VERSION 5.8 ;
BUSBITCHARS "[]" ;
DIVIDERCHAR "/" ;
UNITS
    DATABASE MICRONS 1000 ;
END UNITS

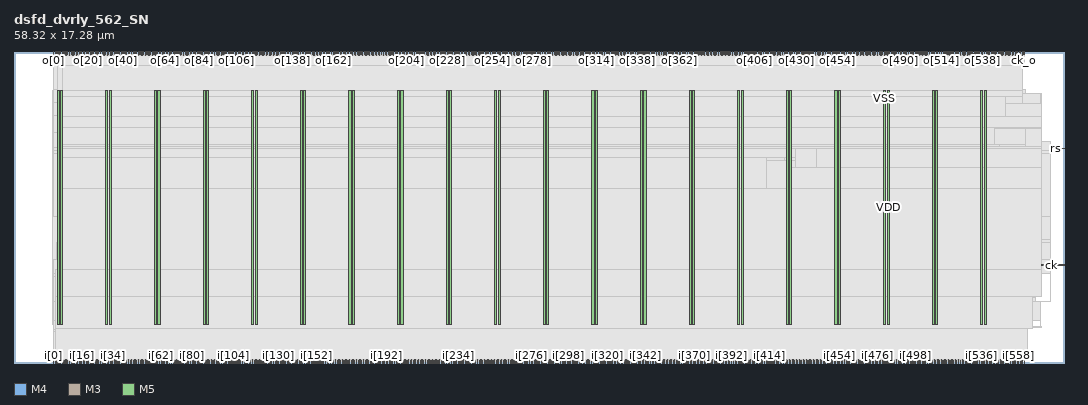
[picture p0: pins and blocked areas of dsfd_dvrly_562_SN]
MACRO dsfd_dvrly_562_SN
  FOREIGN dsfd_dvrly_562_SN 0 0 ;
  CLASS BLOCK ;
  SIZE 58.32 BY 17.28 ;
  PIN ck
    DIRECTION INPUT ;
    USE SIGNAL ;
    PORT
      LAYER M4 ;
        RECT  58.128 5.424 58.32 5.448 ;
    END
    PORT
      LAYER M4 ;
        RECT  57.089 5.424 58.14 5.448 ;
    END
  END ck
  PIN ck_o
    DIRECTION OUTPUT ;
    USE SIGNAL ;
    PORT
      LAYER M3 ;
        RECT  56.088 17.136 56.106 17.28 ;
    END
  END ck_o
  PIN i[0]
    DIRECTION INPUT ;
    USE SIGNAL ;
    PORT
      LAYER M3 ;
        RECT  2.196 0 2.214 0.144 ;
    END
  END i[0]
  PIN i[100]
    DIRECTION INPUT ;
    USE SIGNAL ;
    PORT
      LAYER M3 ;
        RECT  11.808 0 11.826 0.144 ;
    END
  END i[100]
  PIN i[101]
    DIRECTION INPUT ;
    USE SIGNAL ;
    PORT
      LAYER M5 ;
        RECT  11.904 0 11.928 0.192 ;
    END
  END i[101]
  PIN i[102]
    DIRECTION INPUT ;
    USE SIGNAL ;
    PORT
      LAYER M3 ;
        RECT  11.988 0 12.006 0.144 ;
    END
  END i[102]
  PIN i[103]
    DIRECTION INPUT ;
    USE SIGNAL ;
    PORT
      LAYER M5 ;
        RECT  12.096 0 12.12 0.192 ;
    END
  END i[103]
  PIN i[104]
    DIRECTION INPUT ;
    USE SIGNAL ;
    PORT
      LAYER M3 ;
        RECT  12.204 0 12.222 0.144 ;
    END
  END i[104]
  PIN i[105]
    DIRECTION INPUT ;
    USE SIGNAL ;
    PORT
      LAYER M5 ;
        RECT  12.288 0 12.312 0.192 ;
    END
  END i[105]
  PIN i[106]
    DIRECTION INPUT ;
    USE SIGNAL ;
    PORT
      LAYER M3 ;
        RECT  12.384 0 12.402 0.144 ;
    END
  END i[106]
  PIN i[107]
    DIRECTION INPUT ;
    USE SIGNAL ;
    PORT
      LAYER M5 ;
        RECT  12.48 0 12.504 0.192 ;
    END
  END i[107]
  PIN i[108]
    DIRECTION INPUT ;
    USE SIGNAL ;
    PORT
      LAYER M3 ;
        RECT  12.564 0 12.582 0.144 ;
    END
  END i[108]
  PIN i[109]
    DIRECTION INPUT ;
    USE SIGNAL ;
    PORT
      LAYER M5 ;
        RECT  12.672 0 12.696 0.192 ;
    END
  END i[109]
  PIN i[10]
    DIRECTION INPUT ;
    USE SIGNAL ;
    PORT
      LAYER M3 ;
        RECT  3.168 0 3.186 0.144 ;
    END
  END i[10]
  PIN i[110]
    DIRECTION INPUT ;
    USE SIGNAL ;
    PORT
      LAYER M3 ;
        RECT  12.78 0 12.798 0.144 ;
    END
  END i[110]
  PIN i[111]
    DIRECTION INPUT ;
    USE SIGNAL ;
    PORT
      LAYER M5 ;
        RECT  12.864 0 12.888 0.192 ;
    END
  END i[111]
  PIN i[112]
    DIRECTION INPUT ;
    USE SIGNAL ;
    PORT
      LAYER M3 ;
        RECT  12.96 0 12.978 0.144 ;
    END
  END i[112]
  PIN i[113]
    DIRECTION INPUT ;
    USE SIGNAL ;
    PORT
      LAYER M5 ;
        RECT  13.056 0 13.08 0.192 ;
    END
  END i[113]
  PIN i[114]
    DIRECTION INPUT ;
    USE SIGNAL ;
    PORT
      LAYER M3 ;
        RECT  13.14 0 13.158 0.144 ;
    END
  END i[114]
  PIN i[115]
    DIRECTION INPUT ;
    USE SIGNAL ;
    PORT
      LAYER M5 ;
        RECT  13.248 0 13.272 0.192 ;
    END
  END i[115]
  PIN i[116]
    DIRECTION INPUT ;
    USE SIGNAL ;
    PORT
      LAYER M3 ;
        RECT  13.356 0 13.374 0.144 ;
    END
  END i[116]
  PIN i[117]
    DIRECTION INPUT ;
    USE SIGNAL ;
    PORT
      LAYER M5 ;
        RECT  13.44 0 13.464 0.192 ;
    END
  END i[117]
  PIN i[118]
    DIRECTION INPUT ;
    USE SIGNAL ;
    PORT
      LAYER M3 ;
        RECT  13.536 0 13.554 0.144 ;
    END
  END i[118]
  PIN i[119]
    DIRECTION INPUT ;
    USE SIGNAL ;
    PORT
      LAYER M5 ;
        RECT  13.632 0 13.656 0.192 ;
    END
  END i[119]
  PIN i[11]
    DIRECTION INPUT ;
    USE SIGNAL ;
    PORT
      LAYER M5 ;
        RECT  3.264 0 3.288 0.192 ;
    END
  END i[11]
  PIN i[120]
    DIRECTION INPUT ;
    USE SIGNAL ;
    PORT
      LAYER M3 ;
        RECT  13.716 0 13.734 0.144 ;
    END
  END i[120]
  PIN i[121]
    DIRECTION INPUT ;
    USE SIGNAL ;
    PORT
      LAYER M5 ;
        RECT  13.824 0 13.848 0.192 ;
    END
  END i[121]
  PIN i[122]
    DIRECTION INPUT ;
    USE SIGNAL ;
    PORT
      LAYER M3 ;
        RECT  13.932 0 13.95 0.144 ;
    END
  END i[122]
  PIN i[123]
    DIRECTION INPUT ;
    USE SIGNAL ;
    PORT
      LAYER M5 ;
        RECT  14.016 0 14.04 0.192 ;
    END
  END i[123]
  PIN i[124]
    DIRECTION INPUT ;
    USE SIGNAL ;
    PORT
      LAYER M3 ;
        RECT  14.112 0 14.13 0.144 ;
    END
  END i[124]
  PIN i[125]
    DIRECTION INPUT ;
    USE SIGNAL ;
    PORT
      LAYER M5 ;
        RECT  14.208 0 14.232 0.192 ;
    END
  END i[125]
  PIN i[126]
    DIRECTION INPUT ;
    USE SIGNAL ;
    PORT
      LAYER M3 ;
        RECT  14.292 0 14.31 0.144 ;
    END
  END i[126]
  PIN i[127]
    DIRECTION INPUT ;
    USE SIGNAL ;
    PORT
      LAYER M5 ;
        RECT  14.4 0 14.424 0.192 ;
    END
  END i[127]
  PIN i[128]
    DIRECTION INPUT ;
    USE SIGNAL ;
    PORT
      LAYER M3 ;
        RECT  14.508 0 14.526 0.144 ;
    END
  END i[128]
  PIN i[129]
    DIRECTION INPUT ;
    USE SIGNAL ;
    PORT
      LAYER M5 ;
        RECT  14.592 0 14.616 0.192 ;
    END
  END i[129]
  PIN i[12]
    DIRECTION INPUT ;
    USE SIGNAL ;
    PORT
      LAYER M3 ;
        RECT  3.348 0 3.366 0.144 ;
    END
  END i[12]
  PIN i[130]
    DIRECTION INPUT ;
    USE SIGNAL ;
    PORT
      LAYER M3 ;
        RECT  14.688 0 14.706 0.144 ;
    END
  END i[130]
  PIN i[131]
    DIRECTION INPUT ;
    USE SIGNAL ;
    PORT
      LAYER M5 ;
        RECT  14.784 0 14.808 0.192 ;
    END
  END i[131]
  PIN i[132]
    DIRECTION INPUT ;
    USE SIGNAL ;
    PORT
      LAYER M3 ;
        RECT  14.868 0 14.886 0.144 ;
    END
  END i[132]
  PIN i[133]
    DIRECTION INPUT ;
    USE SIGNAL ;
    PORT
      LAYER M5 ;
        RECT  14.976 0 15 0.192 ;
    END
  END i[133]
  PIN i[134]
    DIRECTION INPUT ;
    USE SIGNAL ;
    PORT
      LAYER M3 ;
        RECT  15.084 0 15.102 0.144 ;
    END
  END i[134]
  PIN i[135]
    DIRECTION INPUT ;
    USE SIGNAL ;
    PORT
      LAYER M5 ;
        RECT  15.168 0 15.192 0.192 ;
    END
  END i[135]
  PIN i[136]
    DIRECTION INPUT ;
    USE SIGNAL ;
    PORT
      LAYER M3 ;
        RECT  15.264 0 15.282 0.144 ;
    END
  END i[136]
  PIN i[137]
    DIRECTION INPUT ;
    USE SIGNAL ;
    PORT
      LAYER M5 ;
        RECT  15.36 0 15.384 0.192 ;
    END
  END i[137]
  PIN i[138]
    DIRECTION INPUT ;
    USE SIGNAL ;
    PORT
      LAYER M3 ;
        RECT  15.444 0 15.462 0.144 ;
    END
  END i[138]
  PIN i[139]
    DIRECTION INPUT ;
    USE SIGNAL ;
    PORT
      LAYER M5 ;
        RECT  15.552 0 15.576 0.192 ;
    END
  END i[139]
  PIN i[13]
    DIRECTION INPUT ;
    USE SIGNAL ;
    PORT
      LAYER M5 ;
        RECT  3.456 0 3.48 0.192 ;
    END
  END i[13]
  PIN i[140]
    DIRECTION INPUT ;
    USE SIGNAL ;
    PORT
      LAYER M3 ;
        RECT  15.66 0 15.678 0.144 ;
    END
  END i[140]
  PIN i[141]
    DIRECTION INPUT ;
    USE SIGNAL ;
    PORT
      LAYER M5 ;
        RECT  15.744 0 15.768 0.192 ;
    END
  END i[141]
  PIN i[142]
    DIRECTION INPUT ;
    USE SIGNAL ;
    PORT
      LAYER M3 ;
        RECT  15.84 0 15.858 0.144 ;
    END
  END i[142]
  PIN i[143]
    DIRECTION INPUT ;
    USE SIGNAL ;
    PORT
      LAYER M5 ;
        RECT  15.936 0 15.96 0.192 ;
    END
  END i[143]
  PIN i[144]
    DIRECTION INPUT ;
    USE SIGNAL ;
    PORT
      LAYER M3 ;
        RECT  16.02 0 16.038 0.144 ;
    END
  END i[144]
  PIN i[145]
    DIRECTION INPUT ;
    USE SIGNAL ;
    PORT
      LAYER M5 ;
        RECT  16.128 0 16.152 0.192 ;
    END
  END i[145]
  PIN i[146]
    DIRECTION INPUT ;
    USE SIGNAL ;
    PORT
      LAYER M3 ;
        RECT  16.236 0 16.254 0.144 ;
    END
  END i[146]
  PIN i[147]
    DIRECTION INPUT ;
    USE SIGNAL ;
    PORT
      LAYER M5 ;
        RECT  16.32 0 16.344 0.192 ;
    END
  END i[147]
  PIN i[148]
    DIRECTION INPUT ;
    USE SIGNAL ;
    PORT
      LAYER M3 ;
        RECT  16.416 0 16.434 0.144 ;
    END
  END i[148]
  PIN i[149]
    DIRECTION INPUT ;
    USE SIGNAL ;
    PORT
      LAYER M5 ;
        RECT  16.512 0 16.536 0.192 ;
    END
  END i[149]
  PIN i[14]
    DIRECTION INPUT ;
    USE SIGNAL ;
    PORT
      LAYER M3 ;
        RECT  3.528 0 3.546 0.144 ;
    END
  END i[14]
  PIN i[150]
    DIRECTION INPUT ;
    USE SIGNAL ;
    PORT
      LAYER M3 ;
        RECT  16.596 0 16.614 0.144 ;
    END
  END i[150]
  PIN i[151]
    DIRECTION INPUT ;
    USE SIGNAL ;
    PORT
      LAYER M5 ;
        RECT  16.704 0 16.728 0.192 ;
    END
  END i[151]
  PIN i[152]
    DIRECTION INPUT ;
    USE SIGNAL ;
    PORT
      LAYER M3 ;
        RECT  16.812 0 16.83 0.144 ;
    END
  END i[152]
  PIN i[153]
    DIRECTION INPUT ;
    USE SIGNAL ;
    PORT
      LAYER M5 ;
        RECT  16.896 0 16.92 0.192 ;
    END
  END i[153]
  PIN i[154]
    DIRECTION INPUT ;
    USE SIGNAL ;
    PORT
      LAYER M3 ;
        RECT  16.992 0 17.01 0.144 ;
    END
  END i[154]
  PIN i[155]
    DIRECTION INPUT ;
    USE SIGNAL ;
    PORT
      LAYER M5 ;
        RECT  17.088 0 17.112 0.192 ;
    END
  END i[155]
  PIN i[156]
    DIRECTION INPUT ;
    USE SIGNAL ;
    PORT
      LAYER M3 ;
        RECT  17.172 0 17.19 0.144 ;
    END
  END i[156]
  PIN i[157]
    DIRECTION INPUT ;
    USE SIGNAL ;
    PORT
      LAYER M5 ;
        RECT  17.28 0 17.304 0.192 ;
    END
  END i[157]
  PIN i[158]
    DIRECTION INPUT ;
    USE SIGNAL ;
    PORT
      LAYER M3 ;
        RECT  17.388 0 17.406 0.144 ;
    END
  END i[158]
  PIN i[159]
    DIRECTION INPUT ;
    USE SIGNAL ;
    PORT
      LAYER M5 ;
        RECT  17.472 0 17.496 0.192 ;
    END
  END i[159]
  PIN i[15]
    DIRECTION INPUT ;
    USE SIGNAL ;
    PORT
      LAYER M5 ;
        RECT  3.648 0 3.672 0.192 ;
    END
  END i[15]
  PIN i[160]
    DIRECTION INPUT ;
    USE SIGNAL ;
    PORT
      LAYER M3 ;
        RECT  17.568 0 17.586 0.144 ;
    END
  END i[160]
  PIN i[161]
    DIRECTION INPUT ;
    USE SIGNAL ;
    PORT
      LAYER M5 ;
        RECT  17.664 0 17.688 0.192 ;
    END
  END i[161]
  PIN i[162]
    DIRECTION INPUT ;
    USE SIGNAL ;
    PORT
      LAYER M3 ;
        RECT  17.748 0 17.766 0.144 ;
    END
  END i[162]
  PIN i[163]
    DIRECTION INPUT ;
    USE SIGNAL ;
    PORT
      LAYER M5 ;
        RECT  17.856 0 17.88 0.192 ;
    END
  END i[163]
  PIN i[164]
    DIRECTION INPUT ;
    USE SIGNAL ;
    PORT
      LAYER M3 ;
        RECT  17.964 0 17.982 0.144 ;
    END
  END i[164]
  PIN i[165]
    DIRECTION INPUT ;
    USE SIGNAL ;
    PORT
      LAYER M5 ;
        RECT  18.048 0 18.072 0.192 ;
    END
  END i[165]
  PIN i[166]
    DIRECTION INPUT ;
    USE SIGNAL ;
    PORT
      LAYER M3 ;
        RECT  18.144 0 18.162 0.144 ;
    END
  END i[166]
  PIN i[167]
    DIRECTION INPUT ;
    USE SIGNAL ;
    PORT
      LAYER M5 ;
        RECT  18.24 0 18.264 0.192 ;
    END
  END i[167]
  PIN i[168]
    DIRECTION INPUT ;
    USE SIGNAL ;
    PORT
      LAYER M3 ;
        RECT  18.324 0 18.342 0.144 ;
    END
  END i[168]
  PIN i[169]
    DIRECTION INPUT ;
    USE SIGNAL ;
    PORT
      LAYER M5 ;
        RECT  18.432 0 18.456 0.192 ;
    END
  END i[169]
  PIN i[16]
    DIRECTION INPUT ;
    USE SIGNAL ;
    PORT
      LAYER M3 ;
        RECT  3.744 0 3.762 0.144 ;
    END
  END i[16]
  PIN i[170]
    DIRECTION INPUT ;
    USE SIGNAL ;
    PORT
      LAYER M3 ;
        RECT  18.54 0 18.558 0.144 ;
    END
  END i[170]
  PIN i[171]
    DIRECTION INPUT ;
    USE SIGNAL ;
    PORT
      LAYER M5 ;
        RECT  18.624 0 18.648 0.192 ;
    END
  END i[171]
  PIN i[172]
    DIRECTION INPUT ;
    USE SIGNAL ;
    PORT
      LAYER M3 ;
        RECT  18.72 0 18.738 0.144 ;
    END
  END i[172]
  PIN i[173]
    DIRECTION INPUT ;
    USE SIGNAL ;
    PORT
      LAYER M5 ;
        RECT  18.816 0 18.84 0.192 ;
    END
  END i[173]
  PIN i[174]
    DIRECTION INPUT ;
    USE SIGNAL ;
    PORT
      LAYER M3 ;
        RECT  18.9 0 18.918 0.144 ;
    END
  END i[174]
  PIN i[175]
    DIRECTION INPUT ;
    USE SIGNAL ;
    PORT
      LAYER M5 ;
        RECT  19.008 0 19.032 0.192 ;
    END
  END i[175]
  PIN i[176]
    DIRECTION INPUT ;
    USE SIGNAL ;
    PORT
      LAYER M3 ;
        RECT  19.116 0 19.134 0.144 ;
    END
  END i[176]
  PIN i[177]
    DIRECTION INPUT ;
    USE SIGNAL ;
    PORT
      LAYER M5 ;
        RECT  19.2 0 19.224 0.192 ;
    END
  END i[177]
  PIN i[178]
    DIRECTION INPUT ;
    USE SIGNAL ;
    PORT
      LAYER M3 ;
        RECT  19.296 0 19.314 0.144 ;
    END
  END i[178]
  PIN i[179]
    DIRECTION INPUT ;
    USE SIGNAL ;
    PORT
      LAYER M5 ;
        RECT  19.392 0 19.416 0.192 ;
    END
  END i[179]
  PIN i[17]
    DIRECTION INPUT ;
    USE SIGNAL ;
    PORT
      LAYER M5 ;
        RECT  3.84 0 3.864 0.192 ;
    END
  END i[17]
  PIN i[180]
    DIRECTION INPUT ;
    USE SIGNAL ;
    PORT
      LAYER M3 ;
        RECT  19.512 0 19.53 0.144 ;
    END
  END i[180]
  PIN i[181]
    DIRECTION INPUT ;
    USE SIGNAL ;
    PORT
      LAYER M5 ;
        RECT  19.584 0 19.608 0.192 ;
    END
  END i[181]
  PIN i[182]
    DIRECTION INPUT ;
    USE SIGNAL ;
    PORT
      LAYER M3 ;
        RECT  19.692 0 19.71 0.144 ;
    END
  END i[182]
  PIN i[183]
    DIRECTION INPUT ;
    USE SIGNAL ;
    PORT
      LAYER M5 ;
        RECT  19.776 0 19.8 0.192 ;
    END
  END i[183]
  PIN i[184]
    DIRECTION INPUT ;
    USE SIGNAL ;
    PORT
      LAYER M3 ;
        RECT  19.872 0 19.89 0.144 ;
    END
  END i[184]
  PIN i[185]
    DIRECTION INPUT ;
    USE SIGNAL ;
    PORT
      LAYER M5 ;
        RECT  19.968 0 19.992 0.192 ;
    END
  END i[185]
  PIN i[186]
    DIRECTION INPUT ;
    USE SIGNAL ;
    PORT
      LAYER M3 ;
        RECT  20.088 0 20.106 0.144 ;
    END
  END i[186]
  PIN i[187]
    DIRECTION INPUT ;
    USE SIGNAL ;
    PORT
      LAYER M5 ;
        RECT  20.16 0 20.184 0.192 ;
    END
  END i[187]
  PIN i[188]
    DIRECTION INPUT ;
    USE SIGNAL ;
    PORT
      LAYER M3 ;
        RECT  20.268 0 20.286 0.144 ;
    END
  END i[188]
  PIN i[189]
    DIRECTION INPUT ;
    USE SIGNAL ;
    PORT
      LAYER M5 ;
        RECT  20.352 0 20.376 0.192 ;
    END
  END i[189]
  PIN i[18]
    DIRECTION INPUT ;
    USE SIGNAL ;
    PORT
      LAYER M3 ;
        RECT  3.924 0 3.942 0.144 ;
    END
  END i[18]
  PIN i[190]
    DIRECTION INPUT ;
    USE SIGNAL ;
    PORT
      LAYER M3 ;
        RECT  20.448 0 20.466 0.144 ;
    END
  END i[190]
  PIN i[191]
    DIRECTION INPUT ;
    USE SIGNAL ;
    PORT
      LAYER M5 ;
        RECT  20.544 0 20.568 0.192 ;
    END
  END i[191]
  PIN i[192]
    DIRECTION INPUT ;
    USE SIGNAL ;
    PORT
      LAYER M3 ;
        RECT  20.664 0 20.682 0.144 ;
    END
  END i[192]
  PIN i[193]
    DIRECTION INPUT ;
    USE SIGNAL ;
    PORT
      LAYER M5 ;
        RECT  20.736 0 20.76 0.192 ;
    END
  END i[193]
  PIN i[194]
    DIRECTION INPUT ;
    USE SIGNAL ;
    PORT
      LAYER M3 ;
        RECT  20.844 0 20.862 0.144 ;
    END
  END i[194]
  PIN i[195]
    DIRECTION INPUT ;
    USE SIGNAL ;
    PORT
      LAYER M5 ;
        RECT  20.928 0 20.952 0.192 ;
    END
  END i[195]
  PIN i[196]
    DIRECTION INPUT ;
    USE SIGNAL ;
    PORT
      LAYER M3 ;
        RECT  21.024 0 21.042 0.144 ;
    END
  END i[196]
  PIN i[197]
    DIRECTION INPUT ;
    USE SIGNAL ;
    PORT
      LAYER M5 ;
        RECT  21.12 0 21.144 0.192 ;
    END
  END i[197]
  PIN i[198]
    DIRECTION INPUT ;
    USE SIGNAL ;
    PORT
      LAYER M3 ;
        RECT  21.24 0 21.258 0.144 ;
    END
  END i[198]
  PIN i[199]
    DIRECTION INPUT ;
    USE SIGNAL ;
    PORT
      LAYER M5 ;
        RECT  21.312 0 21.336 0.192 ;
    END
  END i[199]
  PIN i[19]
    DIRECTION INPUT ;
    USE SIGNAL ;
    PORT
      LAYER M5 ;
        RECT  4.032 0 4.056 0.192 ;
    END
  END i[19]
  PIN i[1]
    DIRECTION INPUT ;
    USE SIGNAL ;
    PORT
      LAYER M5 ;
        RECT  2.304 0 2.328 0.192 ;
    END
  END i[1]
  PIN i[200]
    DIRECTION INPUT ;
    USE SIGNAL ;
    PORT
      LAYER M3 ;
        RECT  21.42 0 21.438 0.144 ;
    END
  END i[200]
  PIN i[201]
    DIRECTION INPUT ;
    USE SIGNAL ;
    PORT
      LAYER M5 ;
        RECT  21.504 0 21.528 0.192 ;
    END
  END i[201]
  PIN i[202]
    DIRECTION INPUT ;
    USE SIGNAL ;
    PORT
      LAYER M3 ;
        RECT  21.6 0 21.618 0.144 ;
    END
  END i[202]
  PIN i[203]
    DIRECTION INPUT ;
    USE SIGNAL ;
    PORT
      LAYER M5 ;
        RECT  21.696 0 21.72 0.192 ;
    END
  END i[203]
  PIN i[204]
    DIRECTION INPUT ;
    USE SIGNAL ;
    PORT
      LAYER M3 ;
        RECT  21.816 0 21.834 0.144 ;
    END
  END i[204]
  PIN i[205]
    DIRECTION INPUT ;
    USE SIGNAL ;
    PORT
      LAYER M5 ;
        RECT  21.888 0 21.912 0.192 ;
    END
  END i[205]
  PIN i[206]
    DIRECTION INPUT ;
    USE SIGNAL ;
    PORT
      LAYER M3 ;
        RECT  21.996 0 22.014 0.144 ;
    END
  END i[206]
  PIN i[207]
    DIRECTION INPUT ;
    USE SIGNAL ;
    PORT
      LAYER M5 ;
        RECT  22.08 0 22.104 0.192 ;
    END
  END i[207]
  PIN i[208]
    DIRECTION INPUT ;
    USE SIGNAL ;
    PORT
      LAYER M3 ;
        RECT  22.176 0 22.194 0.144 ;
    END
  END i[208]
  PIN i[209]
    DIRECTION INPUT ;
    USE SIGNAL ;
    PORT
      LAYER M5 ;
        RECT  22.272 0 22.296 0.192 ;
    END
  END i[209]
  PIN i[20]
    DIRECTION INPUT ;
    USE SIGNAL ;
    PORT
      LAYER M3 ;
        RECT  4.104 0 4.122 0.144 ;
    END
  END i[20]
  PIN i[210]
    DIRECTION INPUT ;
    USE SIGNAL ;
    PORT
      LAYER M3 ;
        RECT  22.392 0 22.41 0.144 ;
    END
  END i[210]
  PIN i[211]
    DIRECTION INPUT ;
    USE SIGNAL ;
    PORT
      LAYER M5 ;
        RECT  22.464 0 22.488 0.192 ;
    END
  END i[211]
  PIN i[212]
    DIRECTION INPUT ;
    USE SIGNAL ;
    PORT
      LAYER M3 ;
        RECT  22.572 0 22.59 0.144 ;
    END
  END i[212]
  PIN i[213]
    DIRECTION INPUT ;
    USE SIGNAL ;
    PORT
      LAYER M5 ;
        RECT  22.656 0 22.68 0.192 ;
    END
  END i[213]
  PIN i[214]
    DIRECTION INPUT ;
    USE SIGNAL ;
    PORT
      LAYER M3 ;
        RECT  22.752 0 22.77 0.144 ;
    END
  END i[214]
  PIN i[215]
    DIRECTION INPUT ;
    USE SIGNAL ;
    PORT
      LAYER M5 ;
        RECT  22.848 0 22.872 0.192 ;
    END
  END i[215]
  PIN i[216]
    DIRECTION INPUT ;
    USE SIGNAL ;
    PORT
      LAYER M3 ;
        RECT  22.968 0 22.986 0.144 ;
    END
  END i[216]
  PIN i[217]
    DIRECTION INPUT ;
    USE SIGNAL ;
    PORT
      LAYER M5 ;
        RECT  23.04 0 23.064 0.192 ;
    END
  END i[217]
  PIN i[218]
    DIRECTION INPUT ;
    USE SIGNAL ;
    PORT
      LAYER M3 ;
        RECT  23.148 0 23.166 0.144 ;
    END
  END i[218]
  PIN i[219]
    DIRECTION INPUT ;
    USE SIGNAL ;
    PORT
      LAYER M5 ;
        RECT  23.232 0 23.256 0.192 ;
    END
  END i[219]
  PIN i[21]
    DIRECTION INPUT ;
    USE SIGNAL ;
    PORT
      LAYER M5 ;
        RECT  4.224 0 4.248 0.192 ;
    END
  END i[21]
  PIN i[220]
    DIRECTION INPUT ;
    USE SIGNAL ;
    PORT
      LAYER M3 ;
        RECT  23.328 0 23.346 0.144 ;
    END
  END i[220]
  PIN i[221]
    DIRECTION INPUT ;
    USE SIGNAL ;
    PORT
      LAYER M5 ;
        RECT  23.424 0 23.448 0.192 ;
    END
  END i[221]
  PIN i[222]
    DIRECTION INPUT ;
    USE SIGNAL ;
    PORT
      LAYER M3 ;
        RECT  23.544 0 23.562 0.144 ;
    END
  END i[222]
  PIN i[223]
    DIRECTION INPUT ;
    USE SIGNAL ;
    PORT
      LAYER M5 ;
        RECT  23.616 0 23.64 0.192 ;
    END
  END i[223]
  PIN i[224]
    DIRECTION INPUT ;
    USE SIGNAL ;
    PORT
      LAYER M3 ;
        RECT  23.724 0 23.742 0.144 ;
    END
  END i[224]
  PIN i[225]
    DIRECTION INPUT ;
    USE SIGNAL ;
    PORT
      LAYER M5 ;
        RECT  23.808 0 23.832 0.192 ;
    END
  END i[225]
  PIN i[226]
    DIRECTION INPUT ;
    USE SIGNAL ;
    PORT
      LAYER M3 ;
        RECT  23.904 0 23.922 0.144 ;
    END
  END i[226]
  PIN i[227]
    DIRECTION INPUT ;
    USE SIGNAL ;
    PORT
      LAYER M5 ;
        RECT  24 0 24.024 0.192 ;
    END
  END i[227]
  PIN i[228]
    DIRECTION INPUT ;
    USE SIGNAL ;
    PORT
      LAYER M3 ;
        RECT  24.12 0 24.138 0.144 ;
    END
  END i[228]
  PIN i[229]
    DIRECTION INPUT ;
    USE SIGNAL ;
    PORT
      LAYER M5 ;
        RECT  24.192 0 24.216 0.192 ;
    END
  END i[229]
  PIN i[22]
    DIRECTION INPUT ;
    USE SIGNAL ;
    PORT
      LAYER M3 ;
        RECT  4.32 0 4.338 0.144 ;
    END
  END i[22]
  PIN i[230]
    DIRECTION INPUT ;
    USE SIGNAL ;
    PORT
      LAYER M3 ;
        RECT  24.3 0 24.318 0.144 ;
    END
  END i[230]
  PIN i[231]
    DIRECTION INPUT ;
    USE SIGNAL ;
    PORT
      LAYER M5 ;
        RECT  24.384 0 24.408 0.192 ;
    END
  END i[231]
  PIN i[232]
    DIRECTION INPUT ;
    USE SIGNAL ;
    PORT
      LAYER M3 ;
        RECT  24.48 0 24.498 0.144 ;
    END
  END i[232]
  PIN i[233]
    DIRECTION INPUT ;
    USE SIGNAL ;
    PORT
      LAYER M5 ;
        RECT  24.576 0 24.6 0.192 ;
    END
  END i[233]
  PIN i[234]
    DIRECTION INPUT ;
    USE SIGNAL ;
    PORT
      LAYER M3 ;
        RECT  24.696 0 24.714 0.144 ;
    END
  END i[234]
  PIN i[235]
    DIRECTION INPUT ;
    USE SIGNAL ;
    PORT
      LAYER M5 ;
        RECT  24.768 0 24.792 0.192 ;
    END
  END i[235]
  PIN i[236]
    DIRECTION INPUT ;
    USE SIGNAL ;
    PORT
      LAYER M3 ;
        RECT  24.876 0 24.894 0.144 ;
    END
  END i[236]
  PIN i[237]
    DIRECTION INPUT ;
    USE SIGNAL ;
    PORT
      LAYER M5 ;
        RECT  24.96 0 24.984 0.192 ;
    END
  END i[237]
  PIN i[238]
    DIRECTION INPUT ;
    USE SIGNAL ;
    PORT
      LAYER M3 ;
        RECT  25.056 0 25.074 0.144 ;
    END
  END i[238]
  PIN i[239]
    DIRECTION INPUT ;
    USE SIGNAL ;
    PORT
      LAYER M5 ;
        RECT  25.152 0 25.176 0.192 ;
    END
  END i[239]
  PIN i[23]
    DIRECTION INPUT ;
    USE SIGNAL ;
    PORT
      LAYER M5 ;
        RECT  4.416 0 4.44 0.192 ;
    END
  END i[23]
  PIN i[240]
    DIRECTION INPUT ;
    USE SIGNAL ;
    PORT
      LAYER M3 ;
        RECT  25.272 0 25.29 0.144 ;
    END
  END i[240]
  PIN i[241]
    DIRECTION INPUT ;
    USE SIGNAL ;
    PORT
      LAYER M5 ;
        RECT  25.344 0 25.368 0.192 ;
    END
  END i[241]
  PIN i[242]
    DIRECTION INPUT ;
    USE SIGNAL ;
    PORT
      LAYER M3 ;
        RECT  25.452 0 25.47 0.144 ;
    END
  END i[242]
  PIN i[243]
    DIRECTION INPUT ;
    USE SIGNAL ;
    PORT
      LAYER M5 ;
        RECT  25.536 0 25.56 0.192 ;
    END
  END i[243]
  PIN i[244]
    DIRECTION INPUT ;
    USE SIGNAL ;
    PORT
      LAYER M3 ;
        RECT  25.632 0 25.65 0.144 ;
    END
  END i[244]
  PIN i[245]
    DIRECTION INPUT ;
    USE SIGNAL ;
    PORT
      LAYER M5 ;
        RECT  25.728 0 25.752 0.192 ;
    END
  END i[245]
  PIN i[246]
    DIRECTION INPUT ;
    USE SIGNAL ;
    PORT
      LAYER M3 ;
        RECT  25.848 0 25.866 0.144 ;
    END
  END i[246]
  PIN i[247]
    DIRECTION INPUT ;
    USE SIGNAL ;
    PORT
      LAYER M5 ;
        RECT  25.92 0 25.944 0.192 ;
    END
  END i[247]
  PIN i[248]
    DIRECTION INPUT ;
    USE SIGNAL ;
    PORT
      LAYER M3 ;
        RECT  26.028 0 26.046 0.144 ;
    END
  END i[248]
  PIN i[249]
    DIRECTION INPUT ;
    USE SIGNAL ;
    PORT
      LAYER M5 ;
        RECT  26.112 0 26.136 0.192 ;
    END
  END i[249]
  PIN i[24]
    DIRECTION INPUT ;
    USE SIGNAL ;
    PORT
      LAYER M3 ;
        RECT  4.5 0 4.518 0.144 ;
    END
  END i[24]
  PIN i[250]
    DIRECTION INPUT ;
    USE SIGNAL ;
    PORT
      LAYER M3 ;
        RECT  26.208 0 26.226 0.144 ;
    END
  END i[250]
  PIN i[251]
    DIRECTION INPUT ;
    USE SIGNAL ;
    PORT
      LAYER M5 ;
        RECT  26.304 0 26.328 0.192 ;
    END
  END i[251]
  PIN i[252]
    DIRECTION INPUT ;
    USE SIGNAL ;
    PORT
      LAYER M3 ;
        RECT  26.424 0 26.442 0.144 ;
    END
  END i[252]
  PIN i[253]
    DIRECTION INPUT ;
    USE SIGNAL ;
    PORT
      LAYER M5 ;
        RECT  26.496 0 26.52 0.192 ;
    END
  END i[253]
  PIN i[254]
    DIRECTION INPUT ;
    USE SIGNAL ;
    PORT
      LAYER M3 ;
        RECT  26.604 0 26.622 0.144 ;
    END
  END i[254]
  PIN i[255]
    DIRECTION INPUT ;
    USE SIGNAL ;
    PORT
      LAYER M5 ;
        RECT  26.688 0 26.712 0.192 ;
    END
  END i[255]
  PIN i[256]
    DIRECTION INPUT ;
    USE SIGNAL ;
    PORT
      LAYER M3 ;
        RECT  26.784 0 26.802 0.144 ;
    END
  END i[256]
  PIN i[257]
    DIRECTION INPUT ;
    USE SIGNAL ;
    PORT
      LAYER M5 ;
        RECT  26.88 0 26.904 0.192 ;
    END
  END i[257]
  PIN i[258]
    DIRECTION INPUT ;
    USE SIGNAL ;
    PORT
      LAYER M3 ;
        RECT  27 0 27.018 0.144 ;
    END
  END i[258]
  PIN i[259]
    DIRECTION INPUT ;
    USE SIGNAL ;
    PORT
      LAYER M5 ;
        RECT  27.072 0 27.096 0.192 ;
    END
  END i[259]
  PIN i[25]
    DIRECTION INPUT ;
    USE SIGNAL ;
    PORT
      LAYER M5 ;
        RECT  4.608 0 4.632 0.192 ;
    END
  END i[25]
  PIN i[260]
    DIRECTION INPUT ;
    USE SIGNAL ;
    PORT
      LAYER M3 ;
        RECT  27.18 0 27.198 0.144 ;
    END
  END i[260]
  PIN i[261]
    DIRECTION INPUT ;
    USE SIGNAL ;
    PORT
      LAYER M5 ;
        RECT  27.264 0 27.288 0.192 ;
    END
  END i[261]
  PIN i[262]
    DIRECTION INPUT ;
    USE SIGNAL ;
    PORT
      LAYER M3 ;
        RECT  27.36 0 27.378 0.144 ;
    END
  END i[262]
  PIN i[263]
    DIRECTION INPUT ;
    USE SIGNAL ;
    PORT
      LAYER M5 ;
        RECT  27.456 0 27.48 0.192 ;
    END
  END i[263]
  PIN i[264]
    DIRECTION INPUT ;
    USE SIGNAL ;
    PORT
      LAYER M3 ;
        RECT  27.576 0 27.594 0.144 ;
    END
  END i[264]
  PIN i[265]
    DIRECTION INPUT ;
    USE SIGNAL ;
    PORT
      LAYER M5 ;
        RECT  27.648 0 27.672 0.192 ;
    END
  END i[265]
  PIN i[266]
    DIRECTION INPUT ;
    USE SIGNAL ;
    PORT
      LAYER M3 ;
        RECT  27.756 0 27.774 0.144 ;
    END
  END i[266]
  PIN i[267]
    DIRECTION INPUT ;
    USE SIGNAL ;
    PORT
      LAYER M5 ;
        RECT  27.84 0 27.864 0.192 ;
    END
  END i[267]
  PIN i[268]
    DIRECTION INPUT ;
    USE SIGNAL ;
    PORT
      LAYER M3 ;
        RECT  27.936 0 27.954 0.144 ;
    END
  END i[268]
  PIN i[269]
    DIRECTION INPUT ;
    USE SIGNAL ;
    PORT
      LAYER M5 ;
        RECT  28.032 0 28.056 0.192 ;
    END
  END i[269]
  PIN i[26]
    DIRECTION INPUT ;
    USE SIGNAL ;
    PORT
      LAYER M3 ;
        RECT  4.68 0 4.698 0.144 ;
    END
  END i[26]
  PIN i[270]
    DIRECTION INPUT ;
    USE SIGNAL ;
    PORT
      LAYER M3 ;
        RECT  28.152 0 28.17 0.144 ;
    END
  END i[270]
  PIN i[271]
    DIRECTION INPUT ;
    USE SIGNAL ;
    PORT
      LAYER M5 ;
        RECT  28.224 0 28.248 0.192 ;
    END
  END i[271]
  PIN i[272]
    DIRECTION INPUT ;
    USE SIGNAL ;
    PORT
      LAYER M3 ;
        RECT  28.332 0 28.35 0.144 ;
    END
  END i[272]
  PIN i[273]
    DIRECTION INPUT ;
    USE SIGNAL ;
    PORT
      LAYER M5 ;
        RECT  28.416 0 28.44 0.192 ;
    END
  END i[273]
  PIN i[274]
    DIRECTION INPUT ;
    USE SIGNAL ;
    PORT
      LAYER M3 ;
        RECT  28.512 0 28.53 0.144 ;
    END
  END i[274]
  PIN i[275]
    DIRECTION INPUT ;
    USE SIGNAL ;
    PORT
      LAYER M5 ;
        RECT  28.608 0 28.632 0.192 ;
    END
  END i[275]
  PIN i[276]
    DIRECTION INPUT ;
    USE SIGNAL ;
    PORT
      LAYER M3 ;
        RECT  28.728 0 28.746 0.144 ;
    END
  END i[276]
  PIN i[277]
    DIRECTION INPUT ;
    USE SIGNAL ;
    PORT
      LAYER M5 ;
        RECT  28.8 0 28.824 0.192 ;
    END
  END i[277]
  PIN i[278]
    DIRECTION INPUT ;
    USE SIGNAL ;
    PORT
      LAYER M3 ;
        RECT  28.908 0 28.926 0.144 ;
    END
  END i[278]
  PIN i[279]
    DIRECTION INPUT ;
    USE SIGNAL ;
    PORT
      LAYER M5 ;
        RECT  28.992 0 29.016 0.192 ;
    END
  END i[279]
  PIN i[27]
    DIRECTION INPUT ;
    USE SIGNAL ;
    PORT
      LAYER M5 ;
        RECT  4.8 0 4.824 0.192 ;
    END
  END i[27]
  PIN i[280]
    DIRECTION INPUT ;
    USE SIGNAL ;
    PORT
      LAYER M3 ;
        RECT  29.088 0 29.106 0.144 ;
    END
  END i[280]
  PIN i[281]
    DIRECTION INPUT ;
    USE SIGNAL ;
    PORT
      LAYER M5 ;
        RECT  29.184 0 29.208 0.192 ;
    END
  END i[281]
  PIN i[282]
    DIRECTION INPUT ;
    USE SIGNAL ;
    PORT
      LAYER M3 ;
        RECT  29.304 0 29.322 0.144 ;
    END
  END i[282]
  PIN i[283]
    DIRECTION INPUT ;
    USE SIGNAL ;
    PORT
      LAYER M5 ;
        RECT  29.376 0 29.4 0.192 ;
    END
  END i[283]
  PIN i[284]
    DIRECTION INPUT ;
    USE SIGNAL ;
    PORT
      LAYER M3 ;
        RECT  29.484 0 29.502 0.144 ;
    END
  END i[284]
  PIN i[285]
    DIRECTION INPUT ;
    USE SIGNAL ;
    PORT
      LAYER M5 ;
        RECT  29.568 0 29.592 0.192 ;
    END
  END i[285]
  PIN i[286]
    DIRECTION INPUT ;
    USE SIGNAL ;
    PORT
      LAYER M3 ;
        RECT  29.664 0 29.682 0.144 ;
    END
  END i[286]
  PIN i[287]
    DIRECTION INPUT ;
    USE SIGNAL ;
    PORT
      LAYER M5 ;
        RECT  29.76 0 29.784 0.192 ;
    END
  END i[287]
  PIN i[288]
    DIRECTION INPUT ;
    USE SIGNAL ;
    PORT
      LAYER M3 ;
        RECT  29.88 0 29.898 0.144 ;
    END
  END i[288]
  PIN i[289]
    DIRECTION INPUT ;
    USE SIGNAL ;
    PORT
      LAYER M5 ;
        RECT  29.952 0 29.976 0.192 ;
    END
  END i[289]
  PIN i[28]
    DIRECTION INPUT ;
    USE SIGNAL ;
    PORT
      LAYER M3 ;
        RECT  4.896 0 4.914 0.144 ;
    END
  END i[28]
  PIN i[290]
    DIRECTION INPUT ;
    USE SIGNAL ;
    PORT
      LAYER M3 ;
        RECT  30.06 0 30.078 0.144 ;
    END
  END i[290]
  PIN i[291]
    DIRECTION INPUT ;
    USE SIGNAL ;
    PORT
      LAYER M5 ;
        RECT  30.144 0 30.168 0.192 ;
    END
  END i[291]
  PIN i[292]
    DIRECTION INPUT ;
    USE SIGNAL ;
    PORT
      LAYER M3 ;
        RECT  30.24 0 30.258 0.144 ;
    END
  END i[292]
  PIN i[293]
    DIRECTION INPUT ;
    USE SIGNAL ;
    PORT
      LAYER M5 ;
        RECT  30.336 0 30.36 0.192 ;
    END
  END i[293]
  PIN i[294]
    DIRECTION INPUT ;
    USE SIGNAL ;
    PORT
      LAYER M3 ;
        RECT  30.456 0 30.474 0.144 ;
    END
  END i[294]
  PIN i[295]
    DIRECTION INPUT ;
    USE SIGNAL ;
    PORT
      LAYER M5 ;
        RECT  30.528 0 30.552 0.192 ;
    END
  END i[295]
  PIN i[296]
    DIRECTION INPUT ;
    USE SIGNAL ;
    PORT
      LAYER M3 ;
        RECT  30.636 0 30.654 0.144 ;
    END
  END i[296]
  PIN i[297]
    DIRECTION INPUT ;
    USE SIGNAL ;
    PORT
      LAYER M5 ;
        RECT  30.72 0 30.744 0.192 ;
    END
  END i[297]
  PIN i[298]
    DIRECTION INPUT ;
    USE SIGNAL ;
    PORT
      LAYER M3 ;
        RECT  30.816 0 30.834 0.144 ;
    END
  END i[298]
  PIN i[299]
    DIRECTION INPUT ;
    USE SIGNAL ;
    PORT
      LAYER M5 ;
        RECT  30.912 0 30.936 0.192 ;
    END
  END i[299]
  PIN i[29]
    DIRECTION INPUT ;
    USE SIGNAL ;
    PORT
      LAYER M5 ;
        RECT  4.992 0 5.016 0.192 ;
    END
  END i[29]
  PIN i[2]
    DIRECTION INPUT ;
    USE SIGNAL ;
    PORT
      LAYER M3 ;
        RECT  2.376 0 2.394 0.144 ;
    END
  END i[2]
  PIN i[300]
    DIRECTION INPUT ;
    USE SIGNAL ;
    PORT
      LAYER M3 ;
        RECT  31.032 0 31.05 0.144 ;
    END
  END i[300]
  PIN i[301]
    DIRECTION INPUT ;
    USE SIGNAL ;
    PORT
      LAYER M5 ;
        RECT  31.104 0 31.128 0.192 ;
    END
  END i[301]
  PIN i[302]
    DIRECTION INPUT ;
    USE SIGNAL ;
    PORT
      LAYER M3 ;
        RECT  31.212 0 31.23 0.144 ;
    END
  END i[302]
  PIN i[303]
    DIRECTION INPUT ;
    USE SIGNAL ;
    PORT
      LAYER M5 ;
        RECT  31.296 0 31.32 0.192 ;
    END
  END i[303]
  PIN i[304]
    DIRECTION INPUT ;
    USE SIGNAL ;
    PORT
      LAYER M3 ;
        RECT  31.392 0 31.41 0.144 ;
    END
  END i[304]
  PIN i[305]
    DIRECTION INPUT ;
    USE SIGNAL ;
    PORT
      LAYER M5 ;
        RECT  31.488 0 31.512 0.192 ;
    END
  END i[305]
  PIN i[306]
    DIRECTION INPUT ;
    USE SIGNAL ;
    PORT
      LAYER M3 ;
        RECT  31.608 0 31.626 0.144 ;
    END
  END i[306]
  PIN i[307]
    DIRECTION INPUT ;
    USE SIGNAL ;
    PORT
      LAYER M5 ;
        RECT  31.68 0 31.704 0.192 ;
    END
  END i[307]
  PIN i[308]
    DIRECTION INPUT ;
    USE SIGNAL ;
    PORT
      LAYER M3 ;
        RECT  31.788 0 31.806 0.144 ;
    END
  END i[308]
  PIN i[309]
    DIRECTION INPUT ;
    USE SIGNAL ;
    PORT
      LAYER M5 ;
        RECT  31.872 0 31.896 0.192 ;
    END
  END i[309]
  PIN i[30]
    DIRECTION INPUT ;
    USE SIGNAL ;
    PORT
      LAYER M3 ;
        RECT  5.076 0 5.094 0.144 ;
    END
  END i[30]
  PIN i[310]
    DIRECTION INPUT ;
    USE SIGNAL ;
    PORT
      LAYER M3 ;
        RECT  31.968 0 31.986 0.144 ;
    END
  END i[310]
  PIN i[311]
    DIRECTION INPUT ;
    USE SIGNAL ;
    PORT
      LAYER M5 ;
        RECT  32.064 0 32.088 0.192 ;
    END
  END i[311]
  PIN i[312]
    DIRECTION INPUT ;
    USE SIGNAL ;
    PORT
      LAYER M3 ;
        RECT  32.184 0 32.202 0.144 ;
    END
  END i[312]
  PIN i[313]
    DIRECTION INPUT ;
    USE SIGNAL ;
    PORT
      LAYER M5 ;
        RECT  32.256 0 32.28 0.192 ;
    END
  END i[313]
  PIN i[314]
    DIRECTION INPUT ;
    USE SIGNAL ;
    PORT
      LAYER M3 ;
        RECT  32.364 0 32.382 0.144 ;
    END
  END i[314]
  PIN i[315]
    DIRECTION INPUT ;
    USE SIGNAL ;
    PORT
      LAYER M5 ;
        RECT  32.448 0 32.472 0.192 ;
    END
  END i[315]
  PIN i[316]
    DIRECTION INPUT ;
    USE SIGNAL ;
    PORT
      LAYER M3 ;
        RECT  32.58 0 32.598 0.144 ;
    END
  END i[316]
  PIN i[317]
    DIRECTION INPUT ;
    USE SIGNAL ;
    PORT
      LAYER M5 ;
        RECT  32.64 0 32.664 0.192 ;
    END
  END i[317]
  PIN i[318]
    DIRECTION INPUT ;
    USE SIGNAL ;
    PORT
      LAYER M3 ;
        RECT  32.76 0 32.778 0.144 ;
    END
  END i[318]
  PIN i[319]
    DIRECTION INPUT ;
    USE SIGNAL ;
    PORT
      LAYER M5 ;
        RECT  32.832 0 32.856 0.192 ;
    END
  END i[319]
  PIN i[31]
    DIRECTION INPUT ;
    USE SIGNAL ;
    PORT
      LAYER M5 ;
        RECT  5.184 0 5.208 0.192 ;
    END
  END i[31]
  PIN i[320]
    DIRECTION INPUT ;
    USE SIGNAL ;
    PORT
      LAYER M3 ;
        RECT  32.94 0 32.958 0.144 ;
    END
  END i[320]
  PIN i[321]
    DIRECTION INPUT ;
    USE SIGNAL ;
    PORT
      LAYER M5 ;
        RECT  33.024 0 33.048 0.192 ;
    END
  END i[321]
  PIN i[322]
    DIRECTION INPUT ;
    USE SIGNAL ;
    PORT
      LAYER M3 ;
        RECT  33.156 0 33.174 0.144 ;
    END
  END i[322]
  PIN i[323]
    DIRECTION INPUT ;
    USE SIGNAL ;
    PORT
      LAYER M5 ;
        RECT  33.216 0 33.24 0.192 ;
    END
  END i[323]
  PIN i[324]
    DIRECTION INPUT ;
    USE SIGNAL ;
    PORT
      LAYER M3 ;
        RECT  33.336 0 33.354 0.144 ;
    END
  END i[324]
  PIN i[325]
    DIRECTION INPUT ;
    USE SIGNAL ;
    PORT
      LAYER M5 ;
        RECT  33.408 0 33.432 0.192 ;
    END
  END i[325]
  PIN i[326]
    DIRECTION INPUT ;
    USE SIGNAL ;
    PORT
      LAYER M3 ;
        RECT  33.516 0 33.534 0.144 ;
    END
  END i[326]
  PIN i[327]
    DIRECTION INPUT ;
    USE SIGNAL ;
    PORT
      LAYER M5 ;
        RECT  33.6 0 33.624 0.192 ;
    END
  END i[327]
  PIN i[328]
    DIRECTION INPUT ;
    USE SIGNAL ;
    PORT
      LAYER M3 ;
        RECT  33.732 0 33.75 0.144 ;
    END
  END i[328]
  PIN i[329]
    DIRECTION INPUT ;
    USE SIGNAL ;
    PORT
      LAYER M5 ;
        RECT  33.792 0 33.816 0.192 ;
    END
  END i[329]
  PIN i[32]
    DIRECTION INPUT ;
    USE SIGNAL ;
    PORT
      LAYER M3 ;
        RECT  5.256 0 5.274 0.144 ;
    END
  END i[32]
  PIN i[330]
    DIRECTION INPUT ;
    USE SIGNAL ;
    PORT
      LAYER M3 ;
        RECT  33.912 0 33.93 0.144 ;
    END
  END i[330]
  PIN i[331]
    DIRECTION INPUT ;
    USE SIGNAL ;
    PORT
      LAYER M5 ;
        RECT  33.984 0 34.008 0.192 ;
    END
  END i[331]
  PIN i[332]
    DIRECTION INPUT ;
    USE SIGNAL ;
    PORT
      LAYER M3 ;
        RECT  34.092 0 34.11 0.144 ;
    END
  END i[332]
  PIN i[333]
    DIRECTION INPUT ;
    USE SIGNAL ;
    PORT
      LAYER M5 ;
        RECT  34.176 0 34.2 0.192 ;
    END
  END i[333]
  PIN i[334]
    DIRECTION INPUT ;
    USE SIGNAL ;
    PORT
      LAYER M3 ;
        RECT  34.308 0 34.326 0.144 ;
    END
  END i[334]
  PIN i[335]
    DIRECTION INPUT ;
    USE SIGNAL ;
    PORT
      LAYER M5 ;
        RECT  34.368 0 34.392 0.192 ;
    END
  END i[335]
  PIN i[336]
    DIRECTION INPUT ;
    USE SIGNAL ;
    PORT
      LAYER M3 ;
        RECT  34.488 0 34.506 0.144 ;
    END
  END i[336]
  PIN i[337]
    DIRECTION INPUT ;
    USE SIGNAL ;
    PORT
      LAYER M5 ;
        RECT  34.56 0 34.584 0.192 ;
    END
  END i[337]
  PIN i[338]
    DIRECTION INPUT ;
    USE SIGNAL ;
    PORT
      LAYER M3 ;
        RECT  34.668 0 34.686 0.144 ;
    END
  END i[338]
  PIN i[339]
    DIRECTION INPUT ;
    USE SIGNAL ;
    PORT
      LAYER M5 ;
        RECT  34.752 0 34.776 0.192 ;
    END
  END i[339]
  PIN i[33]
    DIRECTION INPUT ;
    USE SIGNAL ;
    PORT
      LAYER M5 ;
        RECT  5.376 0 5.4 0.192 ;
    END
  END i[33]
  PIN i[340]
    DIRECTION INPUT ;
    USE SIGNAL ;
    PORT
      LAYER M3 ;
        RECT  34.884 0 34.902 0.144 ;
    END
  END i[340]
  PIN i[341]
    DIRECTION INPUT ;
    USE SIGNAL ;
    PORT
      LAYER M5 ;
        RECT  34.944 0 34.968 0.192 ;
    END
  END i[341]
  PIN i[342]
    DIRECTION INPUT ;
    USE SIGNAL ;
    PORT
      LAYER M3 ;
        RECT  35.064 0 35.082 0.144 ;
    END
  END i[342]
  PIN i[343]
    DIRECTION INPUT ;
    USE SIGNAL ;
    PORT
      LAYER M5 ;
        RECT  35.136 0 35.16 0.192 ;
    END
  END i[343]
  PIN i[344]
    DIRECTION INPUT ;
    USE SIGNAL ;
    PORT
      LAYER M3 ;
        RECT  35.244 0 35.262 0.144 ;
    END
  END i[344]
  PIN i[345]
    DIRECTION INPUT ;
    USE SIGNAL ;
    PORT
      LAYER M5 ;
        RECT  35.328 0 35.352 0.192 ;
    END
  END i[345]
  PIN i[346]
    DIRECTION INPUT ;
    USE SIGNAL ;
    PORT
      LAYER M3 ;
        RECT  35.46 0 35.478 0.144 ;
    END
  END i[346]
  PIN i[347]
    DIRECTION INPUT ;
    USE SIGNAL ;
    PORT
      LAYER M5 ;
        RECT  35.52 0 35.544 0.192 ;
    END
  END i[347]
  PIN i[348]
    DIRECTION INPUT ;
    USE SIGNAL ;
    PORT
      LAYER M3 ;
        RECT  35.64 0 35.658 0.144 ;
    END
  END i[348]
  PIN i[349]
    DIRECTION INPUT ;
    USE SIGNAL ;
    PORT
      LAYER M5 ;
        RECT  35.712 0 35.736 0.192 ;
    END
  END i[349]
  PIN i[34]
    DIRECTION INPUT ;
    USE SIGNAL ;
    PORT
      LAYER M3 ;
        RECT  5.472 0 5.49 0.144 ;
    END
  END i[34]
  PIN i[350]
    DIRECTION INPUT ;
    USE SIGNAL ;
    PORT
      LAYER M3 ;
        RECT  35.82 0 35.838 0.144 ;
    END
  END i[350]
  PIN i[351]
    DIRECTION INPUT ;
    USE SIGNAL ;
    PORT
      LAYER M5 ;
        RECT  35.904 0 35.928 0.192 ;
    END
  END i[351]
  PIN i[352]
    DIRECTION INPUT ;
    USE SIGNAL ;
    PORT
      LAYER M3 ;
        RECT  36.036 0 36.054 0.144 ;
    END
  END i[352]
  PIN i[353]
    DIRECTION INPUT ;
    USE SIGNAL ;
    PORT
      LAYER M5 ;
        RECT  36.096 0 36.12 0.192 ;
    END
  END i[353]
  PIN i[354]
    DIRECTION INPUT ;
    USE SIGNAL ;
    PORT
      LAYER M3 ;
        RECT  36.216 0 36.234 0.144 ;
    END
  END i[354]
  PIN i[355]
    DIRECTION INPUT ;
    USE SIGNAL ;
    PORT
      LAYER M5 ;
        RECT  36.288 0 36.312 0.192 ;
    END
  END i[355]
  PIN i[356]
    DIRECTION INPUT ;
    USE SIGNAL ;
    PORT
      LAYER M3 ;
        RECT  36.396 0 36.414 0.144 ;
    END
  END i[356]
  PIN i[357]
    DIRECTION INPUT ;
    USE SIGNAL ;
    PORT
      LAYER M5 ;
        RECT  36.48 0 36.504 0.192 ;
    END
  END i[357]
  PIN i[358]
    DIRECTION INPUT ;
    USE SIGNAL ;
    PORT
      LAYER M3 ;
        RECT  36.612 0 36.63 0.144 ;
    END
  END i[358]
  PIN i[359]
    DIRECTION INPUT ;
    USE SIGNAL ;
    PORT
      LAYER M5 ;
        RECT  36.672 0 36.696 0.192 ;
    END
  END i[359]
  PIN i[35]
    DIRECTION INPUT ;
    USE SIGNAL ;
    PORT
      LAYER M5 ;
        RECT  5.568 0 5.592 0.192 ;
    END
  END i[35]
  PIN i[360]
    DIRECTION INPUT ;
    USE SIGNAL ;
    PORT
      LAYER M3 ;
        RECT  36.792 0 36.81 0.144 ;
    END
  END i[360]
  PIN i[361]
    DIRECTION INPUT ;
    USE SIGNAL ;
    PORT
      LAYER M5 ;
        RECT  36.864 0 36.888 0.192 ;
    END
  END i[361]
  PIN i[362]
    DIRECTION INPUT ;
    USE SIGNAL ;
    PORT
      LAYER M3 ;
        RECT  36.972 0 36.99 0.144 ;
    END
  END i[362]
  PIN i[363]
    DIRECTION INPUT ;
    USE SIGNAL ;
    PORT
      LAYER M5 ;
        RECT  37.056 0 37.08 0.192 ;
    END
  END i[363]
  PIN i[364]
    DIRECTION INPUT ;
    USE SIGNAL ;
    PORT
      LAYER M3 ;
        RECT  37.188 0 37.206 0.144 ;
    END
  END i[364]
  PIN i[365]
    DIRECTION INPUT ;
    USE SIGNAL ;
    PORT
      LAYER M5 ;
        RECT  37.248 0 37.272 0.192 ;
    END
  END i[365]
  PIN i[366]
    DIRECTION INPUT ;
    USE SIGNAL ;
    PORT
      LAYER M3 ;
        RECT  37.368 0 37.386 0.144 ;
    END
  END i[366]
  PIN i[367]
    DIRECTION INPUT ;
    USE SIGNAL ;
    PORT
      LAYER M5 ;
        RECT  37.44 0 37.464 0.192 ;
    END
  END i[367]
  PIN i[368]
    DIRECTION INPUT ;
    USE SIGNAL ;
    PORT
      LAYER M3 ;
        RECT  37.548 0 37.566 0.144 ;
    END
  END i[368]
  PIN i[369]
    DIRECTION INPUT ;
    USE SIGNAL ;
    PORT
      LAYER M5 ;
        RECT  37.632 0 37.656 0.192 ;
    END
  END i[369]
  PIN i[36]
    DIRECTION INPUT ;
    USE SIGNAL ;
    PORT
      LAYER M3 ;
        RECT  5.652 0 5.67 0.144 ;
    END
  END i[36]
  PIN i[370]
    DIRECTION INPUT ;
    USE SIGNAL ;
    PORT
      LAYER M3 ;
        RECT  37.764 0 37.782 0.144 ;
    END
  END i[370]
  PIN i[371]
    DIRECTION INPUT ;
    USE SIGNAL ;
    PORT
      LAYER M5 ;
        RECT  37.824 0 37.848 0.192 ;
    END
  END i[371]
  PIN i[372]
    DIRECTION INPUT ;
    USE SIGNAL ;
    PORT
      LAYER M3 ;
        RECT  37.944 0 37.962 0.144 ;
    END
  END i[372]
  PIN i[373]
    DIRECTION INPUT ;
    USE SIGNAL ;
    PORT
      LAYER M5 ;
        RECT  38.016 0 38.04 0.192 ;
    END
  END i[373]
  PIN i[374]
    DIRECTION INPUT ;
    USE SIGNAL ;
    PORT
      LAYER M3 ;
        RECT  38.124 0 38.142 0.144 ;
    END
  END i[374]
  PIN i[375]
    DIRECTION INPUT ;
    USE SIGNAL ;
    PORT
      LAYER M5 ;
        RECT  38.208 0 38.232 0.192 ;
    END
  END i[375]
  PIN i[376]
    DIRECTION INPUT ;
    USE SIGNAL ;
    PORT
      LAYER M3 ;
        RECT  38.34 0 38.358 0.144 ;
    END
  END i[376]
  PIN i[377]
    DIRECTION INPUT ;
    USE SIGNAL ;
    PORT
      LAYER M5 ;
        RECT  38.4 0 38.424 0.192 ;
    END
  END i[377]
  PIN i[378]
    DIRECTION INPUT ;
    USE SIGNAL ;
    PORT
      LAYER M3 ;
        RECT  38.52 0 38.538 0.144 ;
    END
  END i[378]
  PIN i[379]
    DIRECTION INPUT ;
    USE SIGNAL ;
    PORT
      LAYER M5 ;
        RECT  38.592 0 38.616 0.192 ;
    END
  END i[379]
  PIN i[37]
    DIRECTION INPUT ;
    USE SIGNAL ;
    PORT
      LAYER M5 ;
        RECT  5.76 0 5.784 0.192 ;
    END
  END i[37]
  PIN i[380]
    DIRECTION INPUT ;
    USE SIGNAL ;
    PORT
      LAYER M3 ;
        RECT  38.7 0 38.718 0.144 ;
    END
  END i[380]
  PIN i[381]
    DIRECTION INPUT ;
    USE SIGNAL ;
    PORT
      LAYER M5 ;
        RECT  38.784 0 38.808 0.192 ;
    END
  END i[381]
  PIN i[382]
    DIRECTION INPUT ;
    USE SIGNAL ;
    PORT
      LAYER M3 ;
        RECT  38.916 0 38.934 0.144 ;
    END
  END i[382]
  PIN i[383]
    DIRECTION INPUT ;
    USE SIGNAL ;
    PORT
      LAYER M5 ;
        RECT  38.976 0 39 0.192 ;
    END
  END i[383]
  PIN i[384]
    DIRECTION INPUT ;
    USE SIGNAL ;
    PORT
      LAYER M3 ;
        RECT  39.096 0 39.114 0.144 ;
    END
  END i[384]
  PIN i[385]
    DIRECTION INPUT ;
    USE SIGNAL ;
    PORT
      LAYER M5 ;
        RECT  39.168 0 39.192 0.192 ;
    END
  END i[385]
  PIN i[386]
    DIRECTION INPUT ;
    USE SIGNAL ;
    PORT
      LAYER M3 ;
        RECT  39.276 0 39.294 0.144 ;
    END
  END i[386]
  PIN i[387]
    DIRECTION INPUT ;
    USE SIGNAL ;
    PORT
      LAYER M5 ;
        RECT  39.36 0 39.384 0.192 ;
    END
  END i[387]
  PIN i[388]
    DIRECTION INPUT ;
    USE SIGNAL ;
    PORT
      LAYER M3 ;
        RECT  39.492 0 39.51 0.144 ;
    END
  END i[388]
  PIN i[389]
    DIRECTION INPUT ;
    USE SIGNAL ;
    PORT
      LAYER M5 ;
        RECT  39.552 0 39.576 0.192 ;
    END
  END i[389]
  PIN i[38]
    DIRECTION INPUT ;
    USE SIGNAL ;
    PORT
      LAYER M3 ;
        RECT  5.868 0 5.886 0.144 ;
    END
  END i[38]
  PIN i[390]
    DIRECTION INPUT ;
    USE SIGNAL ;
    PORT
      LAYER M3 ;
        RECT  39.672 0 39.69 0.144 ;
    END
  END i[390]
  PIN i[391]
    DIRECTION INPUT ;
    USE SIGNAL ;
    PORT
      LAYER M5 ;
        RECT  39.744 0 39.768 0.192 ;
    END
  END i[391]
  PIN i[392]
    DIRECTION INPUT ;
    USE SIGNAL ;
    PORT
      LAYER M3 ;
        RECT  39.852 0 39.87 0.144 ;
    END
  END i[392]
  PIN i[393]
    DIRECTION INPUT ;
    USE SIGNAL ;
    PORT
      LAYER M5 ;
        RECT  39.936 0 39.96 0.192 ;
    END
  END i[393]
  PIN i[394]
    DIRECTION INPUT ;
    USE SIGNAL ;
    PORT
      LAYER M3 ;
        RECT  40.068 0 40.086 0.144 ;
    END
  END i[394]
  PIN i[395]
    DIRECTION INPUT ;
    USE SIGNAL ;
    PORT
      LAYER M5 ;
        RECT  40.128 0 40.152 0.192 ;
    END
  END i[395]
  PIN i[396]
    DIRECTION INPUT ;
    USE SIGNAL ;
    PORT
      LAYER M3 ;
        RECT  40.248 0 40.266 0.144 ;
    END
  END i[396]
  PIN i[397]
    DIRECTION INPUT ;
    USE SIGNAL ;
    PORT
      LAYER M5 ;
        RECT  40.32 0 40.344 0.192 ;
    END
  END i[397]
  PIN i[398]
    DIRECTION INPUT ;
    USE SIGNAL ;
    PORT
      LAYER M3 ;
        RECT  40.428 0 40.446 0.144 ;
    END
  END i[398]
  PIN i[399]
    DIRECTION INPUT ;
    USE SIGNAL ;
    PORT
      LAYER M5 ;
        RECT  40.512 0 40.536 0.192 ;
    END
  END i[399]
  PIN i[39]
    DIRECTION INPUT ;
    USE SIGNAL ;
    PORT
      LAYER M5 ;
        RECT  5.952 0 5.976 0.192 ;
    END
  END i[39]
  PIN i[3]
    DIRECTION INPUT ;
    USE SIGNAL ;
    PORT
      LAYER M5 ;
        RECT  2.496 0 2.52 0.192 ;
    END
  END i[3]
  PIN i[400]
    DIRECTION INPUT ;
    USE SIGNAL ;
    PORT
      LAYER M3 ;
        RECT  40.644 0 40.662 0.144 ;
    END
  END i[400]
  PIN i[401]
    DIRECTION INPUT ;
    USE SIGNAL ;
    PORT
      LAYER M5 ;
        RECT  40.704 0 40.728 0.192 ;
    END
  END i[401]
  PIN i[402]
    DIRECTION INPUT ;
    USE SIGNAL ;
    PORT
      LAYER M3 ;
        RECT  40.824 0 40.842 0.144 ;
    END
  END i[402]
  PIN i[403]
    DIRECTION INPUT ;
    USE SIGNAL ;
    PORT
      LAYER M5 ;
        RECT  40.896 0 40.92 0.192 ;
    END
  END i[403]
  PIN i[404]
    DIRECTION INPUT ;
    USE SIGNAL ;
    PORT
      LAYER M3 ;
        RECT  41.004 0 41.022 0.144 ;
    END
  END i[404]
  PIN i[405]
    DIRECTION INPUT ;
    USE SIGNAL ;
    PORT
      LAYER M5 ;
        RECT  41.088 0 41.112 0.192 ;
    END
  END i[405]
  PIN i[406]
    DIRECTION INPUT ;
    USE SIGNAL ;
    PORT
      LAYER M3 ;
        RECT  41.22 0 41.238 0.144 ;
    END
  END i[406]
  PIN i[407]
    DIRECTION INPUT ;
    USE SIGNAL ;
    PORT
      LAYER M5 ;
        RECT  41.28 0 41.304 0.192 ;
    END
  END i[407]
  PIN i[408]
    DIRECTION INPUT ;
    USE SIGNAL ;
    PORT
      LAYER M3 ;
        RECT  41.4 0 41.418 0.144 ;
    END
  END i[408]
  PIN i[409]
    DIRECTION INPUT ;
    USE SIGNAL ;
    PORT
      LAYER M5 ;
        RECT  41.472 0 41.496 0.192 ;
    END
  END i[409]
  PIN i[40]
    DIRECTION INPUT ;
    USE SIGNAL ;
    PORT
      LAYER M3 ;
        RECT  6.048 0 6.066 0.144 ;
    END
  END i[40]
  PIN i[410]
    DIRECTION INPUT ;
    USE SIGNAL ;
    PORT
      LAYER M3 ;
        RECT  41.58 0 41.598 0.144 ;
    END
  END i[410]
  PIN i[411]
    DIRECTION INPUT ;
    USE SIGNAL ;
    PORT
      LAYER M5 ;
        RECT  41.664 0 41.688 0.192 ;
    END
  END i[411]
  PIN i[412]
    DIRECTION INPUT ;
    USE SIGNAL ;
    PORT
      LAYER M3 ;
        RECT  41.796 0 41.814 0.144 ;
    END
  END i[412]
  PIN i[413]
    DIRECTION INPUT ;
    USE SIGNAL ;
    PORT
      LAYER M5 ;
        RECT  41.856 0 41.88 0.192 ;
    END
  END i[413]
  PIN i[414]
    DIRECTION INPUT ;
    USE SIGNAL ;
    PORT
      LAYER M3 ;
        RECT  41.976 0 41.994 0.144 ;
    END
  END i[414]
  PIN i[415]
    DIRECTION INPUT ;
    USE SIGNAL ;
    PORT
      LAYER M5 ;
        RECT  42.048 0 42.072 0.192 ;
    END
  END i[415]
  PIN i[416]
    DIRECTION INPUT ;
    USE SIGNAL ;
    PORT
      LAYER M3 ;
        RECT  42.156 0 42.174 0.144 ;
    END
  END i[416]
  PIN i[417]
    DIRECTION INPUT ;
    USE SIGNAL ;
    PORT
      LAYER M5 ;
        RECT  42.24 0 42.264 0.192 ;
    END
  END i[417]
  PIN i[418]
    DIRECTION INPUT ;
    USE SIGNAL ;
    PORT
      LAYER M3 ;
        RECT  42.372 0 42.39 0.144 ;
    END
  END i[418]
  PIN i[419]
    DIRECTION INPUT ;
    USE SIGNAL ;
    PORT
      LAYER M5 ;
        RECT  42.432 0 42.456 0.192 ;
    END
  END i[419]
  PIN i[41]
    DIRECTION INPUT ;
    USE SIGNAL ;
    PORT
      LAYER M5 ;
        RECT  6.144 0 6.168 0.192 ;
    END
  END i[41]
  PIN i[420]
    DIRECTION INPUT ;
    USE SIGNAL ;
    PORT
      LAYER M3 ;
        RECT  42.552 0 42.57 0.144 ;
    END
  END i[420]
  PIN i[421]
    DIRECTION INPUT ;
    USE SIGNAL ;
    PORT
      LAYER M5 ;
        RECT  42.624 0 42.648 0.192 ;
    END
  END i[421]
  PIN i[422]
    DIRECTION INPUT ;
    USE SIGNAL ;
    PORT
      LAYER M3 ;
        RECT  42.732 0 42.75 0.144 ;
    END
  END i[422]
  PIN i[423]
    DIRECTION INPUT ;
    USE SIGNAL ;
    PORT
      LAYER M5 ;
        RECT  42.864 0 42.888 0.192 ;
    END
  END i[423]
  PIN i[424]
    DIRECTION INPUT ;
    USE SIGNAL ;
    PORT
      LAYER M3 ;
        RECT  42.948 0 42.966 0.144 ;
    END
  END i[424]
  PIN i[425]
    DIRECTION INPUT ;
    USE SIGNAL ;
    PORT
      LAYER M5 ;
        RECT  43.056 0 43.08 0.192 ;
    END
  END i[425]
  PIN i[426]
    DIRECTION INPUT ;
    USE SIGNAL ;
    PORT
      LAYER M3 ;
        RECT  43.128 0 43.146 0.144 ;
    END
  END i[426]
  PIN i[427]
    DIRECTION INPUT ;
    USE SIGNAL ;
    PORT
      LAYER M5 ;
        RECT  43.248 0 43.272 0.192 ;
    END
  END i[427]
  PIN i[428]
    DIRECTION INPUT ;
    USE SIGNAL ;
    PORT
      LAYER M3 ;
        RECT  43.308 0 43.326 0.144 ;
    END
  END i[428]
  PIN i[429]
    DIRECTION INPUT ;
    USE SIGNAL ;
    PORT
      LAYER M5 ;
        RECT  43.44 0 43.464 0.192 ;
    END
  END i[429]
  PIN i[42]
    DIRECTION INPUT ;
    USE SIGNAL ;
    PORT
      LAYER M3 ;
        RECT  6.228 0 6.246 0.144 ;
    END
  END i[42]
  PIN i[430]
    DIRECTION INPUT ;
    USE SIGNAL ;
    PORT
      LAYER M3 ;
        RECT  43.524 0 43.542 0.144 ;
    END
  END i[430]
  PIN i[431]
    DIRECTION INPUT ;
    USE SIGNAL ;
    PORT
      LAYER M5 ;
        RECT  43.632 0 43.656 0.192 ;
    END
  END i[431]
  PIN i[432]
    DIRECTION INPUT ;
    USE SIGNAL ;
    PORT
      LAYER M3 ;
        RECT  43.704 0 43.722 0.144 ;
    END
  END i[432]
  PIN i[433]
    DIRECTION INPUT ;
    USE SIGNAL ;
    PORT
      LAYER M5 ;
        RECT  43.824 0 43.848 0.192 ;
    END
  END i[433]
  PIN i[434]
    DIRECTION INPUT ;
    USE SIGNAL ;
    PORT
      LAYER M3 ;
        RECT  43.884 0 43.902 0.144 ;
    END
  END i[434]
  PIN i[435]
    DIRECTION INPUT ;
    USE SIGNAL ;
    PORT
      LAYER M5 ;
        RECT  44.016 0 44.04 0.192 ;
    END
  END i[435]
  PIN i[436]
    DIRECTION INPUT ;
    USE SIGNAL ;
    PORT
      LAYER M3 ;
        RECT  44.1 0 44.118 0.144 ;
    END
  END i[436]
  PIN i[437]
    DIRECTION INPUT ;
    USE SIGNAL ;
    PORT
      LAYER M5 ;
        RECT  44.208 0 44.232 0.192 ;
    END
  END i[437]
  PIN i[438]
    DIRECTION INPUT ;
    USE SIGNAL ;
    PORT
      LAYER M3 ;
        RECT  44.28 0 44.298 0.144 ;
    END
  END i[438]
  PIN i[439]
    DIRECTION INPUT ;
    USE SIGNAL ;
    PORT
      LAYER M5 ;
        RECT  44.4 0 44.424 0.192 ;
    END
  END i[439]
  PIN i[43]
    DIRECTION INPUT ;
    USE SIGNAL ;
    PORT
      LAYER M5 ;
        RECT  6.336 0 6.36 0.192 ;
    END
  END i[43]
  PIN i[440]
    DIRECTION INPUT ;
    USE SIGNAL ;
    PORT
      LAYER M3 ;
        RECT  44.46 0 44.478 0.144 ;
    END
  END i[440]
  PIN i[441]
    DIRECTION INPUT ;
    USE SIGNAL ;
    PORT
      LAYER M5 ;
        RECT  44.592 0 44.616 0.192 ;
    END
  END i[441]
  PIN i[442]
    DIRECTION INPUT ;
    USE SIGNAL ;
    PORT
      LAYER M3 ;
        RECT  44.676 0 44.694 0.144 ;
    END
  END i[442]
  PIN i[443]
    DIRECTION INPUT ;
    USE SIGNAL ;
    PORT
      LAYER M5 ;
        RECT  44.784 0 44.808 0.192 ;
    END
  END i[443]
  PIN i[444]
    DIRECTION INPUT ;
    USE SIGNAL ;
    PORT
      LAYER M3 ;
        RECT  44.856 0 44.874 0.144 ;
    END
  END i[444]
  PIN i[445]
    DIRECTION INPUT ;
    USE SIGNAL ;
    PORT
      LAYER M5 ;
        RECT  44.976 0 45 0.192 ;
    END
  END i[445]
  PIN i[446]
    DIRECTION INPUT ;
    USE SIGNAL ;
    PORT
      LAYER M3 ;
        RECT  45.036 0 45.054 0.144 ;
    END
  END i[446]
  PIN i[447]
    DIRECTION INPUT ;
    USE SIGNAL ;
    PORT
      LAYER M5 ;
        RECT  45.168 0 45.192 0.192 ;
    END
  END i[447]
  PIN i[448]
    DIRECTION INPUT ;
    USE SIGNAL ;
    PORT
      LAYER M3 ;
        RECT  45.252 0 45.27 0.144 ;
    END
  END i[448]
  PIN i[449]
    DIRECTION INPUT ;
    USE SIGNAL ;
    PORT
      LAYER M5 ;
        RECT  45.36 0 45.384 0.192 ;
    END
  END i[449]
  PIN i[44]
    DIRECTION INPUT ;
    USE SIGNAL ;
    PORT
      LAYER M3 ;
        RECT  6.444 0 6.462 0.144 ;
    END
  END i[44]
  PIN i[450]
    DIRECTION INPUT ;
    USE SIGNAL ;
    PORT
      LAYER M3 ;
        RECT  45.432 0 45.45 0.144 ;
    END
  END i[450]
  PIN i[451]
    DIRECTION INPUT ;
    USE SIGNAL ;
    PORT
      LAYER M5 ;
        RECT  45.552 0 45.576 0.192 ;
    END
  END i[451]
  PIN i[452]
    DIRECTION INPUT ;
    USE SIGNAL ;
    PORT
      LAYER M3 ;
        RECT  45.612 0 45.63 0.144 ;
    END
  END i[452]
  PIN i[453]
    DIRECTION INPUT ;
    USE SIGNAL ;
    PORT
      LAYER M5 ;
        RECT  45.744 0 45.768 0.192 ;
    END
  END i[453]
  PIN i[454]
    DIRECTION INPUT ;
    USE SIGNAL ;
    PORT
      LAYER M3 ;
        RECT  45.828 0 45.846 0.144 ;
    END
  END i[454]
  PIN i[455]
    DIRECTION INPUT ;
    USE SIGNAL ;
    PORT
      LAYER M5 ;
        RECT  45.936 0 45.96 0.192 ;
    END
  END i[455]
  PIN i[456]
    DIRECTION INPUT ;
    USE SIGNAL ;
    PORT
      LAYER M3 ;
        RECT  46.008 0 46.026 0.144 ;
    END
  END i[456]
  PIN i[457]
    DIRECTION INPUT ;
    USE SIGNAL ;
    PORT
      LAYER M5 ;
        RECT  46.128 0 46.152 0.192 ;
    END
  END i[457]
  PIN i[458]
    DIRECTION INPUT ;
    USE SIGNAL ;
    PORT
      LAYER M3 ;
        RECT  46.224 0 46.242 0.144 ;
    END
  END i[458]
  PIN i[459]
    DIRECTION INPUT ;
    USE SIGNAL ;
    PORT
      LAYER M5 ;
        RECT  46.32 0 46.344 0.192 ;
    END
  END i[459]
  PIN i[45]
    DIRECTION INPUT ;
    USE SIGNAL ;
    PORT
      LAYER M5 ;
        RECT  6.528 0 6.552 0.192 ;
    END
  END i[45]
  PIN i[460]
    DIRECTION INPUT ;
    USE SIGNAL ;
    PORT
      LAYER M3 ;
        RECT  46.404 0 46.422 0.144 ;
    END
  END i[460]
  PIN i[461]
    DIRECTION INPUT ;
    USE SIGNAL ;
    PORT
      LAYER M5 ;
        RECT  46.512 0 46.536 0.192 ;
    END
  END i[461]
  PIN i[462]
    DIRECTION INPUT ;
    USE SIGNAL ;
    PORT
      LAYER M3 ;
        RECT  46.584 0 46.602 0.144 ;
    END
  END i[462]
  PIN i[463]
    DIRECTION INPUT ;
    USE SIGNAL ;
    PORT
      LAYER M5 ;
        RECT  46.704 0 46.728 0.192 ;
    END
  END i[463]
  PIN i[464]
    DIRECTION INPUT ;
    USE SIGNAL ;
    PORT
      LAYER M3 ;
        RECT  46.8 0 46.818 0.144 ;
    END
  END i[464]
  PIN i[465]
    DIRECTION INPUT ;
    USE SIGNAL ;
    PORT
      LAYER M5 ;
        RECT  46.896 0 46.92 0.192 ;
    END
  END i[465]
  PIN i[466]
    DIRECTION INPUT ;
    USE SIGNAL ;
    PORT
      LAYER M3 ;
        RECT  46.98 0 46.998 0.144 ;
    END
  END i[466]
  PIN i[467]
    DIRECTION INPUT ;
    USE SIGNAL ;
    PORT
      LAYER M5 ;
        RECT  47.088 0 47.112 0.192 ;
    END
  END i[467]
  PIN i[468]
    DIRECTION INPUT ;
    USE SIGNAL ;
    PORT
      LAYER M3 ;
        RECT  47.16 0 47.178 0.144 ;
    END
  END i[468]
  PIN i[469]
    DIRECTION INPUT ;
    USE SIGNAL ;
    PORT
      LAYER M5 ;
        RECT  47.28 0 47.304 0.192 ;
    END
  END i[469]
  PIN i[46]
    DIRECTION INPUT ;
    USE SIGNAL ;
    PORT
      LAYER M3 ;
        RECT  6.624 0 6.642 0.144 ;
    END
  END i[46]
  PIN i[470]
    DIRECTION INPUT ;
    USE SIGNAL ;
    PORT
      LAYER M3 ;
        RECT  47.376 0 47.394 0.144 ;
    END
  END i[470]
  PIN i[471]
    DIRECTION INPUT ;
    USE SIGNAL ;
    PORT
      LAYER M5 ;
        RECT  47.472 0 47.496 0.192 ;
    END
  END i[471]
  PIN i[472]
    DIRECTION INPUT ;
    USE SIGNAL ;
    PORT
      LAYER M3 ;
        RECT  47.556 0 47.574 0.144 ;
    END
  END i[472]
  PIN i[473]
    DIRECTION INPUT ;
    USE SIGNAL ;
    PORT
      LAYER M5 ;
        RECT  47.664 0 47.688 0.192 ;
    END
  END i[473]
  PIN i[474]
    DIRECTION INPUT ;
    USE SIGNAL ;
    PORT
      LAYER M3 ;
        RECT  47.736 0 47.754 0.144 ;
    END
  END i[474]
  PIN i[475]
    DIRECTION INPUT ;
    USE SIGNAL ;
    PORT
      LAYER M5 ;
        RECT  47.856 0 47.88 0.192 ;
    END
  END i[475]
  PIN i[476]
    DIRECTION INPUT ;
    USE SIGNAL ;
    PORT
      LAYER M3 ;
        RECT  47.952 0 47.97 0.144 ;
    END
  END i[476]
  PIN i[477]
    DIRECTION INPUT ;
    USE SIGNAL ;
    PORT
      LAYER M5 ;
        RECT  48.048 0 48.072 0.192 ;
    END
  END i[477]
  PIN i[478]
    DIRECTION INPUT ;
    USE SIGNAL ;
    PORT
      LAYER M3 ;
        RECT  48.132 0 48.15 0.144 ;
    END
  END i[478]
  PIN i[479]
    DIRECTION INPUT ;
    USE SIGNAL ;
    PORT
      LAYER M5 ;
        RECT  48.24 0 48.264 0.192 ;
    END
  END i[479]
  PIN i[47]
    DIRECTION INPUT ;
    USE SIGNAL ;
    PORT
      LAYER M5 ;
        RECT  6.72 0 6.744 0.192 ;
    END
  END i[47]
  PIN i[480]
    DIRECTION INPUT ;
    USE SIGNAL ;
    PORT
      LAYER M3 ;
        RECT  48.312 0 48.33 0.144 ;
    END
  END i[480]
  PIN i[481]
    DIRECTION INPUT ;
    USE SIGNAL ;
    PORT
      LAYER M5 ;
        RECT  48.432 0 48.456 0.192 ;
    END
  END i[481]
  PIN i[482]
    DIRECTION INPUT ;
    USE SIGNAL ;
    PORT
      LAYER M3 ;
        RECT  48.528 0 48.546 0.144 ;
    END
  END i[482]
  PIN i[483]
    DIRECTION INPUT ;
    USE SIGNAL ;
    PORT
      LAYER M5 ;
        RECT  48.624 0 48.648 0.192 ;
    END
  END i[483]
  PIN i[484]
    DIRECTION INPUT ;
    USE SIGNAL ;
    PORT
      LAYER M3 ;
        RECT  48.708 0 48.726 0.144 ;
    END
  END i[484]
  PIN i[485]
    DIRECTION INPUT ;
    USE SIGNAL ;
    PORT
      LAYER M5 ;
        RECT  48.816 0 48.84 0.192 ;
    END
  END i[485]
  PIN i[486]
    DIRECTION INPUT ;
    USE SIGNAL ;
    PORT
      LAYER M3 ;
        RECT  48.888 0 48.906 0.144 ;
    END
  END i[486]
  PIN i[487]
    DIRECTION INPUT ;
    USE SIGNAL ;
    PORT
      LAYER M5 ;
        RECT  49.008 0 49.032 0.192 ;
    END
  END i[487]
  PIN i[488]
    DIRECTION INPUT ;
    USE SIGNAL ;
    PORT
      LAYER M3 ;
        RECT  49.104 0 49.122 0.144 ;
    END
  END i[488]
  PIN i[489]
    DIRECTION INPUT ;
    USE SIGNAL ;
    PORT
      LAYER M5 ;
        RECT  49.2 0 49.224 0.192 ;
    END
  END i[489]
  PIN i[48]
    DIRECTION INPUT ;
    USE SIGNAL ;
    PORT
      LAYER M3 ;
        RECT  6.804 0 6.822 0.144 ;
    END
  END i[48]
  PIN i[490]
    DIRECTION INPUT ;
    USE SIGNAL ;
    PORT
      LAYER M3 ;
        RECT  49.284 0 49.302 0.144 ;
    END
  END i[490]
  PIN i[491]
    DIRECTION INPUT ;
    USE SIGNAL ;
    PORT
      LAYER M5 ;
        RECT  49.392 0 49.416 0.192 ;
    END
  END i[491]
  PIN i[492]
    DIRECTION INPUT ;
    USE SIGNAL ;
    PORT
      LAYER M3 ;
        RECT  49.464 0 49.482 0.144 ;
    END
  END i[492]
  PIN i[493]
    DIRECTION INPUT ;
    USE SIGNAL ;
    PORT
      LAYER M5 ;
        RECT  49.584 0 49.608 0.192 ;
    END
  END i[493]
  PIN i[494]
    DIRECTION INPUT ;
    USE SIGNAL ;
    PORT
      LAYER M3 ;
        RECT  49.68 0 49.698 0.144 ;
    END
  END i[494]
  PIN i[495]
    DIRECTION INPUT ;
    USE SIGNAL ;
    PORT
      LAYER M5 ;
        RECT  49.776 0 49.8 0.192 ;
    END
  END i[495]
  PIN i[496]
    DIRECTION INPUT ;
    USE SIGNAL ;
    PORT
      LAYER M3 ;
        RECT  49.86 0 49.878 0.144 ;
    END
  END i[496]
  PIN i[497]
    DIRECTION INPUT ;
    USE SIGNAL ;
    PORT
      LAYER M5 ;
        RECT  49.968 0 49.992 0.192 ;
    END
  END i[497]
  PIN i[498]
    DIRECTION INPUT ;
    USE SIGNAL ;
    PORT
      LAYER M3 ;
        RECT  50.04 0 50.058 0.144 ;
    END
  END i[498]
  PIN i[499]
    DIRECTION INPUT ;
    USE SIGNAL ;
    PORT
      LAYER M5 ;
        RECT  50.16 0 50.184 0.192 ;
    END
  END i[499]
  PIN i[49]
    DIRECTION INPUT ;
    USE SIGNAL ;
    PORT
      LAYER M5 ;
        RECT  6.912 0 6.936 0.192 ;
    END
  END i[49]
  PIN i[4]
    DIRECTION INPUT ;
    USE SIGNAL ;
    PORT
      LAYER M3 ;
        RECT  2.592 0 2.61 0.144 ;
    END
  END i[4]
  PIN i[500]
    DIRECTION INPUT ;
    USE SIGNAL ;
    PORT
      LAYER M3 ;
        RECT  50.256 0 50.274 0.144 ;
    END
  END i[500]
  PIN i[501]
    DIRECTION INPUT ;
    USE SIGNAL ;
    PORT
      LAYER M5 ;
        RECT  50.352 0 50.376 0.192 ;
    END
  END i[501]
  PIN i[502]
    DIRECTION INPUT ;
    USE SIGNAL ;
    PORT
      LAYER M3 ;
        RECT  50.436 0 50.454 0.144 ;
    END
  END i[502]
  PIN i[503]
    DIRECTION INPUT ;
    USE SIGNAL ;
    PORT
      LAYER M5 ;
        RECT  50.544 0 50.568 0.192 ;
    END
  END i[503]
  PIN i[504]
    DIRECTION INPUT ;
    USE SIGNAL ;
    PORT
      LAYER M3 ;
        RECT  50.616 0 50.634 0.144 ;
    END
  END i[504]
  PIN i[505]
    DIRECTION INPUT ;
    USE SIGNAL ;
    PORT
      LAYER M5 ;
        RECT  50.736 0 50.76 0.192 ;
    END
  END i[505]
  PIN i[506]
    DIRECTION INPUT ;
    USE SIGNAL ;
    PORT
      LAYER M3 ;
        RECT  50.832 0 50.85 0.144 ;
    END
  END i[506]
  PIN i[507]
    DIRECTION INPUT ;
    USE SIGNAL ;
    PORT
      LAYER M5 ;
        RECT  50.928 0 50.952 0.192 ;
    END
  END i[507]
  PIN i[508]
    DIRECTION INPUT ;
    USE SIGNAL ;
    PORT
      LAYER M3 ;
        RECT  51.012 0 51.03 0.144 ;
    END
  END i[508]
  PIN i[509]
    DIRECTION INPUT ;
    USE SIGNAL ;
    PORT
      LAYER M5 ;
        RECT  51.12 0 51.144 0.192 ;
    END
  END i[509]
  PIN i[50]
    DIRECTION INPUT ;
    USE SIGNAL ;
    PORT
      LAYER M3 ;
        RECT  7.02 0 7.038 0.144 ;
    END
  END i[50]
  PIN i[510]
    DIRECTION INPUT ;
    USE SIGNAL ;
    PORT
      LAYER M3 ;
        RECT  51.192 0 51.21 0.144 ;
    END
  END i[510]
  PIN i[511]
    DIRECTION INPUT ;
    USE SIGNAL ;
    PORT
      LAYER M5 ;
        RECT  51.312 0 51.336 0.192 ;
    END
  END i[511]
  PIN i[512]
    DIRECTION INPUT ;
    USE SIGNAL ;
    PORT
      LAYER M3 ;
        RECT  51.408 0 51.426 0.144 ;
    END
  END i[512]
  PIN i[513]
    DIRECTION INPUT ;
    USE SIGNAL ;
    PORT
      LAYER M5 ;
        RECT  51.504 0 51.528 0.192 ;
    END
  END i[513]
  PIN i[514]
    DIRECTION INPUT ;
    USE SIGNAL ;
    PORT
      LAYER M3 ;
        RECT  51.588 0 51.606 0.144 ;
    END
  END i[514]
  PIN i[515]
    DIRECTION INPUT ;
    USE SIGNAL ;
    PORT
      LAYER M5 ;
        RECT  51.696 0 51.72 0.192 ;
    END
  END i[515]
  PIN i[516]
    DIRECTION INPUT ;
    USE SIGNAL ;
    PORT
      LAYER M3 ;
        RECT  51.768 0 51.786 0.144 ;
    END
  END i[516]
  PIN i[517]
    DIRECTION INPUT ;
    USE SIGNAL ;
    PORT
      LAYER M5 ;
        RECT  51.888 0 51.912 0.192 ;
    END
  END i[517]
  PIN i[518]
    DIRECTION INPUT ;
    USE SIGNAL ;
    PORT
      LAYER M3 ;
        RECT  51.984 0 52.002 0.144 ;
    END
  END i[518]
  PIN i[519]
    DIRECTION INPUT ;
    USE SIGNAL ;
    PORT
      LAYER M5 ;
        RECT  52.08 0 52.104 0.192 ;
    END
  END i[519]
  PIN i[51]
    DIRECTION INPUT ;
    USE SIGNAL ;
    PORT
      LAYER M5 ;
        RECT  7.104 0 7.128 0.192 ;
    END
  END i[51]
  PIN i[520]
    DIRECTION INPUT ;
    USE SIGNAL ;
    PORT
      LAYER M3 ;
        RECT  52.164 0 52.182 0.144 ;
    END
  END i[520]
  PIN i[521]
    DIRECTION INPUT ;
    USE SIGNAL ;
    PORT
      LAYER M5 ;
        RECT  52.272 0 52.296 0.192 ;
    END
  END i[521]
  PIN i[522]
    DIRECTION INPUT ;
    USE SIGNAL ;
    PORT
      LAYER M3 ;
        RECT  52.344 0 52.362 0.144 ;
    END
  END i[522]
  PIN i[523]
    DIRECTION INPUT ;
    USE SIGNAL ;
    PORT
      LAYER M5 ;
        RECT  52.464 0 52.488 0.192 ;
    END
  END i[523]
  PIN i[524]
    DIRECTION INPUT ;
    USE SIGNAL ;
    PORT
      LAYER M3 ;
        RECT  52.56 0 52.578 0.144 ;
    END
  END i[524]
  PIN i[525]
    DIRECTION INPUT ;
    USE SIGNAL ;
    PORT
      LAYER M5 ;
        RECT  52.656 0 52.68 0.192 ;
    END
  END i[525]
  PIN i[526]
    DIRECTION INPUT ;
    USE SIGNAL ;
    PORT
      LAYER M3 ;
        RECT  52.74 0 52.758 0.144 ;
    END
  END i[526]
  PIN i[527]
    DIRECTION INPUT ;
    USE SIGNAL ;
    PORT
      LAYER M5 ;
        RECT  52.848 0 52.872 0.192 ;
    END
  END i[527]
  PIN i[528]
    DIRECTION INPUT ;
    USE SIGNAL ;
    PORT
      LAYER M3 ;
        RECT  52.92 0 52.938 0.144 ;
    END
  END i[528]
  PIN i[529]
    DIRECTION INPUT ;
    USE SIGNAL ;
    PORT
      LAYER M5 ;
        RECT  53.04 0 53.064 0.192 ;
    END
  END i[529]
  PIN i[52]
    DIRECTION INPUT ;
    USE SIGNAL ;
    PORT
      LAYER M3 ;
        RECT  7.2 0 7.218 0.144 ;
    END
  END i[52]
  PIN i[530]
    DIRECTION INPUT ;
    USE SIGNAL ;
    PORT
      LAYER M3 ;
        RECT  53.136 0 53.154 0.144 ;
    END
  END i[530]
  PIN i[531]
    DIRECTION INPUT ;
    USE SIGNAL ;
    PORT
      LAYER M5 ;
        RECT  53.232 0 53.256 0.192 ;
    END
  END i[531]
  PIN i[532]
    DIRECTION INPUT ;
    USE SIGNAL ;
    PORT
      LAYER M3 ;
        RECT  53.316 0 53.334 0.144 ;
    END
  END i[532]
  PIN i[533]
    DIRECTION INPUT ;
    USE SIGNAL ;
    PORT
      LAYER M5 ;
        RECT  53.424 0 53.448 0.192 ;
    END
  END i[533]
  PIN i[534]
    DIRECTION INPUT ;
    USE SIGNAL ;
    PORT
      LAYER M3 ;
        RECT  53.496 0 53.514 0.144 ;
    END
  END i[534]
  PIN i[535]
    DIRECTION INPUT ;
    USE SIGNAL ;
    PORT
      LAYER M5 ;
        RECT  53.616 0 53.64 0.192 ;
    END
  END i[535]
  PIN i[536]
    DIRECTION INPUT ;
    USE SIGNAL ;
    PORT
      LAYER M3 ;
        RECT  53.712 0 53.73 0.144 ;
    END
  END i[536]
  PIN i[537]
    DIRECTION INPUT ;
    USE SIGNAL ;
    PORT
      LAYER M5 ;
        RECT  53.808 0 53.832 0.192 ;
    END
  END i[537]
  PIN i[538]
    DIRECTION INPUT ;
    USE SIGNAL ;
    PORT
      LAYER M3 ;
        RECT  53.892 0 53.91 0.144 ;
    END
  END i[538]
  PIN i[539]
    DIRECTION INPUT ;
    USE SIGNAL ;
    PORT
      LAYER M5 ;
        RECT  54 0 54.024 0.192 ;
    END
  END i[539]
  PIN i[53]
    DIRECTION INPUT ;
    USE SIGNAL ;
    PORT
      LAYER M5 ;
        RECT  7.296 0 7.32 0.192 ;
    END
  END i[53]
  PIN i[540]
    DIRECTION INPUT ;
    USE SIGNAL ;
    PORT
      LAYER M3 ;
        RECT  54.072 0 54.09 0.144 ;
    END
  END i[540]
  PIN i[541]
    DIRECTION INPUT ;
    USE SIGNAL ;
    PORT
      LAYER M5 ;
        RECT  54.192 0 54.216 0.192 ;
    END
  END i[541]
  PIN i[542]
    DIRECTION INPUT ;
    USE SIGNAL ;
    PORT
      LAYER M3 ;
        RECT  54.288 0 54.306 0.144 ;
    END
  END i[542]
  PIN i[543]
    DIRECTION INPUT ;
    USE SIGNAL ;
    PORT
      LAYER M5 ;
        RECT  54.384 0 54.408 0.192 ;
    END
  END i[543]
  PIN i[544]
    DIRECTION INPUT ;
    USE SIGNAL ;
    PORT
      LAYER M3 ;
        RECT  54.468 0 54.486 0.144 ;
    END
  END i[544]
  PIN i[545]
    DIRECTION INPUT ;
    USE SIGNAL ;
    PORT
      LAYER M5 ;
        RECT  54.576 0 54.6 0.192 ;
    END
  END i[545]
  PIN i[546]
    DIRECTION INPUT ;
    USE SIGNAL ;
    PORT
      LAYER M3 ;
        RECT  54.648 0 54.666 0.144 ;
    END
  END i[546]
  PIN i[547]
    DIRECTION INPUT ;
    USE SIGNAL ;
    PORT
      LAYER M5 ;
        RECT  54.768 0 54.792 0.192 ;
    END
  END i[547]
  PIN i[548]
    DIRECTION INPUT ;
    USE SIGNAL ;
    PORT
      LAYER M3 ;
        RECT  54.864 0 54.882 0.144 ;
    END
  END i[548]
  PIN i[549]
    DIRECTION INPUT ;
    USE SIGNAL ;
    PORT
      LAYER M5 ;
        RECT  54.96 0 54.984 0.192 ;
    END
  END i[549]
  PIN i[54]
    DIRECTION INPUT ;
    USE SIGNAL ;
    PORT
      LAYER M3 ;
        RECT  7.38 0 7.398 0.144 ;
    END
  END i[54]
  PIN i[550]
    DIRECTION INPUT ;
    USE SIGNAL ;
    PORT
      LAYER M3 ;
        RECT  55.044 0 55.062 0.144 ;
    END
  END i[550]
  PIN i[551]
    DIRECTION INPUT ;
    USE SIGNAL ;
    PORT
      LAYER M5 ;
        RECT  55.152 0 55.176 0.192 ;
    END
  END i[551]
  PIN i[552]
    DIRECTION INPUT ;
    USE SIGNAL ;
    PORT
      LAYER M3 ;
        RECT  55.224 0 55.242 0.144 ;
    END
  END i[552]
  PIN i[553]
    DIRECTION INPUT ;
    USE SIGNAL ;
    PORT
      LAYER M5 ;
        RECT  55.344 0 55.368 0.192 ;
    END
  END i[553]
  PIN i[554]
    DIRECTION INPUT ;
    USE SIGNAL ;
    PORT
      LAYER M3 ;
        RECT  55.44 0 55.458 0.144 ;
    END
  END i[554]
  PIN i[555]
    DIRECTION INPUT ;
    USE SIGNAL ;
    PORT
      LAYER M5 ;
        RECT  55.536 0 55.56 0.192 ;
    END
  END i[555]
  PIN i[556]
    DIRECTION INPUT ;
    USE SIGNAL ;
    PORT
      LAYER M3 ;
        RECT  55.62 0 55.638 0.144 ;
    END
  END i[556]
  PIN i[557]
    DIRECTION INPUT ;
    USE SIGNAL ;
    PORT
      LAYER M5 ;
        RECT  55.728 0 55.752 0.192 ;
    END
  END i[557]
  PIN i[558]
    DIRECTION INPUT ;
    USE SIGNAL ;
    PORT
      LAYER M3 ;
        RECT  55.8 0 55.818 0.144 ;
    END
  END i[558]
  PIN i[559]
    DIRECTION INPUT ;
    USE SIGNAL ;
    PORT
      LAYER M5 ;
        RECT  55.92 0 55.944 0.192 ;
    END
  END i[559]
  PIN i[55]
    DIRECTION INPUT ;
    USE SIGNAL ;
    PORT
      LAYER M5 ;
        RECT  7.488 0 7.512 0.192 ;
    END
  END i[55]
  PIN i[560]
    DIRECTION INPUT ;
    USE SIGNAL ;
    PORT
      LAYER M3 ;
        RECT  56.016 0 56.034 0.144 ;
    END
  END i[560]
  PIN i[561]
    DIRECTION INPUT ;
    USE SIGNAL ;
    PORT
      LAYER M5 ;
        RECT  56.112 0 56.136 0.192 ;
    END
  END i[561]
  PIN i[56]
    DIRECTION INPUT ;
    USE SIGNAL ;
    PORT
      LAYER M3 ;
        RECT  7.596 0 7.614 0.144 ;
    END
  END i[56]
  PIN i[57]
    DIRECTION INPUT ;
    USE SIGNAL ;
    PORT
      LAYER M5 ;
        RECT  7.68 0 7.704 0.192 ;
    END
  END i[57]
  PIN i[58]
    DIRECTION INPUT ;
    USE SIGNAL ;
    PORT
      LAYER M3 ;
        RECT  7.776 0 7.794 0.144 ;
    END
  END i[58]
  PIN i[59]
    DIRECTION INPUT ;
    USE SIGNAL ;
    PORT
      LAYER M5 ;
        RECT  7.872 0 7.896 0.192 ;
    END
  END i[59]
  PIN i[5]
    DIRECTION INPUT ;
    USE SIGNAL ;
    PORT
      LAYER M5 ;
        RECT  2.688 0 2.712 0.192 ;
    END
  END i[5]
  PIN i[60]
    DIRECTION INPUT ;
    USE SIGNAL ;
    PORT
      LAYER M3 ;
        RECT  7.956 0 7.974 0.144 ;
    END
  END i[60]
  PIN i[61]
    DIRECTION INPUT ;
    USE SIGNAL ;
    PORT
      LAYER M5 ;
        RECT  8.064 0 8.088 0.192 ;
    END
  END i[61]
  PIN i[62]
    DIRECTION INPUT ;
    USE SIGNAL ;
    PORT
      LAYER M3 ;
        RECT  8.172 0 8.19 0.144 ;
    END
  END i[62]
  PIN i[63]
    DIRECTION INPUT ;
    USE SIGNAL ;
    PORT
      LAYER M5 ;
        RECT  8.256 0 8.28 0.192 ;
    END
  END i[63]
  PIN i[64]
    DIRECTION INPUT ;
    USE SIGNAL ;
    PORT
      LAYER M3 ;
        RECT  8.352 0 8.37 0.144 ;
    END
  END i[64]
  PIN i[65]
    DIRECTION INPUT ;
    USE SIGNAL ;
    PORT
      LAYER M5 ;
        RECT  8.448 0 8.472 0.192 ;
    END
  END i[65]
  PIN i[66]
    DIRECTION INPUT ;
    USE SIGNAL ;
    PORT
      LAYER M3 ;
        RECT  8.532 0 8.55 0.144 ;
    END
  END i[66]
  PIN i[67]
    DIRECTION INPUT ;
    USE SIGNAL ;
    PORT
      LAYER M5 ;
        RECT  8.64 0 8.664 0.192 ;
    END
  END i[67]
  PIN i[68]
    DIRECTION INPUT ;
    USE SIGNAL ;
    PORT
      LAYER M3 ;
        RECT  8.748 0 8.766 0.144 ;
    END
  END i[68]
  PIN i[69]
    DIRECTION INPUT ;
    USE SIGNAL ;
    PORT
      LAYER M5 ;
        RECT  8.832 0 8.856 0.192 ;
    END
  END i[69]
  PIN i[6]
    DIRECTION INPUT ;
    USE SIGNAL ;
    PORT
      LAYER M3 ;
        RECT  2.772 0 2.79 0.144 ;
    END
  END i[6]
  PIN i[70]
    DIRECTION INPUT ;
    USE SIGNAL ;
    PORT
      LAYER M3 ;
        RECT  8.928 0 8.946 0.144 ;
    END
  END i[70]
  PIN i[71]
    DIRECTION INPUT ;
    USE SIGNAL ;
    PORT
      LAYER M5 ;
        RECT  9.024 0 9.048 0.192 ;
    END
  END i[71]
  PIN i[72]
    DIRECTION INPUT ;
    USE SIGNAL ;
    PORT
      LAYER M3 ;
        RECT  9.108 0 9.126 0.144 ;
    END
  END i[72]
  PIN i[73]
    DIRECTION INPUT ;
    USE SIGNAL ;
    PORT
      LAYER M5 ;
        RECT  9.216 0 9.24 0.192 ;
    END
  END i[73]
  PIN i[74]
    DIRECTION INPUT ;
    USE SIGNAL ;
    PORT
      LAYER M3 ;
        RECT  9.324 0 9.342 0.144 ;
    END
  END i[74]
  PIN i[75]
    DIRECTION INPUT ;
    USE SIGNAL ;
    PORT
      LAYER M5 ;
        RECT  9.408 0 9.432 0.192 ;
    END
  END i[75]
  PIN i[76]
    DIRECTION INPUT ;
    USE SIGNAL ;
    PORT
      LAYER M3 ;
        RECT  9.504 0 9.522 0.144 ;
    END
  END i[76]
  PIN i[77]
    DIRECTION INPUT ;
    USE SIGNAL ;
    PORT
      LAYER M5 ;
        RECT  9.6 0 9.624 0.192 ;
    END
  END i[77]
  PIN i[78]
    DIRECTION INPUT ;
    USE SIGNAL ;
    PORT
      LAYER M3 ;
        RECT  9.684 0 9.702 0.144 ;
    END
  END i[78]
  PIN i[79]
    DIRECTION INPUT ;
    USE SIGNAL ;
    PORT
      LAYER M5 ;
        RECT  9.792 0 9.816 0.192 ;
    END
  END i[79]
  PIN i[7]
    DIRECTION INPUT ;
    USE SIGNAL ;
    PORT
      LAYER M5 ;
        RECT  2.88 0 2.904 0.192 ;
    END
  END i[7]
  PIN i[80]
    DIRECTION INPUT ;
    USE SIGNAL ;
    PORT
      LAYER M3 ;
        RECT  9.9 0 9.918 0.144 ;
    END
  END i[80]
  PIN i[81]
    DIRECTION INPUT ;
    USE SIGNAL ;
    PORT
      LAYER M5 ;
        RECT  9.984 0 10.008 0.192 ;
    END
  END i[81]
  PIN i[82]
    DIRECTION INPUT ;
    USE SIGNAL ;
    PORT
      LAYER M3 ;
        RECT  10.08 0 10.098 0.144 ;
    END
  END i[82]
  PIN i[83]
    DIRECTION INPUT ;
    USE SIGNAL ;
    PORT
      LAYER M5 ;
        RECT  10.176 0 10.2 0.192 ;
    END
  END i[83]
  PIN i[84]
    DIRECTION INPUT ;
    USE SIGNAL ;
    PORT
      LAYER M3 ;
        RECT  10.26 0 10.278 0.144 ;
    END
  END i[84]
  PIN i[85]
    DIRECTION INPUT ;
    USE SIGNAL ;
    PORT
      LAYER M5 ;
        RECT  10.368 0 10.392 0.192 ;
    END
  END i[85]
  PIN i[86]
    DIRECTION INPUT ;
    USE SIGNAL ;
    PORT
      LAYER M3 ;
        RECT  10.476 0 10.494 0.144 ;
    END
  END i[86]
  PIN i[87]
    DIRECTION INPUT ;
    USE SIGNAL ;
    PORT
      LAYER M5 ;
        RECT  10.56 0 10.584 0.192 ;
    END
  END i[87]
  PIN i[88]
    DIRECTION INPUT ;
    USE SIGNAL ;
    PORT
      LAYER M3 ;
        RECT  10.656 0 10.674 0.144 ;
    END
  END i[88]
  PIN i[89]
    DIRECTION INPUT ;
    USE SIGNAL ;
    PORT
      LAYER M5 ;
        RECT  10.752 0 10.776 0.192 ;
    END
  END i[89]
  PIN i[8]
    DIRECTION INPUT ;
    USE SIGNAL ;
    PORT
      LAYER M3 ;
        RECT  2.952 0 2.97 0.144 ;
    END
  END i[8]
  PIN i[90]
    DIRECTION INPUT ;
    USE SIGNAL ;
    PORT
      LAYER M3 ;
        RECT  10.836 0 10.854 0.144 ;
    END
  END i[90]
  PIN i[91]
    DIRECTION INPUT ;
    USE SIGNAL ;
    PORT
      LAYER M5 ;
        RECT  10.944 0 10.968 0.192 ;
    END
  END i[91]
  PIN i[92]
    DIRECTION INPUT ;
    USE SIGNAL ;
    PORT
      LAYER M3 ;
        RECT  11.052 0 11.07 0.144 ;
    END
  END i[92]
  PIN i[93]
    DIRECTION INPUT ;
    USE SIGNAL ;
    PORT
      LAYER M5 ;
        RECT  11.136 0 11.16 0.192 ;
    END
  END i[93]
  PIN i[94]
    DIRECTION INPUT ;
    USE SIGNAL ;
    PORT
      LAYER M3 ;
        RECT  11.232 0 11.25 0.144 ;
    END
  END i[94]
  PIN i[95]
    DIRECTION INPUT ;
    USE SIGNAL ;
    PORT
      LAYER M5 ;
        RECT  11.328 0 11.352 0.192 ;
    END
  END i[95]
  PIN i[96]
    DIRECTION INPUT ;
    USE SIGNAL ;
    PORT
      LAYER M3 ;
        RECT  11.412 0 11.43 0.144 ;
    END
  END i[96]
  PIN i[97]
    DIRECTION INPUT ;
    USE SIGNAL ;
    PORT
      LAYER M5 ;
        RECT  11.52 0 11.544 0.192 ;
    END
  END i[97]
  PIN i[98]
    DIRECTION INPUT ;
    USE SIGNAL ;
    PORT
      LAYER M3 ;
        RECT  11.628 0 11.646 0.144 ;
    END
  END i[98]
  PIN i[99]
    DIRECTION INPUT ;
    USE SIGNAL ;
    PORT
      LAYER M5 ;
        RECT  11.712 0 11.736 0.192 ;
    END
  END i[99]
  PIN i[9]
    DIRECTION INPUT ;
    USE SIGNAL ;
    PORT
      LAYER M5 ;
        RECT  3.072 0 3.096 0.192 ;
    END
  END i[9]
  PIN o[0]
    DIRECTION OUTPUT ;
    USE SIGNAL ;
    PORT
      LAYER M3 ;
        RECT  2.196 17.136 2.214 17.28 ;
    END
  END o[0]
  PIN o[100]
    DIRECTION OUTPUT ;
    USE SIGNAL ;
    PORT
      LAYER M3 ;
        RECT  11.808 17.136 11.826 17.28 ;
    END
  END o[100]
  PIN o[101]
    DIRECTION OUTPUT ;
    USE SIGNAL ;
    PORT
      LAYER M5 ;
        RECT  11.904 17.088 11.928 17.28 ;
    END
  END o[101]
  PIN o[102]
    DIRECTION OUTPUT ;
    USE SIGNAL ;
    PORT
      LAYER M3 ;
        RECT  11.988 17.136 12.006 17.28 ;
    END
  END o[102]
  PIN o[103]
    DIRECTION OUTPUT ;
    USE SIGNAL ;
    PORT
      LAYER M5 ;
        RECT  12.096 17.088 12.12 17.28 ;
    END
  END o[103]
  PIN o[104]
    DIRECTION OUTPUT ;
    USE SIGNAL ;
    PORT
      LAYER M3 ;
        RECT  12.168 17.136 12.186 17.28 ;
    END
  END o[104]
  PIN o[105]
    DIRECTION OUTPUT ;
    USE SIGNAL ;
    PORT
      LAYER M5 ;
        RECT  12.288 17.088 12.312 17.28 ;
    END
  END o[105]
  PIN o[106]
    DIRECTION OUTPUT ;
    USE SIGNAL ;
    PORT
      LAYER M3 ;
        RECT  12.348 17.136 12.366 17.28 ;
    END
  END o[106]
  PIN o[107]
    DIRECTION OUTPUT ;
    USE SIGNAL ;
    PORT
      LAYER M5 ;
        RECT  12.48 17.088 12.504 17.28 ;
    END
  END o[107]
  PIN o[108]
    DIRECTION OUTPUT ;
    USE SIGNAL ;
    PORT
      LAYER M3 ;
        RECT  12.564 17.136 12.582 17.28 ;
    END
  END o[108]
  PIN o[109]
    DIRECTION OUTPUT ;
    USE SIGNAL ;
    PORT
      LAYER M5 ;
        RECT  12.672 17.088 12.696 17.28 ;
    END
  END o[109]
  PIN o[10]
    DIRECTION OUTPUT ;
    USE SIGNAL ;
    PORT
      LAYER M3 ;
        RECT  3.168 17.136 3.186 17.28 ;
    END
  END o[10]
  PIN o[110]
    DIRECTION OUTPUT ;
    USE SIGNAL ;
    PORT
      LAYER M3 ;
        RECT  12.744 17.136 12.762 17.28 ;
    END
  END o[110]
  PIN o[111]
    DIRECTION OUTPUT ;
    USE SIGNAL ;
    PORT
      LAYER M5 ;
        RECT  12.864 17.088 12.888 17.28 ;
    END
  END o[111]
  PIN o[112]
    DIRECTION OUTPUT ;
    USE SIGNAL ;
    PORT
      LAYER M3 ;
        RECT  12.924 17.136 12.942 17.28 ;
    END
  END o[112]
  PIN o[113]
    DIRECTION OUTPUT ;
    USE SIGNAL ;
    PORT
      LAYER M5 ;
        RECT  13.056 17.088 13.08 17.28 ;
    END
  END o[113]
  PIN o[114]
    DIRECTION OUTPUT ;
    USE SIGNAL ;
    PORT
      LAYER M3 ;
        RECT  13.14 17.136 13.158 17.28 ;
    END
  END o[114]
  PIN o[115]
    DIRECTION OUTPUT ;
    USE SIGNAL ;
    PORT
      LAYER M5 ;
        RECT  13.248 17.088 13.272 17.28 ;
    END
  END o[115]
  PIN o[116]
    DIRECTION OUTPUT ;
    USE SIGNAL ;
    PORT
      LAYER M3 ;
        RECT  13.32 17.136 13.338 17.28 ;
    END
  END o[116]
  PIN o[117]
    DIRECTION OUTPUT ;
    USE SIGNAL ;
    PORT
      LAYER M5 ;
        RECT  13.44 17.088 13.464 17.28 ;
    END
  END o[117]
  PIN o[118]
    DIRECTION OUTPUT ;
    USE SIGNAL ;
    PORT
      LAYER M3 ;
        RECT  13.5 17.136 13.518 17.28 ;
    END
  END o[118]
  PIN o[119]
    DIRECTION OUTPUT ;
    USE SIGNAL ;
    PORT
      LAYER M5 ;
        RECT  13.632 17.088 13.656 17.28 ;
    END
  END o[119]
  PIN o[11]
    DIRECTION OUTPUT ;
    USE SIGNAL ;
    PORT
      LAYER M5 ;
        RECT  3.264 17.088 3.288 17.28 ;
    END
  END o[11]
  PIN o[120]
    DIRECTION OUTPUT ;
    USE SIGNAL ;
    PORT
      LAYER M3 ;
        RECT  13.716 17.136 13.734 17.28 ;
    END
  END o[120]
  PIN o[121]
    DIRECTION OUTPUT ;
    USE SIGNAL ;
    PORT
      LAYER M5 ;
        RECT  13.824 17.088 13.848 17.28 ;
    END
  END o[121]
  PIN o[122]
    DIRECTION OUTPUT ;
    USE SIGNAL ;
    PORT
      LAYER M3 ;
        RECT  13.896 17.136 13.914 17.28 ;
    END
  END o[122]
  PIN o[123]
    DIRECTION OUTPUT ;
    USE SIGNAL ;
    PORT
      LAYER M5 ;
        RECT  14.016 17.088 14.04 17.28 ;
    END
  END o[123]
  PIN o[124]
    DIRECTION OUTPUT ;
    USE SIGNAL ;
    PORT
      LAYER M3 ;
        RECT  14.076 17.136 14.094 17.28 ;
    END
  END o[124]
  PIN o[125]
    DIRECTION OUTPUT ;
    USE SIGNAL ;
    PORT
      LAYER M5 ;
        RECT  14.208 17.088 14.232 17.28 ;
    END
  END o[125]
  PIN o[126]
    DIRECTION OUTPUT ;
    USE SIGNAL ;
    PORT
      LAYER M3 ;
        RECT  14.292 17.136 14.31 17.28 ;
    END
  END o[126]
  PIN o[127]
    DIRECTION OUTPUT ;
    USE SIGNAL ;
    PORT
      LAYER M5 ;
        RECT  14.4 17.088 14.424 17.28 ;
    END
  END o[127]
  PIN o[128]
    DIRECTION OUTPUT ;
    USE SIGNAL ;
    PORT
      LAYER M3 ;
        RECT  14.472 17.136 14.49 17.28 ;
    END
  END o[128]
  PIN o[129]
    DIRECTION OUTPUT ;
    USE SIGNAL ;
    PORT
      LAYER M5 ;
        RECT  14.592 17.088 14.616 17.28 ;
    END
  END o[129]
  PIN o[12]
    DIRECTION OUTPUT ;
    USE SIGNAL ;
    PORT
      LAYER M3 ;
        RECT  3.348 17.136 3.366 17.28 ;
    END
  END o[12]
  PIN o[130]
    DIRECTION OUTPUT ;
    USE SIGNAL ;
    PORT
      LAYER M3 ;
        RECT  14.652 17.136 14.67 17.28 ;
    END
  END o[130]
  PIN o[131]
    DIRECTION OUTPUT ;
    USE SIGNAL ;
    PORT
      LAYER M5 ;
        RECT  14.784 17.088 14.808 17.28 ;
    END
  END o[131]
  PIN o[132]
    DIRECTION OUTPUT ;
    USE SIGNAL ;
    PORT
      LAYER M3 ;
        RECT  14.868 17.136 14.886 17.28 ;
    END
    PORT
      LAYER M3 ;
        RECT  14.832 17.148 14.958 17.213 ;
    END
  END o[132]
  PIN o[133]
    DIRECTION OUTPUT ;
    USE SIGNAL ;
    PORT
      LAYER M5 ;
        RECT  14.976 17.088 15 17.28 ;
    END
  END o[133]
  PIN o[134]
    DIRECTION OUTPUT ;
    USE SIGNAL ;
    PORT
      LAYER M3 ;
        RECT  15.048 17.136 15.066 17.28 ;
    END
  END o[134]
  PIN o[135]
    DIRECTION OUTPUT ;
    USE SIGNAL ;
    PORT
      LAYER M5 ;
        RECT  15.168 17.088 15.192 17.28 ;
    END
  END o[135]
  PIN o[136]
    DIRECTION OUTPUT ;
    USE SIGNAL ;
    PORT
      LAYER M3 ;
        RECT  15.228 17.136 15.246 17.28 ;
    END
  END o[136]
  PIN o[137]
    DIRECTION OUTPUT ;
    USE SIGNAL ;
    PORT
      LAYER M5 ;
        RECT  15.36 17.088 15.384 17.28 ;
    END
  END o[137]
  PIN o[138]
    DIRECTION OUTPUT ;
    USE SIGNAL ;
    PORT
      LAYER M3 ;
        RECT  15.444 17.136 15.462 17.28 ;
    END
  END o[138]
  PIN o[139]
    DIRECTION OUTPUT ;
    USE SIGNAL ;
    PORT
      LAYER M5 ;
        RECT  15.552 17.088 15.576 17.28 ;
    END
  END o[139]
  PIN o[13]
    DIRECTION OUTPUT ;
    USE SIGNAL ;
    PORT
      LAYER M5 ;
        RECT  3.456 17.088 3.48 17.28 ;
    END
  END o[13]
  PIN o[140]
    DIRECTION OUTPUT ;
    USE SIGNAL ;
    PORT
      LAYER M3 ;
        RECT  15.624 17.136 15.642 17.28 ;
    END
  END o[140]
  PIN o[141]
    DIRECTION OUTPUT ;
    USE SIGNAL ;
    PORT
      LAYER M5 ;
        RECT  15.696 17.088 15.72 17.28 ;
    END
  END o[141]
  PIN o[142]
    DIRECTION OUTPUT ;
    USE SIGNAL ;
    PORT
      LAYER M3 ;
        RECT  15.804 17.136 15.822 17.28 ;
    END
  END o[142]
  PIN o[143]
    DIRECTION OUTPUT ;
    USE SIGNAL ;
    PORT
      LAYER M5 ;
        RECT  15.888 17.088 15.912 17.28 ;
    END
  END o[143]
  PIN o[144]
    DIRECTION OUTPUT ;
    USE SIGNAL ;
    PORT
      LAYER M3 ;
        RECT  16.02 17.136 16.038 17.28 ;
    END
  END o[144]
  PIN o[145]
    DIRECTION OUTPUT ;
    USE SIGNAL ;
    PORT
      LAYER M5 ;
        RECT  16.08 17.088 16.104 17.28 ;
    END
  END o[145]
  PIN o[146]
    DIRECTION OUTPUT ;
    USE SIGNAL ;
    PORT
      LAYER M3 ;
        RECT  16.2 17.136 16.218 17.28 ;
    END
  END o[146]
  PIN o[147]
    DIRECTION OUTPUT ;
    USE SIGNAL ;
    PORT
      LAYER M5 ;
        RECT  16.272 17.088 16.296 17.28 ;
    END
  END o[147]
  PIN o[148]
    DIRECTION OUTPUT ;
    USE SIGNAL ;
    PORT
      LAYER M3 ;
        RECT  16.38 17.136 16.398 17.28 ;
    END
  END o[148]
  PIN o[149]
    DIRECTION OUTPUT ;
    USE SIGNAL ;
    PORT
      LAYER M5 ;
        RECT  16.464 17.088 16.488 17.28 ;
    END
  END o[149]
  PIN o[14]
    DIRECTION OUTPUT ;
    USE SIGNAL ;
    PORT
      LAYER M3 ;
        RECT  3.528 17.136 3.546 17.28 ;
    END
  END o[14]
  PIN o[150]
    DIRECTION OUTPUT ;
    USE SIGNAL ;
    PORT
      LAYER M3 ;
        RECT  16.596 17.136 16.614 17.28 ;
    END
  END o[150]
  PIN o[151]
    DIRECTION OUTPUT ;
    USE SIGNAL ;
    PORT
      LAYER M5 ;
        RECT  16.656 17.088 16.68 17.28 ;
    END
  END o[151]
  PIN o[152]
    DIRECTION OUTPUT ;
    USE SIGNAL ;
    PORT
      LAYER M3 ;
        RECT  16.776 17.136 16.794 17.28 ;
    END
  END o[152]
  PIN o[153]
    DIRECTION OUTPUT ;
    USE SIGNAL ;
    PORT
      LAYER M5 ;
        RECT  16.848 17.088 16.872 17.28 ;
    END
  END o[153]
  PIN o[154]
    DIRECTION OUTPUT ;
    USE SIGNAL ;
    PORT
      LAYER M3 ;
        RECT  16.956 17.136 16.974 17.28 ;
    END
  END o[154]
  PIN o[155]
    DIRECTION OUTPUT ;
    USE SIGNAL ;
    PORT
      LAYER M5 ;
        RECT  17.04 17.088 17.064 17.28 ;
    END
  END o[155]
  PIN o[156]
    DIRECTION OUTPUT ;
    USE SIGNAL ;
    PORT
      LAYER M3 ;
        RECT  17.172 17.136 17.19 17.28 ;
    END
  END o[156]
  PIN o[157]
    DIRECTION OUTPUT ;
    USE SIGNAL ;
    PORT
      LAYER M5 ;
        RECT  17.232 17.088 17.256 17.28 ;
    END
  END o[157]
  PIN o[158]
    DIRECTION OUTPUT ;
    USE SIGNAL ;
    PORT
      LAYER M3 ;
        RECT  17.352 17.136 17.37 17.28 ;
    END
  END o[158]
  PIN o[159]
    DIRECTION OUTPUT ;
    USE SIGNAL ;
    PORT
      LAYER M5 ;
        RECT  17.424 17.088 17.448 17.28 ;
    END
  END o[159]
  PIN o[15]
    DIRECTION OUTPUT ;
    USE SIGNAL ;
    PORT
      LAYER M5 ;
        RECT  3.648 17.088 3.672 17.28 ;
    END
  END o[15]
  PIN o[160]
    DIRECTION OUTPUT ;
    USE SIGNAL ;
    PORT
      LAYER M3 ;
        RECT  17.532 17.136 17.55 17.28 ;
    END
  END o[160]
  PIN o[161]
    DIRECTION OUTPUT ;
    USE SIGNAL ;
    PORT
      LAYER M5 ;
        RECT  17.616 17.088 17.64 17.28 ;
    END
  END o[161]
  PIN o[162]
    DIRECTION OUTPUT ;
    USE SIGNAL ;
    PORT
      LAYER M3 ;
        RECT  17.748 17.136 17.766 17.28 ;
    END
  END o[162]
  PIN o[163]
    DIRECTION OUTPUT ;
    USE SIGNAL ;
    PORT
      LAYER M5 ;
        RECT  17.808 17.088 17.832 17.28 ;
    END
  END o[163]
  PIN o[164]
    DIRECTION OUTPUT ;
    USE SIGNAL ;
    PORT
      LAYER M3 ;
        RECT  17.928 17.136 17.946 17.28 ;
    END
  END o[164]
  PIN o[165]
    DIRECTION OUTPUT ;
    USE SIGNAL ;
    PORT
      LAYER M5 ;
        RECT  18 17.088 18.024 17.28 ;
    END
  END o[165]
  PIN o[166]
    DIRECTION OUTPUT ;
    USE SIGNAL ;
    PORT
      LAYER M3 ;
        RECT  18.108 17.136 18.126 17.28 ;
    END
  END o[166]
  PIN o[167]
    DIRECTION OUTPUT ;
    USE SIGNAL ;
    PORT
      LAYER M5 ;
        RECT  18.192 17.088 18.216 17.28 ;
    END
  END o[167]
  PIN o[168]
    DIRECTION OUTPUT ;
    USE SIGNAL ;
    PORT
      LAYER M3 ;
        RECT  18.324 17.136 18.342 17.28 ;
    END
  END o[168]
  PIN o[169]
    DIRECTION OUTPUT ;
    USE SIGNAL ;
    PORT
      LAYER M5 ;
        RECT  18.384 17.088 18.408 17.28 ;
    END
  END o[169]
  PIN o[16]
    DIRECTION OUTPUT ;
    USE SIGNAL ;
    PORT
      LAYER M3 ;
        RECT  3.744 17.136 3.762 17.28 ;
    END
  END o[16]
  PIN o[170]
    DIRECTION OUTPUT ;
    USE SIGNAL ;
    PORT
      LAYER M3 ;
        RECT  18.504 17.136 18.522 17.28 ;
    END
  END o[170]
  PIN o[171]
    DIRECTION OUTPUT ;
    USE SIGNAL ;
    PORT
      LAYER M5 ;
        RECT  18.576 17.088 18.6 17.28 ;
    END
  END o[171]
  PIN o[172]
    DIRECTION OUTPUT ;
    USE SIGNAL ;
    PORT
      LAYER M3 ;
        RECT  18.684 17.136 18.702 17.28 ;
    END
  END o[172]
  PIN o[173]
    DIRECTION OUTPUT ;
    USE SIGNAL ;
    PORT
      LAYER M5 ;
        RECT  18.768 17.088 18.792 17.28 ;
    END
  END o[173]
  PIN o[174]
    DIRECTION OUTPUT ;
    USE SIGNAL ;
    PORT
      LAYER M3 ;
        RECT  18.9 17.136 18.918 17.28 ;
    END
  END o[174]
  PIN o[175]
    DIRECTION OUTPUT ;
    USE SIGNAL ;
    PORT
      LAYER M5 ;
        RECT  18.96 17.088 18.984 17.28 ;
    END
  END o[175]
  PIN o[176]
    DIRECTION OUTPUT ;
    USE SIGNAL ;
    PORT
      LAYER M3 ;
        RECT  19.08 17.136 19.098 17.28 ;
    END
  END o[176]
  PIN o[177]
    DIRECTION OUTPUT ;
    USE SIGNAL ;
    PORT
      LAYER M5 ;
        RECT  19.152 17.088 19.176 17.28 ;
    END
  END o[177]
  PIN o[178]
    DIRECTION OUTPUT ;
    USE SIGNAL ;
    PORT
      LAYER M3 ;
        RECT  19.26 17.136 19.278 17.28 ;
    END
  END o[178]
  PIN o[179]
    DIRECTION OUTPUT ;
    USE SIGNAL ;
    PORT
      LAYER M5 ;
        RECT  19.344 17.088 19.368 17.28 ;
    END
  END o[179]
  PIN o[17]
    DIRECTION OUTPUT ;
    USE SIGNAL ;
    PORT
      LAYER M5 ;
        RECT  3.84 17.088 3.864 17.28 ;
    END
  END o[17]
  PIN o[180]
    DIRECTION OUTPUT ;
    USE SIGNAL ;
    PORT
      LAYER M3 ;
        RECT  19.476 17.136 19.494 17.28 ;
    END
  END o[180]
  PIN o[181]
    DIRECTION OUTPUT ;
    USE SIGNAL ;
    PORT
      LAYER M5 ;
        RECT  19.536 17.088 19.56 17.28 ;
    END
  END o[181]
  PIN o[182]
    DIRECTION OUTPUT ;
    USE SIGNAL ;
    PORT
      LAYER M3 ;
        RECT  19.656 17.136 19.674 17.28 ;
    END
  END o[182]
  PIN o[183]
    DIRECTION OUTPUT ;
    USE SIGNAL ;
    PORT
      LAYER M5 ;
        RECT  19.728 17.088 19.752 17.28 ;
    END
  END o[183]
  PIN o[184]
    DIRECTION OUTPUT ;
    USE SIGNAL ;
    PORT
      LAYER M3 ;
        RECT  19.836 17.136 19.854 17.28 ;
    END
  END o[184]
  PIN o[185]
    DIRECTION OUTPUT ;
    USE SIGNAL ;
    PORT
      LAYER M5 ;
        RECT  19.92 17.088 19.944 17.28 ;
    END
  END o[185]
  PIN o[186]
    DIRECTION OUTPUT ;
    USE SIGNAL ;
    PORT
      LAYER M3 ;
        RECT  20.052 17.136 20.07 17.28 ;
    END
  END o[186]
  PIN o[187]
    DIRECTION OUTPUT ;
    USE SIGNAL ;
    PORT
      LAYER M5 ;
        RECT  20.112 17.088 20.136 17.28 ;
    END
  END o[187]
  PIN o[188]
    DIRECTION OUTPUT ;
    USE SIGNAL ;
    PORT
      LAYER M3 ;
        RECT  20.232 17.136 20.25 17.28 ;
    END
  END o[188]
  PIN o[189]
    DIRECTION OUTPUT ;
    USE SIGNAL ;
    PORT
      LAYER M5 ;
        RECT  20.304 17.088 20.328 17.28 ;
    END
  END o[189]
  PIN o[18]
    DIRECTION OUTPUT ;
    USE SIGNAL ;
    PORT
      LAYER M3 ;
        RECT  3.924 17.136 3.942 17.28 ;
    END
  END o[18]
  PIN o[190]
    DIRECTION OUTPUT ;
    USE SIGNAL ;
    PORT
      LAYER M3 ;
        RECT  20.412 17.136 20.43 17.28 ;
    END
  END o[190]
  PIN o[191]
    DIRECTION OUTPUT ;
    USE SIGNAL ;
    PORT
      LAYER M5 ;
        RECT  20.496 17.088 20.52 17.28 ;
    END
  END o[191]
  PIN o[192]
    DIRECTION OUTPUT ;
    USE SIGNAL ;
    PORT
      LAYER M3 ;
        RECT  20.628 17.136 20.646 17.28 ;
    END
  END o[192]
  PIN o[193]
    DIRECTION OUTPUT ;
    USE SIGNAL ;
    PORT
      LAYER M5 ;
        RECT  20.688 17.088 20.712 17.28 ;
    END
  END o[193]
  PIN o[194]
    DIRECTION OUTPUT ;
    USE SIGNAL ;
    PORT
      LAYER M3 ;
        RECT  20.808 17.136 20.826 17.28 ;
    END
  END o[194]
  PIN o[195]
    DIRECTION OUTPUT ;
    USE SIGNAL ;
    PORT
      LAYER M5 ;
        RECT  20.88 17.088 20.904 17.28 ;
    END
  END o[195]
  PIN o[196]
    DIRECTION OUTPUT ;
    USE SIGNAL ;
    PORT
      LAYER M3 ;
        RECT  20.988 17.136 21.006 17.28 ;
    END
  END o[196]
  PIN o[197]
    DIRECTION OUTPUT ;
    USE SIGNAL ;
    PORT
      LAYER M5 ;
        RECT  21.072 17.088 21.096 17.28 ;
    END
  END o[197]
  PIN o[198]
    DIRECTION OUTPUT ;
    USE SIGNAL ;
    PORT
      LAYER M3 ;
        RECT  21.204 17.136 21.222 17.28 ;
    END
  END o[198]
  PIN o[199]
    DIRECTION OUTPUT ;
    USE SIGNAL ;
    PORT
      LAYER M5 ;
        RECT  21.264 17.088 21.288 17.28 ;
    END
  END o[199]
  PIN o[19]
    DIRECTION OUTPUT ;
    USE SIGNAL ;
    PORT
      LAYER M5 ;
        RECT  4.032 17.088 4.056 17.28 ;
    END
  END o[19]
  PIN o[1]
    DIRECTION OUTPUT ;
    USE SIGNAL ;
    PORT
      LAYER M5 ;
        RECT  2.304 17.088 2.328 17.28 ;
    END
  END o[1]
  PIN o[200]
    DIRECTION OUTPUT ;
    USE SIGNAL ;
    PORT
      LAYER M3 ;
        RECT  21.384 17.136 21.402 17.28 ;
    END
  END o[200]
  PIN o[201]
    DIRECTION OUTPUT ;
    USE SIGNAL ;
    PORT
      LAYER M5 ;
        RECT  21.456 17.088 21.48 17.28 ;
    END
  END o[201]
  PIN o[202]
    DIRECTION OUTPUT ;
    USE SIGNAL ;
    PORT
      LAYER M3 ;
        RECT  21.564 17.136 21.582 17.28 ;
    END
  END o[202]
  PIN o[203]
    DIRECTION OUTPUT ;
    USE SIGNAL ;
    PORT
      LAYER M5 ;
        RECT  21.648 17.088 21.672 17.28 ;
    END
  END o[203]
  PIN o[204]
    DIRECTION OUTPUT ;
    USE SIGNAL ;
    PORT
      LAYER M3 ;
        RECT  21.78 17.136 21.798 17.28 ;
    END
  END o[204]
  PIN o[205]
    DIRECTION OUTPUT ;
    USE SIGNAL ;
    PORT
      LAYER M5 ;
        RECT  21.84 17.088 21.864 17.28 ;
    END
  END o[205]
  PIN o[206]
    DIRECTION OUTPUT ;
    USE SIGNAL ;
    PORT
      LAYER M3 ;
        RECT  21.96 17.136 21.978 17.28 ;
    END
  END o[206]
  PIN o[207]
    DIRECTION OUTPUT ;
    USE SIGNAL ;
    PORT
      LAYER M5 ;
        RECT  22.032 17.088 22.056 17.28 ;
    END
  END o[207]
  PIN o[208]
    DIRECTION OUTPUT ;
    USE SIGNAL ;
    PORT
      LAYER M3 ;
        RECT  22.14 17.136 22.158 17.28 ;
    END
  END o[208]
  PIN o[209]
    DIRECTION OUTPUT ;
    USE SIGNAL ;
    PORT
      LAYER M5 ;
        RECT  22.224 17.088 22.248 17.28 ;
    END
  END o[209]
  PIN o[20]
    DIRECTION OUTPUT ;
    USE SIGNAL ;
    PORT
      LAYER M3 ;
        RECT  4.104 17.136 4.122 17.28 ;
    END
  END o[20]
  PIN o[210]
    DIRECTION OUTPUT ;
    USE SIGNAL ;
    PORT
      LAYER M3 ;
        RECT  22.356 17.136 22.374 17.28 ;
    END
  END o[210]
  PIN o[211]
    DIRECTION OUTPUT ;
    USE SIGNAL ;
    PORT
      LAYER M5 ;
        RECT  22.416 17.088 22.44 17.28 ;
    END
  END o[211]
  PIN o[212]
    DIRECTION OUTPUT ;
    USE SIGNAL ;
    PORT
      LAYER M3 ;
        RECT  22.536 17.136 22.554 17.28 ;
    END
  END o[212]
  PIN o[213]
    DIRECTION OUTPUT ;
    USE SIGNAL ;
    PORT
      LAYER M5 ;
        RECT  22.608 17.088 22.632 17.28 ;
    END
  END o[213]
  PIN o[214]
    DIRECTION OUTPUT ;
    USE SIGNAL ;
    PORT
      LAYER M3 ;
        RECT  22.716 17.136 22.734 17.28 ;
    END
  END o[214]
  PIN o[215]
    DIRECTION OUTPUT ;
    USE SIGNAL ;
    PORT
      LAYER M5 ;
        RECT  22.8 17.088 22.824 17.28 ;
    END
  END o[215]
  PIN o[216]
    DIRECTION OUTPUT ;
    USE SIGNAL ;
    PORT
      LAYER M3 ;
        RECT  22.932 17.136 22.95 17.28 ;
    END
  END o[216]
  PIN o[217]
    DIRECTION OUTPUT ;
    USE SIGNAL ;
    PORT
      LAYER M5 ;
        RECT  22.992 17.088 23.016 17.28 ;
    END
  END o[217]
  PIN o[218]
    DIRECTION OUTPUT ;
    USE SIGNAL ;
    PORT
      LAYER M3 ;
        RECT  23.112 17.136 23.13 17.28 ;
    END
  END o[218]
  PIN o[219]
    DIRECTION OUTPUT ;
    USE SIGNAL ;
    PORT
      LAYER M5 ;
        RECT  23.184 17.088 23.208 17.28 ;
    END
  END o[219]
  PIN o[21]
    DIRECTION OUTPUT ;
    USE SIGNAL ;
    PORT
      LAYER M5 ;
        RECT  4.224 17.088 4.248 17.28 ;
    END
  END o[21]
  PIN o[220]
    DIRECTION OUTPUT ;
    USE SIGNAL ;
    PORT
      LAYER M3 ;
        RECT  23.292 17.136 23.31 17.28 ;
    END
  END o[220]
  PIN o[221]
    DIRECTION OUTPUT ;
    USE SIGNAL ;
    PORT
      LAYER M5 ;
        RECT  23.376 17.088 23.4 17.28 ;
    END
  END o[221]
  PIN o[222]
    DIRECTION OUTPUT ;
    USE SIGNAL ;
    PORT
      LAYER M3 ;
        RECT  23.508 17.136 23.526 17.28 ;
    END
  END o[222]
  PIN o[223]
    DIRECTION OUTPUT ;
    USE SIGNAL ;
    PORT
      LAYER M5 ;
        RECT  23.568 17.088 23.592 17.28 ;
    END
  END o[223]
  PIN o[224]
    DIRECTION OUTPUT ;
    USE SIGNAL ;
    PORT
      LAYER M3 ;
        RECT  23.688 17.136 23.706 17.28 ;
    END
  END o[224]
  PIN o[225]
    DIRECTION OUTPUT ;
    USE SIGNAL ;
    PORT
      LAYER M5 ;
        RECT  23.76 17.088 23.784 17.28 ;
    END
  END o[225]
  PIN o[226]
    DIRECTION OUTPUT ;
    USE SIGNAL ;
    PORT
      LAYER M3 ;
        RECT  23.868 17.136 23.886 17.28 ;
    END
  END o[226]
  PIN o[227]
    DIRECTION OUTPUT ;
    USE SIGNAL ;
    PORT
      LAYER M5 ;
        RECT  23.952 17.088 23.976 17.28 ;
    END
  END o[227]
  PIN o[228]
    DIRECTION OUTPUT ;
    USE SIGNAL ;
    PORT
      LAYER M3 ;
        RECT  24.084 17.136 24.102 17.28 ;
    END
  END o[228]
  PIN o[229]
    DIRECTION OUTPUT ;
    USE SIGNAL ;
    PORT
      LAYER M5 ;
        RECT  24.144 17.088 24.168 17.28 ;
    END
  END o[229]
  PIN o[22]
    DIRECTION OUTPUT ;
    USE SIGNAL ;
    PORT
      LAYER M3 ;
        RECT  4.32 17.136 4.338 17.28 ;
    END
  END o[22]
  PIN o[230]
    DIRECTION OUTPUT ;
    USE SIGNAL ;
    PORT
      LAYER M3 ;
        RECT  24.264 17.136 24.282 17.28 ;
    END
  END o[230]
  PIN o[231]
    DIRECTION OUTPUT ;
    USE SIGNAL ;
    PORT
      LAYER M5 ;
        RECT  24.336 17.088 24.36 17.28 ;
    END
  END o[231]
  PIN o[232]
    DIRECTION OUTPUT ;
    USE SIGNAL ;
    PORT
      LAYER M3 ;
        RECT  24.444 17.136 24.462 17.28 ;
    END
  END o[232]
  PIN o[233]
    DIRECTION OUTPUT ;
    USE SIGNAL ;
    PORT
      LAYER M5 ;
        RECT  24.528 17.088 24.552 17.28 ;
    END
  END o[233]
  PIN o[234]
    DIRECTION OUTPUT ;
    USE SIGNAL ;
    PORT
      LAYER M3 ;
        RECT  24.66 17.136 24.678 17.28 ;
    END
  END o[234]
  PIN o[235]
    DIRECTION OUTPUT ;
    USE SIGNAL ;
    PORT
      LAYER M5 ;
        RECT  24.72 17.088 24.744 17.28 ;
    END
  END o[235]
  PIN o[236]
    DIRECTION OUTPUT ;
    USE SIGNAL ;
    PORT
      LAYER M3 ;
        RECT  24.84 17.136 24.858 17.28 ;
    END
  END o[236]
  PIN o[237]
    DIRECTION OUTPUT ;
    USE SIGNAL ;
    PORT
      LAYER M5 ;
        RECT  24.912 17.088 24.936 17.28 ;
    END
  END o[237]
  PIN o[238]
    DIRECTION OUTPUT ;
    USE SIGNAL ;
    PORT
      LAYER M3 ;
        RECT  25.02 17.136 25.038 17.28 ;
    END
  END o[238]
  PIN o[239]
    DIRECTION OUTPUT ;
    USE SIGNAL ;
    PORT
      LAYER M5 ;
        RECT  25.104 17.088 25.128 17.28 ;
    END
  END o[239]
  PIN o[23]
    DIRECTION OUTPUT ;
    USE SIGNAL ;
    PORT
      LAYER M5 ;
        RECT  4.416 17.088 4.44 17.28 ;
    END
  END o[23]
  PIN o[240]
    DIRECTION OUTPUT ;
    USE SIGNAL ;
    PORT
      LAYER M3 ;
        RECT  25.236 17.136 25.254 17.28 ;
    END
  END o[240]
  PIN o[241]
    DIRECTION OUTPUT ;
    USE SIGNAL ;
    PORT
      LAYER M5 ;
        RECT  25.296 17.088 25.32 17.28 ;
    END
  END o[241]
  PIN o[242]
    DIRECTION OUTPUT ;
    USE SIGNAL ;
    PORT
      LAYER M3 ;
        RECT  25.416 17.136 25.434 17.28 ;
    END
  END o[242]
  PIN o[243]
    DIRECTION OUTPUT ;
    USE SIGNAL ;
    PORT
      LAYER M5 ;
        RECT  25.488 17.088 25.512 17.28 ;
    END
  END o[243]
  PIN o[244]
    DIRECTION OUTPUT ;
    USE SIGNAL ;
    PORT
      LAYER M3 ;
        RECT  25.596 17.136 25.614 17.28 ;
    END
  END o[244]
  PIN o[245]
    DIRECTION OUTPUT ;
    USE SIGNAL ;
    PORT
      LAYER M5 ;
        RECT  25.68 17.088 25.704 17.28 ;
    END
  END o[245]
  PIN o[246]
    DIRECTION OUTPUT ;
    USE SIGNAL ;
    PORT
      LAYER M3 ;
        RECT  25.776 17.136 25.794 17.28 ;
    END
  END o[246]
  PIN o[247]
    DIRECTION OUTPUT ;
    USE SIGNAL ;
    PORT
      LAYER M5 ;
        RECT  25.872 17.088 25.896 17.28 ;
    END
  END o[247]
  PIN o[248]
    DIRECTION OUTPUT ;
    USE SIGNAL ;
    PORT
      LAYER M3 ;
        RECT  25.992 17.136 26.01 17.28 ;
    END
  END o[248]
  PIN o[249]
    DIRECTION OUTPUT ;
    USE SIGNAL ;
    PORT
      LAYER M5 ;
        RECT  26.064 17.088 26.088 17.28 ;
    END
  END o[249]
  PIN o[24]
    DIRECTION OUTPUT ;
    USE SIGNAL ;
    PORT
      LAYER M3 ;
        RECT  4.5 17.136 4.518 17.28 ;
    END
  END o[24]
  PIN o[250]
    DIRECTION OUTPUT ;
    USE SIGNAL ;
    PORT
      LAYER M3 ;
        RECT  26.172 17.136 26.19 17.28 ;
    END
  END o[250]
  PIN o[251]
    DIRECTION OUTPUT ;
    USE SIGNAL ;
    PORT
      LAYER M5 ;
        RECT  26.256 17.088 26.28 17.28 ;
    END
  END o[251]
  PIN o[252]
    DIRECTION OUTPUT ;
    USE SIGNAL ;
    PORT
      LAYER M3 ;
        RECT  26.352 17.136 26.37 17.28 ;
    END
  END o[252]
  PIN o[253]
    DIRECTION OUTPUT ;
    USE SIGNAL ;
    PORT
      LAYER M5 ;
        RECT  26.448 17.088 26.472 17.28 ;
    END
  END o[253]
  PIN o[254]
    DIRECTION OUTPUT ;
    USE SIGNAL ;
    PORT
      LAYER M3 ;
        RECT  26.568 17.136 26.586 17.28 ;
    END
  END o[254]
  PIN o[255]
    DIRECTION OUTPUT ;
    USE SIGNAL ;
    PORT
      LAYER M5 ;
        RECT  26.64 17.088 26.664 17.28 ;
    END
  END o[255]
  PIN o[256]
    DIRECTION OUTPUT ;
    USE SIGNAL ;
    PORT
      LAYER M3 ;
        RECT  26.748 17.136 26.766 17.28 ;
    END
  END o[256]
  PIN o[257]
    DIRECTION OUTPUT ;
    USE SIGNAL ;
    PORT
      LAYER M5 ;
        RECT  26.832 17.088 26.856 17.28 ;
    END
  END o[257]
  PIN o[258]
    DIRECTION OUTPUT ;
    USE SIGNAL ;
    PORT
      LAYER M3 ;
        RECT  26.928 17.136 26.946 17.28 ;
    END
  END o[258]
  PIN o[259]
    DIRECTION OUTPUT ;
    USE SIGNAL ;
    PORT
      LAYER M5 ;
        RECT  27.024 17.088 27.048 17.28 ;
    END
  END o[259]
  PIN o[25]
    DIRECTION OUTPUT ;
    USE SIGNAL ;
    PORT
      LAYER M5 ;
        RECT  4.608 17.088 4.632 17.28 ;
    END
  END o[25]
  PIN o[260]
    DIRECTION OUTPUT ;
    USE SIGNAL ;
    PORT
      LAYER M3 ;
        RECT  27.144 17.136 27.162 17.28 ;
    END
  END o[260]
  PIN o[261]
    DIRECTION OUTPUT ;
    USE SIGNAL ;
    PORT
      LAYER M5 ;
        RECT  27.216 17.088 27.24 17.28 ;
    END
  END o[261]
  PIN o[262]
    DIRECTION OUTPUT ;
    USE SIGNAL ;
    PORT
      LAYER M3 ;
        RECT  27.324 17.136 27.342 17.28 ;
    END
  END o[262]
  PIN o[263]
    DIRECTION OUTPUT ;
    USE SIGNAL ;
    PORT
      LAYER M5 ;
        RECT  27.408 17.088 27.432 17.28 ;
    END
  END o[263]
  PIN o[264]
    DIRECTION OUTPUT ;
    USE SIGNAL ;
    PORT
      LAYER M3 ;
        RECT  27.504 17.136 27.522 17.28 ;
    END
  END o[264]
  PIN o[265]
    DIRECTION OUTPUT ;
    USE SIGNAL ;
    PORT
      LAYER M5 ;
        RECT  27.6 17.088 27.624 17.28 ;
    END
  END o[265]
  PIN o[266]
    DIRECTION OUTPUT ;
    USE SIGNAL ;
    PORT
      LAYER M3 ;
        RECT  27.72 17.136 27.738 17.28 ;
    END
  END o[266]
  PIN o[267]
    DIRECTION OUTPUT ;
    USE SIGNAL ;
    PORT
      LAYER M5 ;
        RECT  27.792 17.088 27.816 17.28 ;
    END
  END o[267]
  PIN o[268]
    DIRECTION OUTPUT ;
    USE SIGNAL ;
    PORT
      LAYER M3 ;
        RECT  27.9 17.136 27.918 17.28 ;
    END
  END o[268]
  PIN o[269]
    DIRECTION OUTPUT ;
    USE SIGNAL ;
    PORT
      LAYER M5 ;
        RECT  27.984 17.088 28.008 17.28 ;
    END
  END o[269]
  PIN o[26]
    DIRECTION OUTPUT ;
    USE SIGNAL ;
    PORT
      LAYER M3 ;
        RECT  4.68 17.136 4.698 17.28 ;
    END
  END o[26]
  PIN o[270]
    DIRECTION OUTPUT ;
    USE SIGNAL ;
    PORT
      LAYER M3 ;
        RECT  28.08 17.136 28.098 17.28 ;
    END
  END o[270]
  PIN o[271]
    DIRECTION OUTPUT ;
    USE SIGNAL ;
    PORT
      LAYER M5 ;
        RECT  28.176 17.088 28.2 17.28 ;
    END
  END o[271]
  PIN o[272]
    DIRECTION OUTPUT ;
    USE SIGNAL ;
    PORT
      LAYER M3 ;
        RECT  28.296 17.136 28.314 17.28 ;
    END
  END o[272]
  PIN o[273]
    DIRECTION OUTPUT ;
    USE SIGNAL ;
    PORT
      LAYER M5 ;
        RECT  28.368 17.088 28.392 17.28 ;
    END
  END o[273]
  PIN o[274]
    DIRECTION OUTPUT ;
    USE SIGNAL ;
    PORT
      LAYER M3 ;
        RECT  28.476 17.136 28.494 17.28 ;
    END
  END o[274]
  PIN o[275]
    DIRECTION OUTPUT ;
    USE SIGNAL ;
    PORT
      LAYER M5 ;
        RECT  28.56 17.088 28.584 17.28 ;
    END
  END o[275]
  PIN o[276]
    DIRECTION OUTPUT ;
    USE SIGNAL ;
    PORT
      LAYER M3 ;
        RECT  28.656 17.136 28.674 17.28 ;
    END
  END o[276]
  PIN o[277]
    DIRECTION OUTPUT ;
    USE SIGNAL ;
    PORT
      LAYER M5 ;
        RECT  28.752 17.088 28.776 17.28 ;
    END
  END o[277]
  PIN o[278]
    DIRECTION OUTPUT ;
    USE SIGNAL ;
    PORT
      LAYER M3 ;
        RECT  28.872 17.136 28.89 17.28 ;
    END
  END o[278]
  PIN o[279]
    DIRECTION OUTPUT ;
    USE SIGNAL ;
    PORT
      LAYER M5 ;
        RECT  28.944 17.088 28.968 17.28 ;
    END
  END o[279]
  PIN o[27]
    DIRECTION OUTPUT ;
    USE SIGNAL ;
    PORT
      LAYER M5 ;
        RECT  4.8 17.088 4.824 17.28 ;
    END
  END o[27]
  PIN o[280]
    DIRECTION OUTPUT ;
    USE SIGNAL ;
    PORT
      LAYER M3 ;
        RECT  29.052 17.136 29.07 17.28 ;
    END
  END o[280]
  PIN o[281]
    DIRECTION OUTPUT ;
    USE SIGNAL ;
    PORT
      LAYER M5 ;
        RECT  29.136 17.088 29.16 17.28 ;
    END
  END o[281]
  PIN o[282]
    DIRECTION OUTPUT ;
    USE SIGNAL ;
    PORT
      LAYER M3 ;
        RECT  29.232 17.136 29.25 17.28 ;
    END
  END o[282]
  PIN o[283]
    DIRECTION OUTPUT ;
    USE SIGNAL ;
    PORT
      LAYER M5 ;
        RECT  29.328 17.088 29.352 17.28 ;
    END
  END o[283]
  PIN o[284]
    DIRECTION OUTPUT ;
    USE SIGNAL ;
    PORT
      LAYER M3 ;
        RECT  29.448 17.136 29.466 17.28 ;
    END
  END o[284]
  PIN o[285]
    DIRECTION OUTPUT ;
    USE SIGNAL ;
    PORT
      LAYER M5 ;
        RECT  29.52 17.088 29.544 17.28 ;
    END
  END o[285]
  PIN o[286]
    DIRECTION OUTPUT ;
    USE SIGNAL ;
    PORT
      LAYER M3 ;
        RECT  29.628 17.136 29.646 17.28 ;
    END
  END o[286]
  PIN o[287]
    DIRECTION OUTPUT ;
    USE SIGNAL ;
    PORT
      LAYER M5 ;
        RECT  29.712 17.088 29.736 17.28 ;
    END
  END o[287]
  PIN o[288]
    DIRECTION OUTPUT ;
    USE SIGNAL ;
    PORT
      LAYER M3 ;
        RECT  29.808 17.136 29.826 17.28 ;
    END
  END o[288]
  PIN o[289]
    DIRECTION OUTPUT ;
    USE SIGNAL ;
    PORT
      LAYER M5 ;
        RECT  29.904 17.088 29.928 17.28 ;
    END
  END o[289]
  PIN o[28]
    DIRECTION OUTPUT ;
    USE SIGNAL ;
    PORT
      LAYER M3 ;
        RECT  4.896 17.136 4.914 17.28 ;
    END
  END o[28]
  PIN o[290]
    DIRECTION OUTPUT ;
    USE SIGNAL ;
    PORT
      LAYER M3 ;
        RECT  30.024 17.136 30.042 17.28 ;
    END
  END o[290]
  PIN o[291]
    DIRECTION OUTPUT ;
    USE SIGNAL ;
    PORT
      LAYER M5 ;
        RECT  30.096 17.088 30.12 17.28 ;
    END
  END o[291]
  PIN o[292]
    DIRECTION OUTPUT ;
    USE SIGNAL ;
    PORT
      LAYER M3 ;
        RECT  30.204 17.136 30.222 17.28 ;
    END
  END o[292]
  PIN o[293]
    DIRECTION OUTPUT ;
    USE SIGNAL ;
    PORT
      LAYER M5 ;
        RECT  30.288 17.088 30.312 17.28 ;
    END
  END o[293]
  PIN o[294]
    DIRECTION OUTPUT ;
    USE SIGNAL ;
    PORT
      LAYER M3 ;
        RECT  30.384 17.136 30.402 17.28 ;
    END
  END o[294]
  PIN o[295]
    DIRECTION OUTPUT ;
    USE SIGNAL ;
    PORT
      LAYER M5 ;
        RECT  30.48 17.088 30.504 17.28 ;
    END
  END o[295]
  PIN o[296]
    DIRECTION OUTPUT ;
    USE SIGNAL ;
    PORT
      LAYER M3 ;
        RECT  30.6 17.136 30.618 17.28 ;
    END
  END o[296]
  PIN o[297]
    DIRECTION OUTPUT ;
    USE SIGNAL ;
    PORT
      LAYER M5 ;
        RECT  30.672 17.088 30.696 17.28 ;
    END
  END o[297]
  PIN o[298]
    DIRECTION OUTPUT ;
    USE SIGNAL ;
    PORT
      LAYER M3 ;
        RECT  30.78 17.136 30.798 17.28 ;
    END
  END o[298]
  PIN o[299]
    DIRECTION OUTPUT ;
    USE SIGNAL ;
    PORT
      LAYER M5 ;
        RECT  30.864 17.088 30.888 17.28 ;
    END
  END o[299]
  PIN o[29]
    DIRECTION OUTPUT ;
    USE SIGNAL ;
    PORT
      LAYER M5 ;
        RECT  4.992 17.088 5.016 17.28 ;
    END
  END o[29]
  PIN o[2]
    DIRECTION OUTPUT ;
    USE SIGNAL ;
    PORT
      LAYER M3 ;
        RECT  2.376 17.136 2.394 17.28 ;
    END
  END o[2]
  PIN o[300]
    DIRECTION OUTPUT ;
    USE SIGNAL ;
    PORT
      LAYER M3 ;
        RECT  30.96 17.136 30.978 17.28 ;
    END
  END o[300]
  PIN o[301]
    DIRECTION OUTPUT ;
    USE SIGNAL ;
    PORT
      LAYER M5 ;
        RECT  31.056 17.088 31.08 17.28 ;
    END
  END o[301]
  PIN o[302]
    DIRECTION OUTPUT ;
    USE SIGNAL ;
    PORT
      LAYER M3 ;
        RECT  31.176 17.136 31.194 17.28 ;
    END
  END o[302]
  PIN o[303]
    DIRECTION OUTPUT ;
    USE SIGNAL ;
    PORT
      LAYER M5 ;
        RECT  31.248 17.088 31.272 17.28 ;
    END
  END o[303]
  PIN o[304]
    DIRECTION OUTPUT ;
    USE SIGNAL ;
    PORT
      LAYER M3 ;
        RECT  31.356 17.136 31.374 17.28 ;
    END
  END o[304]
  PIN o[305]
    DIRECTION OUTPUT ;
    USE SIGNAL ;
    PORT
      LAYER M5 ;
        RECT  31.44 17.088 31.464 17.28 ;
    END
  END o[305]
  PIN o[306]
    DIRECTION OUTPUT ;
    USE SIGNAL ;
    PORT
      LAYER M3 ;
        RECT  31.536 17.136 31.554 17.28 ;
    END
  END o[306]
  PIN o[307]
    DIRECTION OUTPUT ;
    USE SIGNAL ;
    PORT
      LAYER M5 ;
        RECT  31.632 17.088 31.656 17.28 ;
    END
  END o[307]
  PIN o[308]
    DIRECTION OUTPUT ;
    USE SIGNAL ;
    PORT
      LAYER M3 ;
        RECT  31.752 17.136 31.77 17.28 ;
    END
  END o[308]
  PIN o[309]
    DIRECTION OUTPUT ;
    USE SIGNAL ;
    PORT
      LAYER M5 ;
        RECT  31.824 17.088 31.848 17.28 ;
    END
  END o[309]
  PIN o[30]
    DIRECTION OUTPUT ;
    USE SIGNAL ;
    PORT
      LAYER M3 ;
        RECT  5.076 17.136 5.094 17.28 ;
    END
  END o[30]
  PIN o[310]
    DIRECTION OUTPUT ;
    USE SIGNAL ;
    PORT
      LAYER M3 ;
        RECT  31.932 17.136 31.95 17.28 ;
    END
  END o[310]
  PIN o[311]
    DIRECTION OUTPUT ;
    USE SIGNAL ;
    PORT
      LAYER M5 ;
        RECT  32.016 17.088 32.04 17.28 ;
    END
  END o[311]
  PIN o[312]
    DIRECTION OUTPUT ;
    USE SIGNAL ;
    PORT
      LAYER M3 ;
        RECT  32.112 17.136 32.13 17.28 ;
    END
  END o[312]
  PIN o[313]
    DIRECTION OUTPUT ;
    USE SIGNAL ;
    PORT
      LAYER M5 ;
        RECT  32.208 17.088 32.232 17.28 ;
    END
  END o[313]
  PIN o[314]
    DIRECTION OUTPUT ;
    USE SIGNAL ;
    PORT
      LAYER M3 ;
        RECT  32.328 17.136 32.346 17.28 ;
    END
  END o[314]
  PIN o[315]
    DIRECTION OUTPUT ;
    USE SIGNAL ;
    PORT
      LAYER M5 ;
        RECT  32.4 17.088 32.424 17.28 ;
    END
  END o[315]
  PIN o[316]
    DIRECTION OUTPUT ;
    USE SIGNAL ;
    PORT
      LAYER M3 ;
        RECT  32.508 17.136 32.526 17.28 ;
    END
  END o[316]
  PIN o[317]
    DIRECTION OUTPUT ;
    USE SIGNAL ;
    PORT
      LAYER M5 ;
        RECT  32.592 17.088 32.616 17.28 ;
    END
  END o[317]
  PIN o[318]
    DIRECTION OUTPUT ;
    USE SIGNAL ;
    PORT
      LAYER M3 ;
        RECT  32.688 17.136 32.706 17.28 ;
    END
  END o[318]
  PIN o[319]
    DIRECTION OUTPUT ;
    USE SIGNAL ;
    PORT
      LAYER M5 ;
        RECT  32.784 17.088 32.808 17.28 ;
    END
  END o[319]
  PIN o[31]
    DIRECTION OUTPUT ;
    USE SIGNAL ;
    PORT
      LAYER M5 ;
        RECT  5.184 17.088 5.208 17.28 ;
    END
  END o[31]
  PIN o[320]
    DIRECTION OUTPUT ;
    USE SIGNAL ;
    PORT
      LAYER M3 ;
        RECT  32.904 17.136 32.922 17.28 ;
    END
  END o[320]
  PIN o[321]
    DIRECTION OUTPUT ;
    USE SIGNAL ;
    PORT
      LAYER M5 ;
        RECT  32.976 17.088 33 17.28 ;
    END
  END o[321]
  PIN o[322]
    DIRECTION OUTPUT ;
    USE SIGNAL ;
    PORT
      LAYER M3 ;
        RECT  33.084 17.136 33.102 17.28 ;
    END
  END o[322]
  PIN o[323]
    DIRECTION OUTPUT ;
    USE SIGNAL ;
    PORT
      LAYER M5 ;
        RECT  33.168 17.088 33.192 17.28 ;
    END
  END o[323]
  PIN o[324]
    DIRECTION OUTPUT ;
    USE SIGNAL ;
    PORT
      LAYER M3 ;
        RECT  33.264 17.136 33.282 17.28 ;
    END
  END o[324]
  PIN o[325]
    DIRECTION OUTPUT ;
    USE SIGNAL ;
    PORT
      LAYER M5 ;
        RECT  33.36 17.088 33.384 17.28 ;
    END
  END o[325]
  PIN o[326]
    DIRECTION OUTPUT ;
    USE SIGNAL ;
    PORT
      LAYER M3 ;
        RECT  33.48 17.136 33.498 17.28 ;
    END
  END o[326]
  PIN o[327]
    DIRECTION OUTPUT ;
    USE SIGNAL ;
    PORT
      LAYER M5 ;
        RECT  33.552 17.088 33.576 17.28 ;
    END
  END o[327]
  PIN o[328]
    DIRECTION OUTPUT ;
    USE SIGNAL ;
    PORT
      LAYER M3 ;
        RECT  33.66 17.136 33.678 17.28 ;
    END
  END o[328]
  PIN o[329]
    DIRECTION OUTPUT ;
    USE SIGNAL ;
    PORT
      LAYER M5 ;
        RECT  33.744 17.088 33.768 17.28 ;
    END
  END o[329]
  PIN o[32]
    DIRECTION OUTPUT ;
    USE SIGNAL ;
    PORT
      LAYER M3 ;
        RECT  5.256 17.136 5.274 17.28 ;
    END
  END o[32]
  PIN o[330]
    DIRECTION OUTPUT ;
    USE SIGNAL ;
    PORT
      LAYER M3 ;
        RECT  33.84 17.136 33.858 17.28 ;
    END
  END o[330]
  PIN o[331]
    DIRECTION OUTPUT ;
    USE SIGNAL ;
    PORT
      LAYER M5 ;
        RECT  33.936 17.088 33.96 17.28 ;
    END
  END o[331]
  PIN o[332]
    DIRECTION OUTPUT ;
    USE SIGNAL ;
    PORT
      LAYER M3 ;
        RECT  34.056 17.136 34.074 17.28 ;
    END
  END o[332]
  PIN o[333]
    DIRECTION OUTPUT ;
    USE SIGNAL ;
    PORT
      LAYER M5 ;
        RECT  34.128 17.088 34.152 17.28 ;
    END
  END o[333]
  PIN o[334]
    DIRECTION OUTPUT ;
    USE SIGNAL ;
    PORT
      LAYER M3 ;
        RECT  34.236 17.136 34.254 17.28 ;
    END
  END o[334]
  PIN o[335]
    DIRECTION OUTPUT ;
    USE SIGNAL ;
    PORT
      LAYER M5 ;
        RECT  34.32 17.088 34.344 17.28 ;
    END
  END o[335]
  PIN o[336]
    DIRECTION OUTPUT ;
    USE SIGNAL ;
    PORT
      LAYER M3 ;
        RECT  34.416 17.136 34.434 17.28 ;
    END
  END o[336]
  PIN o[337]
    DIRECTION OUTPUT ;
    USE SIGNAL ;
    PORT
      LAYER M5 ;
        RECT  34.512 17.088 34.536 17.28 ;
    END
  END o[337]
  PIN o[338]
    DIRECTION OUTPUT ;
    USE SIGNAL ;
    PORT
      LAYER M3 ;
        RECT  34.632 17.136 34.65 17.28 ;
    END
  END o[338]
  PIN o[339]
    DIRECTION OUTPUT ;
    USE SIGNAL ;
    PORT
      LAYER M5 ;
        RECT  34.704 17.088 34.728 17.28 ;
    END
  END o[339]
  PIN o[33]
    DIRECTION OUTPUT ;
    USE SIGNAL ;
    PORT
      LAYER M5 ;
        RECT  5.376 17.088 5.4 17.28 ;
    END
  END o[33]
  PIN o[340]
    DIRECTION OUTPUT ;
    USE SIGNAL ;
    PORT
      LAYER M3 ;
        RECT  34.812 17.136 34.83 17.28 ;
    END
  END o[340]
  PIN o[341]
    DIRECTION OUTPUT ;
    USE SIGNAL ;
    PORT
      LAYER M5 ;
        RECT  34.896 17.088 34.92 17.28 ;
    END
  END o[341]
  PIN o[342]
    DIRECTION OUTPUT ;
    USE SIGNAL ;
    PORT
      LAYER M3 ;
        RECT  34.992 17.136 35.01 17.28 ;
    END
  END o[342]
  PIN o[343]
    DIRECTION OUTPUT ;
    USE SIGNAL ;
    PORT
      LAYER M5 ;
        RECT  35.088 17.088 35.112 17.28 ;
    END
  END o[343]
  PIN o[344]
    DIRECTION OUTPUT ;
    USE SIGNAL ;
    PORT
      LAYER M3 ;
        RECT  35.208 17.136 35.226 17.28 ;
    END
  END o[344]
  PIN o[345]
    DIRECTION OUTPUT ;
    USE SIGNAL ;
    PORT
      LAYER M5 ;
        RECT  35.28 17.088 35.304 17.28 ;
    END
  END o[345]
  PIN o[346]
    DIRECTION OUTPUT ;
    USE SIGNAL ;
    PORT
      LAYER M3 ;
        RECT  35.388 17.136 35.406 17.28 ;
    END
  END o[346]
  PIN o[347]
    DIRECTION OUTPUT ;
    USE SIGNAL ;
    PORT
      LAYER M5 ;
        RECT  35.472 17.088 35.496 17.28 ;
    END
  END o[347]
  PIN o[348]
    DIRECTION OUTPUT ;
    USE SIGNAL ;
    PORT
      LAYER M3 ;
        RECT  35.568 17.136 35.586 17.28 ;
    END
  END o[348]
  PIN o[349]
    DIRECTION OUTPUT ;
    USE SIGNAL ;
    PORT
      LAYER M5 ;
        RECT  35.664 17.088 35.688 17.28 ;
    END
  END o[349]
  PIN o[34]
    DIRECTION OUTPUT ;
    USE SIGNAL ;
    PORT
      LAYER M3 ;
        RECT  5.472 17.136 5.49 17.28 ;
    END
  END o[34]
  PIN o[350]
    DIRECTION OUTPUT ;
    USE SIGNAL ;
    PORT
      LAYER M3 ;
        RECT  35.784 17.136 35.802 17.28 ;
    END
  END o[350]
  PIN o[351]
    DIRECTION OUTPUT ;
    USE SIGNAL ;
    PORT
      LAYER M5 ;
        RECT  35.856 17.088 35.88 17.28 ;
    END
  END o[351]
  PIN o[352]
    DIRECTION OUTPUT ;
    USE SIGNAL ;
    PORT
      LAYER M3 ;
        RECT  35.964 17.136 35.982 17.28 ;
    END
  END o[352]
  PIN o[353]
    DIRECTION OUTPUT ;
    USE SIGNAL ;
    PORT
      LAYER M5 ;
        RECT  36.048 17.088 36.072 17.28 ;
    END
  END o[353]
  PIN o[354]
    DIRECTION OUTPUT ;
    USE SIGNAL ;
    PORT
      LAYER M3 ;
        RECT  36.144 17.136 36.162 17.28 ;
    END
  END o[354]
  PIN o[355]
    DIRECTION OUTPUT ;
    USE SIGNAL ;
    PORT
      LAYER M5 ;
        RECT  36.24 17.088 36.264 17.28 ;
    END
  END o[355]
  PIN o[356]
    DIRECTION OUTPUT ;
    USE SIGNAL ;
    PORT
      LAYER M3 ;
        RECT  36.36 17.136 36.378 17.28 ;
    END
  END o[356]
  PIN o[357]
    DIRECTION OUTPUT ;
    USE SIGNAL ;
    PORT
      LAYER M5 ;
        RECT  36.432 17.088 36.456 17.28 ;
    END
  END o[357]
  PIN o[358]
    DIRECTION OUTPUT ;
    USE SIGNAL ;
    PORT
      LAYER M3 ;
        RECT  36.54 17.136 36.558 17.28 ;
    END
  END o[358]
  PIN o[359]
    DIRECTION OUTPUT ;
    USE SIGNAL ;
    PORT
      LAYER M5 ;
        RECT  36.624 17.088 36.648 17.28 ;
    END
  END o[359]
  PIN o[35]
    DIRECTION OUTPUT ;
    USE SIGNAL ;
    PORT
      LAYER M5 ;
        RECT  5.568 17.088 5.592 17.28 ;
    END
  END o[35]
  PIN o[360]
    DIRECTION OUTPUT ;
    USE SIGNAL ;
    PORT
      LAYER M3 ;
        RECT  36.72 17.136 36.738 17.28 ;
    END
  END o[360]
  PIN o[361]
    DIRECTION OUTPUT ;
    USE SIGNAL ;
    PORT
      LAYER M5 ;
        RECT  36.816 17.088 36.84 17.28 ;
    END
  END o[361]
  PIN o[362]
    DIRECTION OUTPUT ;
    USE SIGNAL ;
    PORT
      LAYER M3 ;
        RECT  36.936 17.136 36.954 17.28 ;
    END
  END o[362]
  PIN o[363]
    DIRECTION OUTPUT ;
    USE SIGNAL ;
    PORT
      LAYER M5 ;
        RECT  37.008 17.088 37.032 17.28 ;
    END
  END o[363]
  PIN o[364]
    DIRECTION OUTPUT ;
    USE SIGNAL ;
    PORT
      LAYER M3 ;
        RECT  37.116 17.136 37.134 17.28 ;
    END
  END o[364]
  PIN o[365]
    DIRECTION OUTPUT ;
    USE SIGNAL ;
    PORT
      LAYER M5 ;
        RECT  37.2 17.088 37.224 17.28 ;
    END
  END o[365]
  PIN o[366]
    DIRECTION OUTPUT ;
    USE SIGNAL ;
    PORT
      LAYER M3 ;
        RECT  37.296 17.136 37.314 17.28 ;
    END
  END o[366]
  PIN o[367]
    DIRECTION OUTPUT ;
    USE SIGNAL ;
    PORT
      LAYER M5 ;
        RECT  37.392 17.088 37.416 17.28 ;
    END
  END o[367]
  PIN o[368]
    DIRECTION OUTPUT ;
    USE SIGNAL ;
    PORT
      LAYER M3 ;
        RECT  37.512 17.136 37.53 17.28 ;
    END
  END o[368]
  PIN o[369]
    DIRECTION OUTPUT ;
    USE SIGNAL ;
    PORT
      LAYER M5 ;
        RECT  37.584 17.088 37.608 17.28 ;
    END
  END o[369]
  PIN o[36]
    DIRECTION OUTPUT ;
    USE SIGNAL ;
    PORT
      LAYER M3 ;
        RECT  5.652 17.136 5.67 17.28 ;
    END
  END o[36]
  PIN o[370]
    DIRECTION OUTPUT ;
    USE SIGNAL ;
    PORT
      LAYER M3 ;
        RECT  37.692 17.136 37.71 17.28 ;
    END
  END o[370]
  PIN o[371]
    DIRECTION OUTPUT ;
    USE SIGNAL ;
    PORT
      LAYER M5 ;
        RECT  37.776 17.088 37.8 17.28 ;
    END
  END o[371]
  PIN o[372]
    DIRECTION OUTPUT ;
    USE SIGNAL ;
    PORT
      LAYER M3 ;
        RECT  37.872 17.136 37.89 17.28 ;
    END
  END o[372]
  PIN o[373]
    DIRECTION OUTPUT ;
    USE SIGNAL ;
    PORT
      LAYER M5 ;
        RECT  37.968 17.088 37.992 17.28 ;
    END
  END o[373]
  PIN o[374]
    DIRECTION OUTPUT ;
    USE SIGNAL ;
    PORT
      LAYER M3 ;
        RECT  38.088 17.136 38.106 17.28 ;
    END
    PORT
      LAYER M3 ;
        RECT  38.016 17.148 38.142 17.213 ;
    END
  END o[374]
  PIN o[375]
    DIRECTION OUTPUT ;
    USE SIGNAL ;
    PORT
      LAYER M5 ;
        RECT  38.16 17.088 38.184 17.28 ;
    END
  END o[375]
  PIN o[376]
    DIRECTION OUTPUT ;
    USE SIGNAL ;
    PORT
      LAYER M3 ;
        RECT  38.268 17.136 38.286 17.28 ;
    END
  END o[376]
  PIN o[377]
    DIRECTION OUTPUT ;
    USE SIGNAL ;
    PORT
      LAYER M5 ;
        RECT  38.352 17.088 38.376 17.28 ;
    END
  END o[377]
  PIN o[378]
    DIRECTION OUTPUT ;
    USE SIGNAL ;
    PORT
      LAYER M3 ;
        RECT  38.448 17.136 38.466 17.28 ;
    END
  END o[378]
  PIN o[379]
    DIRECTION OUTPUT ;
    USE SIGNAL ;
    PORT
      LAYER M5 ;
        RECT  38.544 17.088 38.568 17.28 ;
    END
  END o[379]
  PIN o[37]
    DIRECTION OUTPUT ;
    USE SIGNAL ;
    PORT
      LAYER M5 ;
        RECT  5.76 17.088 5.784 17.28 ;
    END
  END o[37]
  PIN o[380]
    DIRECTION OUTPUT ;
    USE SIGNAL ;
    PORT
      LAYER M3 ;
        RECT  38.664 17.136 38.682 17.28 ;
    END
  END o[380]
  PIN o[381]
    DIRECTION OUTPUT ;
    USE SIGNAL ;
    PORT
      LAYER M5 ;
        RECT  38.736 17.088 38.76 17.28 ;
    END
  END o[381]
  PIN o[382]
    DIRECTION OUTPUT ;
    USE SIGNAL ;
    PORT
      LAYER M3 ;
        RECT  38.844 17.136 38.862 17.28 ;
    END
  END o[382]
  PIN o[383]
    DIRECTION OUTPUT ;
    USE SIGNAL ;
    PORT
      LAYER M5 ;
        RECT  38.928 17.088 38.952 17.28 ;
    END
  END o[383]
  PIN o[384]
    DIRECTION OUTPUT ;
    USE SIGNAL ;
    PORT
      LAYER M3 ;
        RECT  39.024 17.136 39.042 17.28 ;
    END
  END o[384]
  PIN o[385]
    DIRECTION OUTPUT ;
    USE SIGNAL ;
    PORT
      LAYER M5 ;
        RECT  39.12 17.088 39.144 17.28 ;
    END
  END o[385]
  PIN o[386]
    DIRECTION OUTPUT ;
    USE SIGNAL ;
    PORT
      LAYER M3 ;
        RECT  39.24 17.136 39.258 17.28 ;
    END
  END o[386]
  PIN o[387]
    DIRECTION OUTPUT ;
    USE SIGNAL ;
    PORT
      LAYER M5 ;
        RECT  39.312 17.088 39.336 17.28 ;
    END
  END o[387]
  PIN o[388]
    DIRECTION OUTPUT ;
    USE SIGNAL ;
    PORT
      LAYER M3 ;
        RECT  39.42 17.136 39.438 17.28 ;
    END
  END o[388]
  PIN o[389]
    DIRECTION OUTPUT ;
    USE SIGNAL ;
    PORT
      LAYER M5 ;
        RECT  39.504 17.088 39.528 17.28 ;
    END
  END o[389]
  PIN o[38]
    DIRECTION OUTPUT ;
    USE SIGNAL ;
    PORT
      LAYER M3 ;
        RECT  5.832 17.136 5.85 17.28 ;
    END
  END o[38]
  PIN o[390]
    DIRECTION OUTPUT ;
    USE SIGNAL ;
    PORT
      LAYER M3 ;
        RECT  39.6 17.136 39.618 17.28 ;
    END
  END o[390]
  PIN o[391]
    DIRECTION OUTPUT ;
    USE SIGNAL ;
    PORT
      LAYER M5 ;
        RECT  39.696 17.088 39.72 17.28 ;
    END
  END o[391]
  PIN o[392]
    DIRECTION OUTPUT ;
    USE SIGNAL ;
    PORT
      LAYER M3 ;
        RECT  39.78 17.136 39.798 17.28 ;
    END
  END o[392]
  PIN o[393]
    DIRECTION OUTPUT ;
    USE SIGNAL ;
    PORT
      LAYER M5 ;
        RECT  39.888 17.088 39.912 17.28 ;
    END
  END o[393]
  PIN o[394]
    DIRECTION OUTPUT ;
    USE SIGNAL ;
    PORT
      LAYER M3 ;
        RECT  39.996 17.136 40.014 17.28 ;
    END
  END o[394]
  PIN o[395]
    DIRECTION OUTPUT ;
    USE SIGNAL ;
    PORT
      LAYER M5 ;
        RECT  40.08 17.088 40.104 17.28 ;
    END
  END o[395]
  PIN o[396]
    DIRECTION OUTPUT ;
    USE SIGNAL ;
    PORT
      LAYER M3 ;
        RECT  40.176 17.136 40.194 17.28 ;
    END
  END o[396]
  PIN o[397]
    DIRECTION OUTPUT ;
    USE SIGNAL ;
    PORT
      LAYER M5 ;
        RECT  40.272 17.088 40.296 17.28 ;
    END
  END o[397]
  PIN o[398]
    DIRECTION OUTPUT ;
    USE SIGNAL ;
    PORT
      LAYER M3 ;
        RECT  40.356 17.136 40.374 17.28 ;
    END
  END o[398]
  PIN o[399]
    DIRECTION OUTPUT ;
    USE SIGNAL ;
    PORT
      LAYER M5 ;
        RECT  40.464 17.088 40.488 17.28 ;
    END
  END o[399]
  PIN o[39]
    DIRECTION OUTPUT ;
    USE SIGNAL ;
    PORT
      LAYER M5 ;
        RECT  5.952 17.088 5.976 17.28 ;
    END
  END o[39]
  PIN o[3]
    DIRECTION OUTPUT ;
    USE SIGNAL ;
    PORT
      LAYER M5 ;
        RECT  2.496 17.088 2.52 17.28 ;
    END
  END o[3]
  PIN o[400]
    DIRECTION OUTPUT ;
    USE SIGNAL ;
    PORT
      LAYER M3 ;
        RECT  40.572 17.136 40.59 17.28 ;
    END
  END o[400]
  PIN o[401]
    DIRECTION OUTPUT ;
    USE SIGNAL ;
    PORT
      LAYER M5 ;
        RECT  40.656 17.088 40.68 17.28 ;
    END
  END o[401]
  PIN o[402]
    DIRECTION OUTPUT ;
    USE SIGNAL ;
    PORT
      LAYER M3 ;
        RECT  40.752 17.136 40.77 17.28 ;
    END
  END o[402]
  PIN o[403]
    DIRECTION OUTPUT ;
    USE SIGNAL ;
    PORT
      LAYER M5 ;
        RECT  40.848 17.088 40.872 17.28 ;
    END
  END o[403]
  PIN o[404]
    DIRECTION OUTPUT ;
    USE SIGNAL ;
    PORT
      LAYER M3 ;
        RECT  40.932 17.136 40.95 17.28 ;
    END
  END o[404]
  PIN o[405]
    DIRECTION OUTPUT ;
    USE SIGNAL ;
    PORT
      LAYER M5 ;
        RECT  41.04 17.088 41.064 17.28 ;
    END
  END o[405]
  PIN o[406]
    DIRECTION OUTPUT ;
    USE SIGNAL ;
    PORT
      LAYER M3 ;
        RECT  41.148 17.136 41.166 17.28 ;
    END
  END o[406]
  PIN o[407]
    DIRECTION OUTPUT ;
    USE SIGNAL ;
    PORT
      LAYER M5 ;
        RECT  41.232 17.088 41.256 17.28 ;
    END
  END o[407]
  PIN o[408]
    DIRECTION OUTPUT ;
    USE SIGNAL ;
    PORT
      LAYER M3 ;
        RECT  41.328 17.136 41.346 17.28 ;
    END
  END o[408]
  PIN o[409]
    DIRECTION OUTPUT ;
    USE SIGNAL ;
    PORT
      LAYER M5 ;
        RECT  41.424 17.088 41.448 17.28 ;
    END
  END o[409]
  PIN o[40]
    DIRECTION OUTPUT ;
    USE SIGNAL ;
    PORT
      LAYER M3 ;
        RECT  6.048 17.136 6.066 17.28 ;
    END
  END o[40]
  PIN o[410]
    DIRECTION OUTPUT ;
    USE SIGNAL ;
    PORT
      LAYER M3 ;
        RECT  41.508 17.136 41.526 17.28 ;
    END
  END o[410]
  PIN o[411]
    DIRECTION OUTPUT ;
    USE SIGNAL ;
    PORT
      LAYER M5 ;
        RECT  41.616 17.088 41.64 17.28 ;
    END
  END o[411]
  PIN o[412]
    DIRECTION OUTPUT ;
    USE SIGNAL ;
    PORT
      LAYER M3 ;
        RECT  41.724 17.136 41.742 17.28 ;
    END
  END o[412]
  PIN o[413]
    DIRECTION OUTPUT ;
    USE SIGNAL ;
    PORT
      LAYER M5 ;
        RECT  41.808 17.088 41.832 17.28 ;
    END
  END o[413]
  PIN o[414]
    DIRECTION OUTPUT ;
    USE SIGNAL ;
    PORT
      LAYER M3 ;
        RECT  41.904 17.136 41.922 17.28 ;
    END
  END o[414]
  PIN o[415]
    DIRECTION OUTPUT ;
    USE SIGNAL ;
    PORT
      LAYER M5 ;
        RECT  42 17.088 42.024 17.28 ;
    END
  END o[415]
  PIN o[416]
    DIRECTION OUTPUT ;
    USE SIGNAL ;
    PORT
      LAYER M3 ;
        RECT  42.084 17.136 42.102 17.28 ;
    END
    PORT
      LAYER M3 ;
        RECT  42.012 17.148 42.138 17.213 ;
    END
  END o[416]
  PIN o[417]
    DIRECTION OUTPUT ;
    USE SIGNAL ;
    PORT
      LAYER M5 ;
        RECT  42.192 17.088 42.216 17.28 ;
    END
  END o[417]
  PIN o[418]
    DIRECTION OUTPUT ;
    USE SIGNAL ;
    PORT
      LAYER M3 ;
        RECT  42.3 17.136 42.318 17.28 ;
    END
  END o[418]
  PIN o[419]
    DIRECTION OUTPUT ;
    USE SIGNAL ;
    PORT
      LAYER M5 ;
        RECT  42.384 17.088 42.408 17.28 ;
    END
  END o[419]
  PIN o[41]
    DIRECTION OUTPUT ;
    USE SIGNAL ;
    PORT
      LAYER M5 ;
        RECT  6.144 17.088 6.168 17.28 ;
    END
  END o[41]
  PIN o[420]
    DIRECTION OUTPUT ;
    USE SIGNAL ;
    PORT
      LAYER M3 ;
        RECT  42.48 17.136 42.498 17.28 ;
    END
  END o[420]
  PIN o[421]
    DIRECTION OUTPUT ;
    USE SIGNAL ;
    PORT
      LAYER M5 ;
        RECT  42.576 17.088 42.6 17.28 ;
    END
  END o[421]
  PIN o[422]
    DIRECTION OUTPUT ;
    USE SIGNAL ;
    PORT
      LAYER M3 ;
        RECT  42.66 17.136 42.678 17.28 ;
    END
  END o[422]
  PIN o[423]
    DIRECTION OUTPUT ;
    USE SIGNAL ;
    PORT
      LAYER M5 ;
        RECT  42.768 17.088 42.792 17.28 ;
    END
  END o[423]
  PIN o[424]
    DIRECTION OUTPUT ;
    USE SIGNAL ;
    PORT
      LAYER M3 ;
        RECT  42.876 17.136 42.894 17.28 ;
    END
  END o[424]
  PIN o[425]
    DIRECTION OUTPUT ;
    USE SIGNAL ;
    PORT
      LAYER M5 ;
        RECT  42.96 17.088 42.984 17.28 ;
    END
  END o[425]
  PIN o[426]
    DIRECTION OUTPUT ;
    USE SIGNAL ;
    PORT
      LAYER M3 ;
        RECT  43.056 17.136 43.074 17.28 ;
    END
  END o[426]
  PIN o[427]
    DIRECTION OUTPUT ;
    USE SIGNAL ;
    PORT
      LAYER M5 ;
        RECT  43.152 17.088 43.176 17.28 ;
    END
  END o[427]
  PIN o[428]
    DIRECTION OUTPUT ;
    USE SIGNAL ;
    PORT
      LAYER M3 ;
        RECT  43.236 17.136 43.254 17.28 ;
    END
  END o[428]
  PIN o[429]
    DIRECTION OUTPUT ;
    USE SIGNAL ;
    PORT
      LAYER M5 ;
        RECT  43.344 17.088 43.368 17.28 ;
    END
  END o[429]
  PIN o[42]
    DIRECTION OUTPUT ;
    USE SIGNAL ;
    PORT
      LAYER M3 ;
        RECT  6.228 17.136 6.246 17.28 ;
    END
  END o[42]
  PIN o[430]
    DIRECTION OUTPUT ;
    USE SIGNAL ;
    PORT
      LAYER M3 ;
        RECT  43.452 17.136 43.47 17.28 ;
    END
  END o[430]
  PIN o[431]
    DIRECTION OUTPUT ;
    USE SIGNAL ;
    PORT
      LAYER M5 ;
        RECT  43.536 17.088 43.56 17.28 ;
    END
  END o[431]
  PIN o[432]
    DIRECTION OUTPUT ;
    USE SIGNAL ;
    PORT
      LAYER M3 ;
        RECT  43.632 17.136 43.65 17.28 ;
    END
  END o[432]
  PIN o[433]
    DIRECTION OUTPUT ;
    USE SIGNAL ;
    PORT
      LAYER M5 ;
        RECT  43.728 17.088 43.752 17.28 ;
    END
  END o[433]
  PIN o[434]
    DIRECTION OUTPUT ;
    USE SIGNAL ;
    PORT
      LAYER M3 ;
        RECT  43.812 17.136 43.83 17.28 ;
    END
  END o[434]
  PIN o[435]
    DIRECTION OUTPUT ;
    USE SIGNAL ;
    PORT
      LAYER M5 ;
        RECT  43.92 17.088 43.944 17.28 ;
    END
  END o[435]
  PIN o[436]
    DIRECTION OUTPUT ;
    USE SIGNAL ;
    PORT
      LAYER M3 ;
        RECT  44.028 17.136 44.046 17.28 ;
    END
  END o[436]
  PIN o[437]
    DIRECTION OUTPUT ;
    USE SIGNAL ;
    PORT
      LAYER M5 ;
        RECT  44.112 17.088 44.136 17.28 ;
    END
  END o[437]
  PIN o[438]
    DIRECTION OUTPUT ;
    USE SIGNAL ;
    PORT
      LAYER M3 ;
        RECT  44.208 17.136 44.226 17.28 ;
    END
  END o[438]
  PIN o[439]
    DIRECTION OUTPUT ;
    USE SIGNAL ;
    PORT
      LAYER M5 ;
        RECT  44.304 17.088 44.328 17.28 ;
    END
  END o[439]
  PIN o[43]
    DIRECTION OUTPUT ;
    USE SIGNAL ;
    PORT
      LAYER M5 ;
        RECT  6.336 17.088 6.36 17.28 ;
    END
  END o[43]
  PIN o[440]
    DIRECTION OUTPUT ;
    USE SIGNAL ;
    PORT
      LAYER M3 ;
        RECT  44.388 17.136 44.406 17.28 ;
    END
  END o[440]
  PIN o[441]
    DIRECTION OUTPUT ;
    USE SIGNAL ;
    PORT
      LAYER M5 ;
        RECT  44.496 17.088 44.52 17.28 ;
    END
  END o[441]
  PIN o[442]
    DIRECTION OUTPUT ;
    USE SIGNAL ;
    PORT
      LAYER M3 ;
        RECT  44.604 17.136 44.622 17.28 ;
    END
  END o[442]
  PIN o[443]
    DIRECTION OUTPUT ;
    USE SIGNAL ;
    PORT
      LAYER M5 ;
        RECT  44.688 17.088 44.712 17.28 ;
    END
  END o[443]
  PIN o[444]
    DIRECTION OUTPUT ;
    USE SIGNAL ;
    PORT
      LAYER M3 ;
        RECT  44.784 17.136 44.802 17.28 ;
    END
  END o[444]
  PIN o[445]
    DIRECTION OUTPUT ;
    USE SIGNAL ;
    PORT
      LAYER M5 ;
        RECT  44.88 17.088 44.904 17.28 ;
    END
  END o[445]
  PIN o[446]
    DIRECTION OUTPUT ;
    USE SIGNAL ;
    PORT
      LAYER M3 ;
        RECT  44.964 17.136 44.982 17.28 ;
    END
  END o[446]
  PIN o[447]
    DIRECTION OUTPUT ;
    USE SIGNAL ;
    PORT
      LAYER M5 ;
        RECT  45.072 17.088 45.096 17.28 ;
    END
  END o[447]
  PIN o[448]
    DIRECTION OUTPUT ;
    USE SIGNAL ;
    PORT
      LAYER M3 ;
        RECT  45.18 17.136 45.198 17.28 ;
    END
  END o[448]
  PIN o[449]
    DIRECTION OUTPUT ;
    USE SIGNAL ;
    PORT
      LAYER M5 ;
        RECT  45.264 17.088 45.288 17.28 ;
    END
  END o[449]
  PIN o[44]
    DIRECTION OUTPUT ;
    USE SIGNAL ;
    PORT
      LAYER M3 ;
        RECT  6.408 17.136 6.426 17.28 ;
    END
  END o[44]
  PIN o[450]
    DIRECTION OUTPUT ;
    USE SIGNAL ;
    PORT
      LAYER M3 ;
        RECT  45.36 17.136 45.378 17.28 ;
    END
  END o[450]
  PIN o[451]
    DIRECTION OUTPUT ;
    USE SIGNAL ;
    PORT
      LAYER M5 ;
        RECT  45.456 17.088 45.48 17.28 ;
    END
  END o[451]
  PIN o[452]
    DIRECTION OUTPUT ;
    USE SIGNAL ;
    PORT
      LAYER M3 ;
        RECT  45.54 17.136 45.558 17.28 ;
    END
  END o[452]
  PIN o[453]
    DIRECTION OUTPUT ;
    USE SIGNAL ;
    PORT
      LAYER M5 ;
        RECT  45.648 17.088 45.672 17.28 ;
    END
  END o[453]
  PIN o[454]
    DIRECTION OUTPUT ;
    USE SIGNAL ;
    PORT
      LAYER M3 ;
        RECT  45.756 17.136 45.774 17.28 ;
    END
  END o[454]
  PIN o[455]
    DIRECTION OUTPUT ;
    USE SIGNAL ;
    PORT
      LAYER M5 ;
        RECT  45.84 17.088 45.864 17.28 ;
    END
  END o[455]
  PIN o[456]
    DIRECTION OUTPUT ;
    USE SIGNAL ;
    PORT
      LAYER M3 ;
        RECT  45.936 17.136 45.954 17.28 ;
    END
  END o[456]
  PIN o[457]
    DIRECTION OUTPUT ;
    USE SIGNAL ;
    PORT
      LAYER M5 ;
        RECT  46.032 17.088 46.056 17.28 ;
    END
  END o[457]
  PIN o[458]
    DIRECTION OUTPUT ;
    USE SIGNAL ;
    PORT
      LAYER M3 ;
        RECT  46.116 17.136 46.134 17.28 ;
    END
  END o[458]
  PIN o[459]
    DIRECTION OUTPUT ;
    USE SIGNAL ;
    PORT
      LAYER M5 ;
        RECT  46.224 17.088 46.248 17.28 ;
    END
  END o[459]
  PIN o[45]
    DIRECTION OUTPUT ;
    USE SIGNAL ;
    PORT
      LAYER M5 ;
        RECT  6.528 17.088 6.552 17.28 ;
    END
  END o[45]
  PIN o[460]
    DIRECTION OUTPUT ;
    USE SIGNAL ;
    PORT
      LAYER M3 ;
        RECT  46.332 17.136 46.35 17.28 ;
    END
  END o[460]
  PIN o[461]
    DIRECTION OUTPUT ;
    USE SIGNAL ;
    PORT
      LAYER M5 ;
        RECT  46.416 17.088 46.44 17.28 ;
    END
  END o[461]
  PIN o[462]
    DIRECTION OUTPUT ;
    USE SIGNAL ;
    PORT
      LAYER M3 ;
        RECT  46.512 17.136 46.53 17.28 ;
    END
  END o[462]
  PIN o[463]
    DIRECTION OUTPUT ;
    USE SIGNAL ;
    PORT
      LAYER M5 ;
        RECT  46.608 17.088 46.632 17.28 ;
    END
  END o[463]
  PIN o[464]
    DIRECTION OUTPUT ;
    USE SIGNAL ;
    PORT
      LAYER M3 ;
        RECT  46.692 17.136 46.71 17.28 ;
    END
  END o[464]
  PIN o[465]
    DIRECTION OUTPUT ;
    USE SIGNAL ;
    PORT
      LAYER M5 ;
        RECT  46.8 17.088 46.824 17.28 ;
    END
  END o[465]
  PIN o[466]
    DIRECTION OUTPUT ;
    USE SIGNAL ;
    PORT
      LAYER M3 ;
        RECT  46.908 17.136 46.926 17.28 ;
    END
  END o[466]
  PIN o[467]
    DIRECTION OUTPUT ;
    USE SIGNAL ;
    PORT
      LAYER M5 ;
        RECT  46.992 17.088 47.016 17.28 ;
    END
  END o[467]
  PIN o[468]
    DIRECTION OUTPUT ;
    USE SIGNAL ;
    PORT
      LAYER M3 ;
        RECT  47.088 17.136 47.106 17.28 ;
    END
  END o[468]
  PIN o[469]
    DIRECTION OUTPUT ;
    USE SIGNAL ;
    PORT
      LAYER M5 ;
        RECT  47.184 17.088 47.208 17.28 ;
    END
  END o[469]
  PIN o[46]
    DIRECTION OUTPUT ;
    USE SIGNAL ;
    PORT
      LAYER M3 ;
        RECT  6.624 17.136 6.642 17.28 ;
    END
  END o[46]
  PIN o[470]
    DIRECTION OUTPUT ;
    USE SIGNAL ;
    PORT
      LAYER M3 ;
        RECT  47.268 17.136 47.286 17.28 ;
    END
  END o[470]
  PIN o[471]
    DIRECTION OUTPUT ;
    USE SIGNAL ;
    PORT
      LAYER M5 ;
        RECT  47.376 17.088 47.4 17.28 ;
    END
  END o[471]
  PIN o[472]
    DIRECTION OUTPUT ;
    USE SIGNAL ;
    PORT
      LAYER M3 ;
        RECT  47.484 17.136 47.502 17.28 ;
    END
  END o[472]
  PIN o[473]
    DIRECTION OUTPUT ;
    USE SIGNAL ;
    PORT
      LAYER M5 ;
        RECT  47.568 17.088 47.592 17.28 ;
    END
  END o[473]
  PIN o[474]
    DIRECTION OUTPUT ;
    USE SIGNAL ;
    PORT
      LAYER M3 ;
        RECT  47.664 17.136 47.682 17.28 ;
    END
  END o[474]
  PIN o[475]
    DIRECTION OUTPUT ;
    USE SIGNAL ;
    PORT
      LAYER M5 ;
        RECT  47.76 17.088 47.784 17.28 ;
    END
  END o[475]
  PIN o[476]
    DIRECTION OUTPUT ;
    USE SIGNAL ;
    PORT
      LAYER M3 ;
        RECT  47.844 17.136 47.862 17.28 ;
    END
  END o[476]
  PIN o[477]
    DIRECTION OUTPUT ;
    USE SIGNAL ;
    PORT
      LAYER M5 ;
        RECT  47.952 17.088 47.976 17.28 ;
    END
  END o[477]
  PIN o[478]
    DIRECTION OUTPUT ;
    USE SIGNAL ;
    PORT
      LAYER M3 ;
        RECT  48.06 17.136 48.078 17.28 ;
    END
  END o[478]
  PIN o[479]
    DIRECTION OUTPUT ;
    USE SIGNAL ;
    PORT
      LAYER M5 ;
        RECT  48.144 17.088 48.168 17.28 ;
    END
  END o[479]
  PIN o[47]
    DIRECTION OUTPUT ;
    USE SIGNAL ;
    PORT
      LAYER M5 ;
        RECT  6.72 17.088 6.744 17.28 ;
    END
  END o[47]
  PIN o[480]
    DIRECTION OUTPUT ;
    USE SIGNAL ;
    PORT
      LAYER M3 ;
        RECT  48.24 17.136 48.258 17.28 ;
    END
  END o[480]
  PIN o[481]
    DIRECTION OUTPUT ;
    USE SIGNAL ;
    PORT
      LAYER M5 ;
        RECT  48.336 17.088 48.36 17.28 ;
    END
  END o[481]
  PIN o[482]
    DIRECTION OUTPUT ;
    USE SIGNAL ;
    PORT
      LAYER M3 ;
        RECT  48.42 17.136 48.438 17.28 ;
    END
  END o[482]
  PIN o[483]
    DIRECTION OUTPUT ;
    USE SIGNAL ;
    PORT
      LAYER M5 ;
        RECT  48.528 17.088 48.552 17.28 ;
    END
  END o[483]
  PIN o[484]
    DIRECTION OUTPUT ;
    USE SIGNAL ;
    PORT
      LAYER M3 ;
        RECT  48.636 17.136 48.654 17.28 ;
    END
  END o[484]
  PIN o[485]
    DIRECTION OUTPUT ;
    USE SIGNAL ;
    PORT
      LAYER M5 ;
        RECT  48.72 17.088 48.744 17.28 ;
    END
  END o[485]
  PIN o[486]
    DIRECTION OUTPUT ;
    USE SIGNAL ;
    PORT
      LAYER M3 ;
        RECT  48.816 17.136 48.834 17.28 ;
    END
  END o[486]
  PIN o[487]
    DIRECTION OUTPUT ;
    USE SIGNAL ;
    PORT
      LAYER M5 ;
        RECT  48.912 17.088 48.936 17.28 ;
    END
  END o[487]
  PIN o[488]
    DIRECTION OUTPUT ;
    USE SIGNAL ;
    PORT
      LAYER M3 ;
        RECT  48.996 17.136 49.014 17.28 ;
    END
  END o[488]
  PIN o[489]
    DIRECTION OUTPUT ;
    USE SIGNAL ;
    PORT
      LAYER M5 ;
        RECT  49.104 17.088 49.128 17.28 ;
    END
  END o[489]
  PIN o[48]
    DIRECTION OUTPUT ;
    USE SIGNAL ;
    PORT
      LAYER M3 ;
        RECT  6.804 17.136 6.822 17.28 ;
    END
  END o[48]
  PIN o[490]
    DIRECTION OUTPUT ;
    USE SIGNAL ;
    PORT
      LAYER M3 ;
        RECT  49.212 17.136 49.23 17.28 ;
    END
  END o[490]
  PIN o[491]
    DIRECTION OUTPUT ;
    USE SIGNAL ;
    PORT
      LAYER M5 ;
        RECT  49.296 17.088 49.32 17.28 ;
    END
  END o[491]
  PIN o[492]
    DIRECTION OUTPUT ;
    USE SIGNAL ;
    PORT
      LAYER M3 ;
        RECT  49.392 17.136 49.41 17.28 ;
    END
  END o[492]
  PIN o[493]
    DIRECTION OUTPUT ;
    USE SIGNAL ;
    PORT
      LAYER M5 ;
        RECT  49.488 17.088 49.512 17.28 ;
    END
  END o[493]
  PIN o[494]
    DIRECTION OUTPUT ;
    USE SIGNAL ;
    PORT
      LAYER M3 ;
        RECT  49.572 17.136 49.59 17.28 ;
    END
  END o[494]
  PIN o[495]
    DIRECTION OUTPUT ;
    USE SIGNAL ;
    PORT
      LAYER M5 ;
        RECT  49.68 17.088 49.704 17.28 ;
    END
  END o[495]
  PIN o[496]
    DIRECTION OUTPUT ;
    USE SIGNAL ;
    PORT
      LAYER M3 ;
        RECT  49.788 17.136 49.806 17.28 ;
    END
  END o[496]
  PIN o[497]
    DIRECTION OUTPUT ;
    USE SIGNAL ;
    PORT
      LAYER M5 ;
        RECT  49.872 17.088 49.896 17.28 ;
    END
  END o[497]
  PIN o[498]
    DIRECTION OUTPUT ;
    USE SIGNAL ;
    PORT
      LAYER M3 ;
        RECT  49.968 17.136 49.986 17.28 ;
    END
  END o[498]
  PIN o[499]
    DIRECTION OUTPUT ;
    USE SIGNAL ;
    PORT
      LAYER M5 ;
        RECT  50.064 17.088 50.088 17.28 ;
    END
  END o[499]
  PIN o[49]
    DIRECTION OUTPUT ;
    USE SIGNAL ;
    PORT
      LAYER M5 ;
        RECT  6.912 17.088 6.936 17.28 ;
    END
  END o[49]
  PIN o[4]
    DIRECTION OUTPUT ;
    USE SIGNAL ;
    PORT
      LAYER M3 ;
        RECT  2.592 17.136 2.61 17.28 ;
    END
  END o[4]
  PIN o[500]
    DIRECTION OUTPUT ;
    USE SIGNAL ;
    PORT
      LAYER M3 ;
        RECT  50.148 17.136 50.166 17.28 ;
    END
  END o[500]
  PIN o[501]
    DIRECTION OUTPUT ;
    USE SIGNAL ;
    PORT
      LAYER M5 ;
        RECT  50.256 17.088 50.28 17.28 ;
    END
  END o[501]
  PIN o[502]
    DIRECTION OUTPUT ;
    USE SIGNAL ;
    PORT
      LAYER M3 ;
        RECT  50.364 17.136 50.382 17.28 ;
    END
  END o[502]
  PIN o[503]
    DIRECTION OUTPUT ;
    USE SIGNAL ;
    PORT
      LAYER M5 ;
        RECT  50.448 17.088 50.472 17.28 ;
    END
  END o[503]
  PIN o[504]
    DIRECTION OUTPUT ;
    USE SIGNAL ;
    PORT
      LAYER M3 ;
        RECT  50.544 17.136 50.562 17.28 ;
    END
  END o[504]
  PIN o[505]
    DIRECTION OUTPUT ;
    USE SIGNAL ;
    PORT
      LAYER M5 ;
        RECT  50.64 17.088 50.664 17.28 ;
    END
  END o[505]
  PIN o[506]
    DIRECTION OUTPUT ;
    USE SIGNAL ;
    PORT
      LAYER M3 ;
        RECT  50.724 17.136 50.742 17.28 ;
    END
  END o[506]
  PIN o[507]
    DIRECTION OUTPUT ;
    USE SIGNAL ;
    PORT
      LAYER M5 ;
        RECT  50.832 17.088 50.856 17.28 ;
    END
  END o[507]
  PIN o[508]
    DIRECTION OUTPUT ;
    USE SIGNAL ;
    PORT
      LAYER M3 ;
        RECT  50.94 17.136 50.958 17.28 ;
    END
  END o[508]
  PIN o[509]
    DIRECTION OUTPUT ;
    USE SIGNAL ;
    PORT
      LAYER M5 ;
        RECT  51.024 17.088 51.048 17.28 ;
    END
  END o[509]
  PIN o[50]
    DIRECTION OUTPUT ;
    USE SIGNAL ;
    PORT
      LAYER M3 ;
        RECT  6.984 17.136 7.002 17.28 ;
    END
  END o[50]
  PIN o[510]
    DIRECTION OUTPUT ;
    USE SIGNAL ;
    PORT
      LAYER M3 ;
        RECT  51.12 17.136 51.138 17.28 ;
    END
  END o[510]
  PIN o[511]
    DIRECTION OUTPUT ;
    USE SIGNAL ;
    PORT
      LAYER M5 ;
        RECT  51.216 17.088 51.24 17.28 ;
    END
  END o[511]
  PIN o[512]
    DIRECTION OUTPUT ;
    USE SIGNAL ;
    PORT
      LAYER M3 ;
        RECT  51.3 17.136 51.318 17.28 ;
    END
  END o[512]
  PIN o[513]
    DIRECTION OUTPUT ;
    USE SIGNAL ;
    PORT
      LAYER M5 ;
        RECT  51.408 17.088 51.432 17.28 ;
    END
  END o[513]
  PIN o[514]
    DIRECTION OUTPUT ;
    USE SIGNAL ;
    PORT
      LAYER M3 ;
        RECT  51.516 17.136 51.534 17.28 ;
    END
  END o[514]
  PIN o[515]
    DIRECTION OUTPUT ;
    USE SIGNAL ;
    PORT
      LAYER M5 ;
        RECT  51.6 17.088 51.624 17.28 ;
    END
  END o[515]
  PIN o[516]
    DIRECTION OUTPUT ;
    USE SIGNAL ;
    PORT
      LAYER M3 ;
        RECT  51.696 17.136 51.714 17.28 ;
    END
  END o[516]
  PIN o[517]
    DIRECTION OUTPUT ;
    USE SIGNAL ;
    PORT
      LAYER M5 ;
        RECT  51.792 17.088 51.816 17.28 ;
    END
  END o[517]
  PIN o[518]
    DIRECTION OUTPUT ;
    USE SIGNAL ;
    PORT
      LAYER M3 ;
        RECT  51.876 17.136 51.894 17.28 ;
    END
  END o[518]
  PIN o[519]
    DIRECTION OUTPUT ;
    USE SIGNAL ;
    PORT
      LAYER M5 ;
        RECT  51.984 17.088 52.008 17.28 ;
    END
  END o[519]
  PIN o[51]
    DIRECTION OUTPUT ;
    USE SIGNAL ;
    PORT
      LAYER M5 ;
        RECT  7.104 17.088 7.128 17.28 ;
    END
  END o[51]
  PIN o[520]
    DIRECTION OUTPUT ;
    USE SIGNAL ;
    PORT
      LAYER M3 ;
        RECT  52.092 17.136 52.11 17.28 ;
    END
  END o[520]
  PIN o[521]
    DIRECTION OUTPUT ;
    USE SIGNAL ;
    PORT
      LAYER M5 ;
        RECT  52.176 17.088 52.2 17.28 ;
    END
  END o[521]
  PIN o[522]
    DIRECTION OUTPUT ;
    USE SIGNAL ;
    PORT
      LAYER M3 ;
        RECT  52.272 17.136 52.29 17.28 ;
    END
  END o[522]
  PIN o[523]
    DIRECTION OUTPUT ;
    USE SIGNAL ;
    PORT
      LAYER M5 ;
        RECT  52.368 17.088 52.392 17.28 ;
    END
  END o[523]
  PIN o[524]
    DIRECTION OUTPUT ;
    USE SIGNAL ;
    PORT
      LAYER M3 ;
        RECT  52.452 17.136 52.47 17.28 ;
    END
  END o[524]
  PIN o[525]
    DIRECTION OUTPUT ;
    USE SIGNAL ;
    PORT
      LAYER M5 ;
        RECT  52.56 17.088 52.584 17.28 ;
    END
  END o[525]
  PIN o[526]
    DIRECTION OUTPUT ;
    USE SIGNAL ;
    PORT
      LAYER M3 ;
        RECT  52.668 17.136 52.686 17.28 ;
    END
  END o[526]
  PIN o[527]
    DIRECTION OUTPUT ;
    USE SIGNAL ;
    PORT
      LAYER M5 ;
        RECT  52.752 17.088 52.776 17.28 ;
    END
  END o[527]
  PIN o[528]
    DIRECTION OUTPUT ;
    USE SIGNAL ;
    PORT
      LAYER M3 ;
        RECT  52.848 17.136 52.866 17.28 ;
    END
  END o[528]
  PIN o[529]
    DIRECTION OUTPUT ;
    USE SIGNAL ;
    PORT
      LAYER M5 ;
        RECT  52.944 17.088 52.968 17.28 ;
    END
  END o[529]
  PIN o[52]
    DIRECTION OUTPUT ;
    USE SIGNAL ;
    PORT
      LAYER M3 ;
        RECT  7.2 17.136 7.218 17.28 ;
    END
  END o[52]
  PIN o[530]
    DIRECTION OUTPUT ;
    USE SIGNAL ;
    PORT
      LAYER M3 ;
        RECT  53.028 17.136 53.046 17.28 ;
    END
  END o[530]
  PIN o[531]
    DIRECTION OUTPUT ;
    USE SIGNAL ;
    PORT
      LAYER M5 ;
        RECT  53.136 17.088 53.16 17.28 ;
    END
  END o[531]
  PIN o[532]
    DIRECTION OUTPUT ;
    USE SIGNAL ;
    PORT
      LAYER M3 ;
        RECT  53.208 17.136 53.226 17.28 ;
    END
    PORT
      LAYER M3 ;
        RECT  53.172 17.148 53.298 17.213 ;
    END
  END o[532]
  PIN o[533]
    DIRECTION OUTPUT ;
    USE SIGNAL ;
    PORT
      LAYER M5 ;
        RECT  53.328 17.088 53.352 17.28 ;
    END
  END o[533]
  PIN o[534]
    DIRECTION OUTPUT ;
    USE SIGNAL ;
    PORT
      LAYER M3 ;
        RECT  53.424 17.136 53.442 17.28 ;
    END
  END o[534]
  PIN o[535]
    DIRECTION OUTPUT ;
    USE SIGNAL ;
    PORT
      LAYER M5 ;
        RECT  53.52 17.088 53.544 17.28 ;
    END
  END o[535]
  PIN o[536]
    DIRECTION OUTPUT ;
    USE SIGNAL ;
    PORT
      LAYER M3 ;
        RECT  53.604 17.136 53.622 17.28 ;
    END
  END o[536]
  PIN o[537]
    DIRECTION OUTPUT ;
    USE SIGNAL ;
    PORT
      LAYER M5 ;
        RECT  53.712 17.088 53.736 17.28 ;
    END
  END o[537]
  PIN o[538]
    DIRECTION OUTPUT ;
    USE SIGNAL ;
    PORT
      LAYER M3 ;
        RECT  53.784 17.136 53.802 17.28 ;
    END
  END o[538]
  PIN o[539]
    DIRECTION OUTPUT ;
    USE SIGNAL ;
    PORT
      LAYER M5 ;
        RECT  53.904 17.088 53.928 17.28 ;
    END
  END o[539]
  PIN o[53]
    DIRECTION OUTPUT ;
    USE SIGNAL ;
    PORT
      LAYER M5 ;
        RECT  7.296 17.088 7.32 17.28 ;
    END
  END o[53]
  PIN o[540]
    DIRECTION OUTPUT ;
    USE SIGNAL ;
    PORT
      LAYER M3 ;
        RECT  54 17.136 54.018 17.28 ;
    END
  END o[540]
  PIN o[541]
    DIRECTION OUTPUT ;
    USE SIGNAL ;
    PORT
      LAYER M5 ;
        RECT  54.096 17.088 54.12 17.28 ;
    END
  END o[541]
  PIN o[542]
    DIRECTION OUTPUT ;
    USE SIGNAL ;
    PORT
      LAYER M3 ;
        RECT  54.18 17.136 54.198 17.28 ;
    END
  END o[542]
  PIN o[543]
    DIRECTION OUTPUT ;
    USE SIGNAL ;
    PORT
      LAYER M5 ;
        RECT  54.288 17.088 54.312 17.28 ;
    END
  END o[543]
  PIN o[544]
    DIRECTION OUTPUT ;
    USE SIGNAL ;
    PORT
      LAYER M3 ;
        RECT  54.36 17.136 54.378 17.28 ;
    END
  END o[544]
  PIN o[545]
    DIRECTION OUTPUT ;
    USE SIGNAL ;
    PORT
      LAYER M5 ;
        RECT  54.48 17.088 54.504 17.28 ;
    END
  END o[545]
  PIN o[546]
    DIRECTION OUTPUT ;
    USE SIGNAL ;
    PORT
      LAYER M3 ;
        RECT  54.576 17.136 54.594 17.28 ;
    END
  END o[546]
  PIN o[547]
    DIRECTION OUTPUT ;
    USE SIGNAL ;
    PORT
      LAYER M5 ;
        RECT  54.672 17.088 54.696 17.28 ;
    END
  END o[547]
  PIN o[548]
    DIRECTION OUTPUT ;
    USE SIGNAL ;
    PORT
      LAYER M3 ;
        RECT  54.756 17.136 54.774 17.28 ;
    END
  END o[548]
  PIN o[549]
    DIRECTION OUTPUT ;
    USE SIGNAL ;
    PORT
      LAYER M5 ;
        RECT  54.864 17.088 54.888 17.28 ;
    END
  END o[549]
  PIN o[54]
    DIRECTION OUTPUT ;
    USE SIGNAL ;
    PORT
      LAYER M3 ;
        RECT  7.38 17.136 7.398 17.28 ;
    END
  END o[54]
  PIN o[550]
    DIRECTION OUTPUT ;
    USE SIGNAL ;
    PORT
      LAYER M3 ;
        RECT  54.936 17.136 54.954 17.28 ;
    END
  END o[550]
  PIN o[551]
    DIRECTION OUTPUT ;
    USE SIGNAL ;
    PORT
      LAYER M5 ;
        RECT  55.056 17.088 55.08 17.28 ;
    END
  END o[551]
  PIN o[552]
    DIRECTION OUTPUT ;
    USE SIGNAL ;
    PORT
      LAYER M3 ;
        RECT  55.152 17.136 55.17 17.28 ;
    END
  END o[552]
  PIN o[553]
    DIRECTION OUTPUT ;
    USE SIGNAL ;
    PORT
      LAYER M5 ;
        RECT  55.248 17.088 55.272 17.28 ;
    END
  END o[553]
  PIN o[554]
    DIRECTION OUTPUT ;
    USE SIGNAL ;
    PORT
      LAYER M3 ;
        RECT  55.332 17.136 55.35 17.28 ;
    END
  END o[554]
  PIN o[555]
    DIRECTION OUTPUT ;
    USE SIGNAL ;
    PORT
      LAYER M5 ;
        RECT  55.44 17.088 55.464 17.28 ;
    END
  END o[555]
  PIN o[556]
    DIRECTION OUTPUT ;
    USE SIGNAL ;
    PORT
      LAYER M3 ;
        RECT  55.512 17.136 55.53 17.28 ;
    END
  END o[556]
  PIN o[557]
    DIRECTION OUTPUT ;
    USE SIGNAL ;
    PORT
      LAYER M5 ;
        RECT  55.632 17.088 55.656 17.28 ;
    END
  END o[557]
  PIN o[558]
    DIRECTION OUTPUT ;
    USE SIGNAL ;
    PORT
      LAYER M3 ;
        RECT  55.728 17.136 55.746 17.28 ;
    END
  END o[558]
  PIN o[559]
    DIRECTION OUTPUT ;
    USE SIGNAL ;
    PORT
      LAYER M5 ;
        RECT  55.824 17.088 55.848 17.28 ;
    END
  END o[559]
  PIN o[55]
    DIRECTION OUTPUT ;
    USE SIGNAL ;
    PORT
      LAYER M5 ;
        RECT  7.488 17.088 7.512 17.28 ;
    END
  END o[55]
  PIN o[560]
    DIRECTION OUTPUT ;
    USE SIGNAL ;
    PORT
      LAYER M3 ;
        RECT  55.908 17.136 55.926 17.28 ;
    END
  END o[560]
  PIN o[561]
    DIRECTION OUTPUT ;
    USE SIGNAL ;
    PORT
      LAYER M5 ;
        RECT  56.016 17.088 56.04 17.28 ;
    END
  END o[561]
  PIN o[56]
    DIRECTION OUTPUT ;
    USE SIGNAL ;
    PORT
      LAYER M3 ;
        RECT  7.56 17.136 7.578 17.28 ;
    END
  END o[56]
  PIN o[57]
    DIRECTION OUTPUT ;
    USE SIGNAL ;
    PORT
      LAYER M5 ;
        RECT  7.68 17.088 7.704 17.28 ;
    END
  END o[57]
  PIN o[58]
    DIRECTION OUTPUT ;
    USE SIGNAL ;
    PORT
      LAYER M3 ;
        RECT  7.776 17.136 7.794 17.28 ;
    END
  END o[58]
  PIN o[59]
    DIRECTION OUTPUT ;
    USE SIGNAL ;
    PORT
      LAYER M5 ;
        RECT  7.872 17.088 7.896 17.28 ;
    END
  END o[59]
  PIN o[5]
    DIRECTION OUTPUT ;
    USE SIGNAL ;
    PORT
      LAYER M5 ;
        RECT  2.688 17.088 2.712 17.28 ;
    END
  END o[5]
  PIN o[60]
    DIRECTION OUTPUT ;
    USE SIGNAL ;
    PORT
      LAYER M3 ;
        RECT  7.956 17.136 7.974 17.28 ;
    END
  END o[60]
  PIN o[61]
    DIRECTION OUTPUT ;
    USE SIGNAL ;
    PORT
      LAYER M5 ;
        RECT  8.064 17.088 8.088 17.28 ;
    END
  END o[61]
  PIN o[62]
    DIRECTION OUTPUT ;
    USE SIGNAL ;
    PORT
      LAYER M3 ;
        RECT  8.136 17.136 8.154 17.28 ;
    END
  END o[62]
  PIN o[63]
    DIRECTION OUTPUT ;
    USE SIGNAL ;
    PORT
      LAYER M5 ;
        RECT  8.256 17.088 8.28 17.28 ;
    END
  END o[63]
  PIN o[64]
    DIRECTION OUTPUT ;
    USE SIGNAL ;
    PORT
      LAYER M3 ;
        RECT  8.352 17.136 8.37 17.28 ;
    END
  END o[64]
  PIN o[65]
    DIRECTION OUTPUT ;
    USE SIGNAL ;
    PORT
      LAYER M5 ;
        RECT  8.448 17.088 8.472 17.28 ;
    END
  END o[65]
  PIN o[66]
    DIRECTION OUTPUT ;
    USE SIGNAL ;
    PORT
      LAYER M3 ;
        RECT  8.532 17.136 8.55 17.28 ;
    END
  END o[66]
  PIN o[67]
    DIRECTION OUTPUT ;
    USE SIGNAL ;
    PORT
      LAYER M5 ;
        RECT  8.64 17.088 8.664 17.28 ;
    END
  END o[67]
  PIN o[68]
    DIRECTION OUTPUT ;
    USE SIGNAL ;
    PORT
      LAYER M3 ;
        RECT  8.712 17.136 8.73 17.28 ;
    END
  END o[68]
  PIN o[69]
    DIRECTION OUTPUT ;
    USE SIGNAL ;
    PORT
      LAYER M5 ;
        RECT  8.832 17.088 8.856 17.28 ;
    END
  END o[69]
  PIN o[6]
    DIRECTION OUTPUT ;
    USE SIGNAL ;
    PORT
      LAYER M3 ;
        RECT  2.772 17.136 2.79 17.28 ;
    END
  END o[6]
  PIN o[70]
    DIRECTION OUTPUT ;
    USE SIGNAL ;
    PORT
      LAYER M3 ;
        RECT  8.928 17.136 8.946 17.28 ;
    END
  END o[70]
  PIN o[71]
    DIRECTION OUTPUT ;
    USE SIGNAL ;
    PORT
      LAYER M5 ;
        RECT  9.024 17.088 9.048 17.28 ;
    END
  END o[71]
  PIN o[72]
    DIRECTION OUTPUT ;
    USE SIGNAL ;
    PORT
      LAYER M3 ;
        RECT  9.108 17.136 9.126 17.28 ;
    END
  END o[72]
  PIN o[73]
    DIRECTION OUTPUT ;
    USE SIGNAL ;
    PORT
      LAYER M5 ;
        RECT  9.216 17.088 9.24 17.28 ;
    END
  END o[73]
  PIN o[74]
    DIRECTION OUTPUT ;
    USE SIGNAL ;
    PORT
      LAYER M3 ;
        RECT  9.288 17.136 9.306 17.28 ;
    END
  END o[74]
  PIN o[75]
    DIRECTION OUTPUT ;
    USE SIGNAL ;
    PORT
      LAYER M5 ;
        RECT  9.408 17.088 9.432 17.28 ;
    END
  END o[75]
  PIN o[76]
    DIRECTION OUTPUT ;
    USE SIGNAL ;
    PORT
      LAYER M3 ;
        RECT  9.504 17.136 9.522 17.28 ;
    END
  END o[76]
  PIN o[77]
    DIRECTION OUTPUT ;
    USE SIGNAL ;
    PORT
      LAYER M5 ;
        RECT  9.6 17.088 9.624 17.28 ;
    END
  END o[77]
  PIN o[78]
    DIRECTION OUTPUT ;
    USE SIGNAL ;
    PORT
      LAYER M3 ;
        RECT  9.684 17.136 9.702 17.28 ;
    END
  END o[78]
  PIN o[79]
    DIRECTION OUTPUT ;
    USE SIGNAL ;
    PORT
      LAYER M5 ;
        RECT  9.792 17.088 9.816 17.28 ;
    END
  END o[79]
  PIN o[7]
    DIRECTION OUTPUT ;
    USE SIGNAL ;
    PORT
      LAYER M5 ;
        RECT  2.88 17.088 2.904 17.28 ;
    END
  END o[7]
  PIN o[80]
    DIRECTION OUTPUT ;
    USE SIGNAL ;
    PORT
      LAYER M3 ;
        RECT  9.864 17.136 9.882 17.28 ;
    END
  END o[80]
  PIN o[81]
    DIRECTION OUTPUT ;
    USE SIGNAL ;
    PORT
      LAYER M5 ;
        RECT  9.984 17.088 10.008 17.28 ;
    END
  END o[81]
  PIN o[82]
    DIRECTION OUTPUT ;
    USE SIGNAL ;
    PORT
      LAYER M3 ;
        RECT  10.08 17.136 10.098 17.28 ;
    END
  END o[82]
  PIN o[83]
    DIRECTION OUTPUT ;
    USE SIGNAL ;
    PORT
      LAYER M5 ;
        RECT  10.176 17.088 10.2 17.28 ;
    END
  END o[83]
  PIN o[84]
    DIRECTION OUTPUT ;
    USE SIGNAL ;
    PORT
      LAYER M3 ;
        RECT  10.26 17.136 10.278 17.28 ;
    END
  END o[84]
  PIN o[85]
    DIRECTION OUTPUT ;
    USE SIGNAL ;
    PORT
      LAYER M5 ;
        RECT  10.368 17.088 10.392 17.28 ;
    END
  END o[85]
  PIN o[86]
    DIRECTION OUTPUT ;
    USE SIGNAL ;
    PORT
      LAYER M3 ;
        RECT  10.44 17.136 10.458 17.28 ;
    END
  END o[86]
  PIN o[87]
    DIRECTION OUTPUT ;
    USE SIGNAL ;
    PORT
      LAYER M5 ;
        RECT  10.56 17.088 10.584 17.28 ;
    END
  END o[87]
  PIN o[88]
    DIRECTION OUTPUT ;
    USE SIGNAL ;
    PORT
      LAYER M3 ;
        RECT  10.656 17.136 10.674 17.28 ;
    END
  END o[88]
  PIN o[89]
    DIRECTION OUTPUT ;
    USE SIGNAL ;
    PORT
      LAYER M5 ;
        RECT  10.752 17.088 10.776 17.28 ;
    END
  END o[89]
  PIN o[8]
    DIRECTION OUTPUT ;
    USE SIGNAL ;
    PORT
      LAYER M3 ;
        RECT  2.952 17.136 2.97 17.28 ;
    END
  END o[8]
  PIN o[90]
    DIRECTION OUTPUT ;
    USE SIGNAL ;
    PORT
      LAYER M3 ;
        RECT  10.836 17.136 10.854 17.28 ;
    END
  END o[90]
  PIN o[91]
    DIRECTION OUTPUT ;
    USE SIGNAL ;
    PORT
      LAYER M5 ;
        RECT  10.944 17.088 10.968 17.28 ;
    END
  END o[91]
  PIN o[92]
    DIRECTION OUTPUT ;
    USE SIGNAL ;
    PORT
      LAYER M3 ;
        RECT  11.016 17.136 11.034 17.28 ;
    END
  END o[92]
  PIN o[93]
    DIRECTION OUTPUT ;
    USE SIGNAL ;
    PORT
      LAYER M5 ;
        RECT  11.136 17.088 11.16 17.28 ;
    END
  END o[93]
  PIN o[94]
    DIRECTION OUTPUT ;
    USE SIGNAL ;
    PORT
      LAYER M3 ;
        RECT  11.232 17.136 11.25 17.28 ;
    END
  END o[94]
  PIN o[95]
    DIRECTION OUTPUT ;
    USE SIGNAL ;
    PORT
      LAYER M5 ;
        RECT  11.328 17.088 11.352 17.28 ;
    END
  END o[95]
  PIN o[96]
    DIRECTION OUTPUT ;
    USE SIGNAL ;
    PORT
      LAYER M3 ;
        RECT  11.412 17.136 11.43 17.28 ;
    END
  END o[96]
  PIN o[97]
    DIRECTION OUTPUT ;
    USE SIGNAL ;
    PORT
      LAYER M5 ;
        RECT  11.52 17.088 11.544 17.28 ;
    END
  END o[97]
  PIN o[98]
    DIRECTION OUTPUT ;
    USE SIGNAL ;
    PORT
      LAYER M3 ;
        RECT  11.592 17.136 11.61 17.28 ;
    END
  END o[98]
  PIN o[99]
    DIRECTION OUTPUT ;
    USE SIGNAL ;
    PORT
      LAYER M5 ;
        RECT  11.712 17.088 11.736 17.28 ;
    END
  END o[99]
  PIN o[9]
    DIRECTION OUTPUT ;
    USE SIGNAL ;
    PORT
      LAYER M5 ;
        RECT  3.072 17.088 3.096 17.28 ;
    END
  END o[9]
  PIN rs
    DIRECTION INPUT ;
    USE SIGNAL ;
    PORT
      LAYER M4 ;
        RECT  58.128 11.904 58.32 11.928 ;
    END
    PORT
      LAYER M4 ;
        RECT  57.589 11.904 58.14 11.928 ;
    END
  END rs
  PIN VDD
    DIRECTION INOUT ;
    USE POWER ;
    PORT
      LAYER M5 ;
        RECT  53.892 2.151 54.012 15.129 ;
        RECT  51.192 2.151 51.312 15.129 ;
        RECT  48.492 2.151 48.612 15.129 ;
        RECT  45.792 2.151 45.912 15.129 ;
        RECT  43.092 2.151 43.212 15.129 ;
        RECT  40.392 2.151 40.512 15.129 ;
        RECT  37.692 2.151 37.812 15.129 ;
        RECT  34.992 2.151 35.112 15.129 ;
        RECT  32.292 2.151 32.412 15.129 ;
        RECT  29.592 2.151 29.712 15.129 ;
        RECT  26.892 2.151 27.012 15.129 ;
        RECT  24.192 2.151 24.312 15.129 ;
        RECT  21.492 2.151 21.612 15.129 ;
        RECT  18.792 2.151 18.912 15.129 ;
        RECT  16.092 2.151 16.212 15.129 ;
        RECT  13.392 2.151 13.512 15.129 ;
        RECT  10.692 2.151 10.812 15.129 ;
        RECT  7.992 2.151 8.112 15.129 ;
        RECT  5.292 2.151 5.412 15.129 ;
        RECT  2.592 2.151 2.712 15.129 ;
    END
  END VDD
  PIN VSS
    DIRECTION INOUT ;
    USE GROUND ;
    PORT
      LAYER M5 ;
        RECT  53.7 2.137 53.82 15.143 ;
        RECT  51 2.137 51.12 15.143 ;
        RECT  48.3 2.137 48.42 15.143 ;
        RECT  45.6 2.137 45.72 15.143 ;
        RECT  42.9 2.137 43.02 15.143 ;
        RECT  40.2 2.137 40.32 15.143 ;
        RECT  37.5 2.137 37.62 15.143 ;
        RECT  34.8 2.137 34.92 15.143 ;
        RECT  32.1 2.137 32.22 15.143 ;
        RECT  29.4 2.137 29.52 15.143 ;
        RECT  26.7 2.137 26.82 15.143 ;
        RECT  24 2.137 24.12 15.143 ;
        RECT  21.3 2.137 21.42 15.143 ;
        RECT  18.6 2.137 18.72 15.143 ;
        RECT  15.9 2.137 16.02 15.143 ;
        RECT  13.2 2.137 13.32 15.143 ;
        RECT  10.5 2.137 10.62 15.143 ;
        RECT  7.8 2.137 7.92 15.143 ;
        RECT  5.1 2.137 5.22 15.143 ;
        RECT  2.4 2.137 2.52 15.143 ;
    END
  END VSS
  # OT_OBS_CLOSED layer=M5 d_um=1.536 added=16
  OBS
    LAYER RVTN ;
     RECT  2.16 2.16 56.16 2.295 ;
     RECT  2.16 2.565 56.16 2.835 ;
     RECT  2.16 3.105 56.16 3.375 ;
     RECT  2.16 3.645 56.16 3.915 ;
     RECT  2.16 4.185 56.16 4.455 ;
     RECT  2.16 4.725 56.16 4.995 ;
     RECT  2.16 5.265 56.16 5.535 ;
     RECT  2.16 5.805 56.16 6.075 ;
     RECT  2.16 6.345 56.16 6.615 ;
     RECT  2.16 6.885 56.16 7.155 ;
     RECT  2.16 7.425 56.16 7.695 ;
     RECT  2.16 7.965 56.16 8.235 ;
     RECT  2.16 8.505 56.16 8.775 ;
     RECT  2.16 9.045 56.16 9.315 ;
     RECT  2.16 9.585 56.16 9.855 ;
     RECT  2.16 10.125 56.16 10.395 ;
     RECT  2.16 10.665 56.16 10.935 ;
     RECT  2.16 11.205 56.16 11.475 ;
     RECT  2.16 11.745 56.16 12.015 ;
     RECT  2.16 12.285 56.16 12.555 ;
     RECT  2.16 12.825 56.16 13.095 ;
     RECT  2.16 13.365 56.16 13.635 ;
     RECT  2.16 13.905 56.16 14.175 ;
     RECT  2.16 14.445 56.16 14.715 ;
     RECT  2.16 14.985 56.16 15.12 ;
    LAYER RVTP ;
     RECT  2.16 2.295 56.16 2.565 ;
     RECT  2.16 2.835 56.16 3.105 ;
     RECT  2.16 3.375 56.16 3.645 ;
     RECT  2.16 3.915 56.16 4.185 ;
     RECT  2.16 4.455 56.16 4.725 ;
     RECT  2.16 4.995 56.16 5.265 ;
     RECT  2.16 5.535 56.16 5.805 ;
     RECT  2.16 6.075 56.16 6.345 ;
     RECT  2.16 6.615 56.16 6.885 ;
     RECT  2.16 7.155 56.16 7.425 ;
     RECT  2.16 7.695 56.16 7.965 ;
     RECT  2.16 8.235 56.16 8.505 ;
     RECT  2.16 8.775 56.16 9.045 ;
     RECT  2.16 9.315 56.16 9.585 ;
     RECT  2.16 9.855 56.16 10.125 ;
     RECT  2.16 10.395 56.16 10.665 ;
     RECT  2.16 10.935 56.16 11.205 ;
     RECT  2.16 11.475 56.16 11.745 ;
     RECT  2.16 12.015 56.16 12.285 ;
     RECT  2.16 12.555 56.16 12.825 ;
     RECT  2.16 13.095 56.16 13.365 ;
     RECT  2.16 13.635 56.16 13.905 ;
     RECT  2.16 14.175 56.16 14.445 ;
     RECT  2.16 14.715 56.16 14.985 ;
    LAYER M1 ;
     RECT  2.16 2.151 56.16 15.129 ;
    LAYER M2 ;
     RECT  2.299 0.144 2.335 0.162 ;
     RECT  2.335 0.144 2.615 0.234 ;
     RECT  2.16 2.151 3.631 15.129 ;
     RECT  2.371 16.542 3.739 16.56 ;
     RECT  3.775 1.152 3.875 1.17 ;
     RECT  3.739 16.542 3.919 16.596 ;
     RECT  2.615 0.144 3.947 0.162 ;
     RECT  3.919 16.542 4.099 16.668 ;
     RECT  4.099 16.542 4.199 16.704 ;
     RECT  4.199 16.65 4.235 16.704 ;
     RECT  4.235 16.65 4.415 16.668 ;
     RECT  3.631 2.106 5.071 15.129 ;
     RECT  5.071 2.106 5.251 15.399 ;
     RECT  5.251 2.106 5.387 15.516 ;
     RECT  4.891 0.144 5.495 0.324 ;
     RECT  5.387 2.151 5.567 15.516 ;
     RECT  5.467 16.542 5.999 16.56 ;
     RECT  5.567 2.151 6.179 15.48 ;
     RECT  6.043 1.152 6.827 1.17 ;
     RECT  6.179 2.151 6.827 15.21 ;
     RECT  6.827 2.151 7.951 15.174 ;
     RECT  7.951 2.151 8.267 15.354 ;
     RECT  5.495 0.144 8.707 0.162 ;
     RECT  8.707 0.144 8.951 0.234 ;
     RECT  8.707 1.152 8.951 1.17 ;
     RECT  8.267 2.151 8.995 15.174 ;
     RECT  8.995 2.151 9.131 15.21 ;
     RECT  8.951 0.144 10.103 0.162 ;
     RECT  10.075 17.118 10.111 17.136 ;
     RECT  10.111 17.118 10.211 17.208 ;
     RECT  9.131 2.151 10.255 15.174 ;
     RECT  10.255 2.151 10.823 15.246 ;
     RECT  10.831 0.144 10.967 0.162 ;
     RECT  10.831 16.542 11.687 16.56 ;
     RECT  11.047 1.152 12.083 1.17 ;
     RECT  10.823 2.151 13.099 15.129 ;
     RECT  13.315 17.118 13.351 17.136 ;
     RECT  13.351 17.118 13.451 17.208 ;
     RECT  13.099 2.151 13.523 15.174 ;
     RECT  12.019 0.144 13.811 0.162 ;
     RECT  14.647 16.578 14.783 16.596 ;
     RECT  14.863 0.144 14.963 0.162 ;
     RECT  14.827 17.118 14.963 17.208 ;
     RECT  13.783 1.152 15.611 1.17 ;
     RECT  13.523 2.151 16.015 15.129 ;
     RECT  16.015 1.224 16.231 1.242 ;
     RECT  16.015 2.151 16.231 15.318 ;
     RECT  16.231 1.224 16.339 15.318 ;
     RECT  15.763 0.144 16.439 0.162 ;
     RECT  16.339 1.152 16.475 15.318 ;
     RECT  16.475 1.728 16.691 15.318 ;
     RECT  17.743 0.306 17.959 0.324 ;
     RECT  17.959 0.144 17.987 0.324 ;
     RECT  18.103 16.65 18.203 16.668 ;
     RECT  16.691 2.151 18.463 15.318 ;
     RECT  18.463 2.151 18.707 15.399 ;
     RECT  17.987 0.144 18.743 0.234 ;
     RECT  18.707 2.151 18.779 15.318 ;
     RECT  18.779 2.151 19.715 15.174 ;
     RECT  18.743 0.144 19.787 0.162 ;
     RECT  19.147 1.152 20.399 1.17 ;
     RECT  19.715 2.151 20.803 15.129 ;
     RECT  20.803 2.151 20.911 15.174 ;
     RECT  20.911 2.151 21.011 15.516 ;
     RECT  21.011 2.151 21.019 15.21 ;
     RECT  20.839 0.144 21.163 0.162 ;
     RECT  21.019 2.106 21.415 15.21 ;
     RECT  21.415 2.034 21.659 15.21 ;
     RECT  21.659 2.034 21.947 15.129 ;
     RECT  21.163 0.144 22.019 0.234 ;
     RECT  21.919 1.152 22.703 1.17 ;
     RECT  22.019 0.144 22.775 0.162 ;
     RECT  21.947 2.151 23.683 15.129 ;
     RECT  23.683 2.151 24.079 15.174 ;
     RECT  24.079 2.151 24.115 15.21 ;
     RECT  24.115 1.728 24.251 15.21 ;
     RECT  23.539 0.144 24.403 0.162 ;
     RECT  24.251 2.151 24.439 15.21 ;
     RECT  24.403 0.144 24.503 0.234 ;
     RECT  24.439 2.151 24.835 15.246 ;
     RECT  24.503 0.144 24.971 0.162 ;
     RECT  24.943 1.152 25.043 1.17 ;
     RECT  24.835 2.151 26.023 15.282 ;
     RECT  26.023 1.728 26.059 15.282 ;
     RECT  26.059 1.728 26.195 15.399 ;
     RECT  26.195 1.728 26.599 15.21 ;
     RECT  26.599 1.656 26.699 15.21 ;
     RECT  26.779 0.144 26.995 0.162 ;
     RECT  26.699 2.151 27.031 15.21 ;
     RECT  26.995 0.144 27.167 0.234 ;
     RECT  27.031 2.151 27.347 15.399 ;
     RECT  27.347 2.151 27.571 15.174 ;
     RECT  27.571 1.728 27.635 15.174 ;
     RECT  27.167 0.144 27.887 0.162 ;
     RECT  27.635 1.728 27.923 15.129 ;
     RECT  27.923 2.151 28.363 15.129 ;
     RECT  28.363 2.151 28.499 15.354 ;
     RECT  27.931 1.152 29.399 1.17 ;
     RECT  28.499 2.151 29.443 15.174 ;
     RECT  29.443 2.151 29.579 15.21 ;
     RECT  29.579 2.151 30.299 15.174 ;
     RECT  30.019 16.542 30.479 16.56 ;
     RECT  30.451 1.152 30.587 1.17 ;
     RECT  30.299 2.151 31.027 15.129 ;
     RECT  31.099 16.65 31.199 16.668 ;
     RECT  31.027 2.106 31.531 15.129 ;
     RECT  31.675 1.152 31.775 1.17 ;
     RECT  31.531 2.106 31.783 15.174 ;
     RECT  31.783 1.728 31.919 15.174 ;
     RECT  31.927 17.118 31.963 17.136 ;
     RECT  31.963 17.118 32.063 17.208 ;
     RECT  31.919 2.106 32.107 15.174 ;
     RECT  32.107 2.106 32.279 15.21 ;
     RECT  32.279 2.106 32.675 15.174 ;
     RECT  28.723 0.144 32.855 0.162 ;
     RECT  32.675 2.151 33.691 15.174 ;
     RECT  33.691 2.106 33.835 15.174 ;
     RECT  33.835 2.106 33.935 15.246 ;
     RECT  33.935 2.106 34.187 15.129 ;
     RECT  34.187 2.151 34.807 15.129 ;
     RECT  34.807 2.151 34.987 15.21 ;
     RECT  33.727 0.144 35.059 0.162 ;
     RECT  32.935 1.152 35.203 1.17 ;
     RECT  35.059 0.144 35.231 0.198 ;
     RECT  34.987 2.151 35.267 15.282 ;
     RECT  35.239 0.216 35.339 0.234 ;
     RECT  35.203 1.152 35.663 1.242 ;
     RECT  35.267 2.151 36.499 15.129 ;
     RECT  36.607 1.152 36.743 1.17 ;
     RECT  37.111 17.118 37.147 17.136 ;
     RECT  37.147 17.118 37.247 17.208 ;
     RECT  36.499 2.106 37.363 15.129 ;
     RECT  37.363 2.106 37.535 15.21 ;
     RECT  37.535 2.106 37.543 15.129 ;
     RECT  37.543 2.07 37.895 15.129 ;
     RECT  38.011 17.118 38.111 17.208 ;
     RECT  38.111 17.19 38.147 17.208 ;
     RECT  37.895 2.151 38.443 15.129 ;
     RECT  36.823 0.144 38.543 0.162 ;
     RECT  38.443 2.151 38.659 15.174 ;
     RECT  38.911 1.152 39.767 1.17 ;
     RECT  38.659 2.151 39.991 15.246 ;
     RECT  39.991 2.151 40.027 15.282 ;
     RECT  40.027 2.151 40.199 15.354 ;
     RECT  39.487 0.144 40.271 0.162 ;
     RECT  40.567 17.118 40.603 17.136 ;
     RECT  40.603 17.118 40.703 17.208 ;
     RECT  40.199 2.151 41.143 15.246 ;
     RECT  41.143 2.151 41.459 15.354 ;
     RECT  41.459 2.151 41.567 15.174 ;
     RECT  41.215 0.144 41.791 0.162 ;
     RECT  41.827 1.224 41.927 1.242 ;
     RECT  41.791 0.144 41.963 0.234 ;
     RECT  41.963 0.144 41.999 0.162 ;
     RECT  41.935 1.152 42.035 1.17 ;
     RECT  42.007 17.118 42.107 17.208 ;
     RECT  41.567 2.151 42.115 15.129 ;
     RECT  42.107 17.19 42.143 17.208 ;
     RECT  42.115 2.106 43.087 15.129 ;
     RECT  43.087 2.106 43.259 15.174 ;
     RECT  43.259 2.106 43.303 15.129 ;
     RECT  42.943 0.144 43.619 0.162 ;
     RECT  43.303 1.422 43.987 15.129 ;
     RECT  44.203 17.118 44.239 17.136 ;
     RECT  44.239 17.118 44.339 17.208 ;
     RECT  43.987 1.422 44.455 15.399 ;
     RECT  44.455 1.152 44.555 15.399 ;
     RECT  45.031 0.144 45.427 0.162 ;
     RECT  45.427 0.144 45.527 0.234 ;
     RECT  44.555 1.422 45.751 15.399 ;
     RECT  45.751 1.152 46.039 15.399 ;
     RECT  46.039 1.152 46.139 15.444 ;
     RECT  45.527 0.144 47.219 0.162 ;
     RECT  46.139 1.152 47.651 15.399 ;
     RECT  47.651 1.422 47.695 15.399 ;
     RECT  47.695 1.422 47.867 15.444 ;
     RECT  48.127 0.144 48.299 0.162 ;
     RECT  47.867 1.422 48.523 15.399 ;
     RECT  48.523 1.152 48.739 15.399 ;
     RECT  48.739 1.152 49.019 15.444 ;
     RECT  49.099 0.144 49.307 0.162 ;
     RECT  49.019 1.152 51.431 15.399 ;
     RECT  51.431 1.422 52.159 15.399 ;
     RECT  53.167 17.19 53.203 17.208 ;
     RECT  53.203 17.118 53.303 17.208 ;
     RECT  52.159 1.152 54.707 15.399 ;
     RECT  54.707 1.152 55.247 15.174 ;
     RECT  51.007 0.144 55.823 0.162 ;
     RECT  55.247 1.422 56.075 15.174 ;
     RECT  56.075 1.881 56.147 15.174 ;
     RECT  56.147 1.998 56.16 15.174 ;
     RECT  56.16 13.608 56.183 15.174 ;
     RECT  56.16 2.916 56.219 2.934 ;
     RECT  56.16 9.936 56.219 10.08 ;
     RECT  56.183 13.608 56.219 14.472 ;
     RECT  56.16 7.398 56.471 7.416 ;
     RECT  56.219 10.062 56.507 10.08 ;
     RECT  56.219 13.716 56.543 14.472 ;
     RECT  56.16 11.214 56.579 12.852 ;
     RECT  56.579 11.448 56.651 12.852 ;
     RECT  56.651 11.646 56.687 12.852 ;
     RECT  56.543 13.716 56.723 13.734 ;
     RECT  56.16 4.806 56.759 4.824 ;
     RECT  56.16 1.998 57.047 2.016 ;
     RECT  57.019 3.42 57.587 3.438 ;
     RECT  56.687 11.646 57.587 12.276 ;
     RECT  57.587 11.646 57.623 11.664 ;
    LAYER M3 ;
     RECT  2.214 0.108 2.376 0.144 ;
     RECT  2.394 0.108 2.592 0.144 ;
     RECT  2.61 0.108 2.772 0.144 ;
     RECT  2.79 0.108 2.952 0.144 ;
     RECT  2.97 0.108 3.168 0.144 ;
     RECT  3.186 0.108 3.348 0.144 ;
     RECT  3.366 0.108 3.528 0.144 ;
     RECT  3.546 0.108 3.744 0.144 ;
     RECT  3.762 0.108 3.924 0.144 ;
     RECT  3.942 0.108 4.104 0.144 ;
     RECT  4.122 0.108 4.32 0.144 ;
     RECT  4.338 0.108 4.5 0.144 ;
     RECT  4.518 0.108 4.68 0.144 ;
     RECT  4.698 0.108 4.896 0.144 ;
     RECT  4.914 0.108 5.076 0.144 ;
     RECT  5.094 0.108 5.256 0.144 ;
     RECT  5.274 0.108 5.472 0.144 ;
     RECT  5.49 0.108 5.652 0.144 ;
     RECT  5.67 0.108 5.868 0.144 ;
     RECT  5.886 0.108 6.048 0.144 ;
     RECT  6.066 0.108 6.228 0.144 ;
     RECT  6.246 0.108 6.444 0.144 ;
     RECT  6.462 0.108 6.624 0.144 ;
     RECT  6.642 0.108 6.804 0.144 ;
     RECT  6.822 0.108 7.02 0.144 ;
     RECT  7.038 0.108 7.2 0.144 ;
     RECT  7.218 0.108 7.38 0.144 ;
     RECT  7.398 0.108 7.596 0.144 ;
     RECT  7.614 0.108 7.776 0.144 ;
     RECT  7.794 0.108 7.956 0.144 ;
     RECT  7.974 0.108 8.172 0.144 ;
     RECT  8.19 0.108 8.352 0.144 ;
     RECT  8.37 0.108 8.532 0.144 ;
     RECT  8.55 0.108 8.748 0.144 ;
     RECT  8.766 0.108 8.928 0.144 ;
     RECT  8.946 0.108 9.108 0.144 ;
     RECT  9.126 0.108 9.324 0.144 ;
     RECT  9.342 0.108 9.504 0.144 ;
     RECT  9.522 0.108 9.684 0.144 ;
     RECT  9.702 0.108 9.9 0.144 ;
     RECT  9.918 0.108 10.08 0.144 ;
     RECT  10.098 0.108 10.26 0.144 ;
     RECT  10.278 0.108 10.476 0.144 ;
     RECT  10.494 0.108 10.656 0.144 ;
     RECT  10.674 0.108 10.836 0.144 ;
     RECT  10.854 0.108 11.052 0.144 ;
     RECT  11.07 0.108 11.232 0.144 ;
     RECT  11.25 0.108 11.412 0.144 ;
     RECT  11.43 0.108 11.628 0.144 ;
     RECT  11.646 0.108 11.808 0.144 ;
     RECT  11.826 0.108 11.988 0.144 ;
     RECT  12.006 0.108 12.204 0.144 ;
     RECT  12.222 0.108 12.384 0.144 ;
     RECT  12.402 0.108 12.564 0.144 ;
     RECT  12.582 0.108 12.78 0.144 ;
     RECT  12.798 0.108 12.96 0.144 ;
     RECT  12.978 0.108 13.14 0.144 ;
     RECT  13.158 0.108 13.356 0.144 ;
     RECT  13.374 0.108 13.536 0.144 ;
     RECT  13.554 0.108 13.716 0.144 ;
     RECT  13.734 0.108 13.932 0.144 ;
     RECT  13.95 0.108 14.112 0.144 ;
     RECT  14.13 0.108 14.292 0.144 ;
     RECT  14.31 0.108 14.508 0.144 ;
     RECT  14.526 0.108 14.688 0.144 ;
     RECT  14.706 0.108 14.868 0.144 ;
     RECT  14.886 0.108 15.084 0.144 ;
     RECT  15.102 0.108 15.264 0.144 ;
     RECT  15.282 0.108 15.444 0.144 ;
     RECT  15.462 0.108 15.66 0.144 ;
     RECT  15.678 0.108 15.84 0.144 ;
     RECT  15.858 0.108 16.02 0.144 ;
     RECT  16.038 0.108 16.236 0.144 ;
     RECT  16.254 0.108 16.416 0.144 ;
     RECT  16.434 0.108 16.596 0.144 ;
     RECT  16.614 0.108 16.812 0.144 ;
     RECT  16.83 0.108 16.992 0.144 ;
     RECT  17.01 0.108 17.172 0.144 ;
     RECT  17.19 0.108 17.388 0.144 ;
     RECT  17.406 0.108 17.568 0.144 ;
     RECT  17.586 0.108 17.748 0.144 ;
     RECT  17.766 0.108 17.964 0.144 ;
     RECT  17.982 0.108 18.144 0.144 ;
     RECT  18.162 0.108 18.324 0.144 ;
     RECT  18.342 0.108 18.54 0.144 ;
     RECT  18.558 0.108 18.72 0.144 ;
     RECT  18.738 0.108 18.9 0.144 ;
     RECT  18.918 0.108 19.116 0.144 ;
     RECT  19.134 0.108 19.296 0.144 ;
     RECT  19.314 0.108 19.512 0.144 ;
     RECT  19.53 0.108 19.692 0.144 ;
     RECT  19.71 0.108 19.872 0.144 ;
     RECT  19.89 0.108 20.088 0.144 ;
     RECT  20.106 0.108 20.268 0.144 ;
     RECT  20.286 0.108 20.448 0.144 ;
     RECT  20.466 0.108 20.664 0.144 ;
     RECT  20.682 0.108 20.844 0.144 ;
     RECT  20.862 0.108 21.024 0.144 ;
     RECT  21.042 0.108 21.24 0.144 ;
     RECT  21.258 0.108 21.42 0.144 ;
     RECT  21.438 0.108 21.6 0.144 ;
     RECT  21.618 0.108 21.816 0.144 ;
     RECT  21.834 0.108 21.996 0.144 ;
     RECT  22.014 0.108 22.176 0.144 ;
     RECT  22.194 0.108 22.392 0.144 ;
     RECT  22.41 0.108 22.572 0.144 ;
     RECT  22.59 0.108 22.752 0.144 ;
     RECT  22.77 0.108 22.968 0.144 ;
     RECT  22.986 0.108 23.148 0.144 ;
     RECT  23.166 0.108 23.328 0.144 ;
     RECT  23.346 0.108 23.544 0.144 ;
     RECT  23.562 0.108 23.724 0.144 ;
     RECT  23.742 0.108 23.904 0.144 ;
     RECT  23.922 0.108 24.12 0.144 ;
     RECT  24.138 0.108 24.3 0.144 ;
     RECT  24.318 0.108 24.48 0.144 ;
     RECT  24.498 0.108 24.696 0.144 ;
     RECT  24.714 0.108 24.876 0.144 ;
     RECT  24.894 0.108 25.056 0.144 ;
     RECT  25.074 0.108 25.272 0.144 ;
     RECT  25.29 0.108 25.452 0.144 ;
     RECT  25.47 0.108 25.632 0.144 ;
     RECT  25.65 0.108 25.848 0.144 ;
     RECT  25.866 0.108 26.028 0.144 ;
     RECT  26.046 0.108 26.208 0.144 ;
     RECT  26.226 0.108 26.424 0.144 ;
     RECT  26.442 0.108 26.604 0.144 ;
     RECT  26.622 0.108 26.784 0.144 ;
     RECT  26.802 0.108 27 0.144 ;
     RECT  27.018 0.108 27.18 0.144 ;
     RECT  27.198 0.108 27.36 0.144 ;
     RECT  27.378 0.108 27.576 0.144 ;
     RECT  27.594 0.108 27.756 0.144 ;
     RECT  27.774 0.108 27.936 0.144 ;
     RECT  27.954 0.108 28.152 0.144 ;
     RECT  28.17 0.108 28.332 0.144 ;
     RECT  28.35 0.108 28.512 0.144 ;
     RECT  28.53 0.108 28.728 0.144 ;
     RECT  28.746 0.108 28.908 0.144 ;
     RECT  28.926 0.108 29.088 0.144 ;
     RECT  29.106 0.108 29.304 0.144 ;
     RECT  29.322 0.108 29.484 0.144 ;
     RECT  29.502 0.108 29.664 0.144 ;
     RECT  29.682 0.108 29.88 0.144 ;
     RECT  29.898 0.108 30.06 0.144 ;
     RECT  30.078 0.108 30.24 0.144 ;
     RECT  30.258 0.108 30.456 0.144 ;
     RECT  30.474 0.108 30.636 0.144 ;
     RECT  30.654 0.108 30.816 0.144 ;
     RECT  30.834 0.108 31.032 0.144 ;
     RECT  31.05 0.108 31.212 0.144 ;
     RECT  31.23 0.108 31.392 0.144 ;
     RECT  31.41 0.108 31.608 0.144 ;
     RECT  31.626 0.108 31.788 0.144 ;
     RECT  31.806 0.108 31.968 0.144 ;
     RECT  31.986 0.108 32.184 0.144 ;
     RECT  32.202 0.108 32.364 0.144 ;
     RECT  32.382 0.108 32.58 0.144 ;
     RECT  32.598 0.108 32.76 0.144 ;
     RECT  32.778 0.108 32.94 0.144 ;
     RECT  32.958 0.108 33.156 0.144 ;
     RECT  33.174 0.108 33.336 0.144 ;
     RECT  33.354 0.108 33.516 0.144 ;
     RECT  33.534 0.108 33.732 0.144 ;
     RECT  33.75 0.108 33.912 0.144 ;
     RECT  33.93 0.108 34.092 0.144 ;
     RECT  34.11 0.108 34.308 0.144 ;
     RECT  34.326 0.108 34.488 0.144 ;
     RECT  34.506 0.108 34.668 0.144 ;
     RECT  34.686 0.108 34.884 0.144 ;
     RECT  34.902 0.108 35.064 0.144 ;
     RECT  35.082 0.108 35.244 0.144 ;
     RECT  35.262 0.108 35.46 0.144 ;
     RECT  35.478 0.108 35.64 0.144 ;
     RECT  35.658 0.108 35.82 0.144 ;
     RECT  35.838 0.108 36.036 0.144 ;
     RECT  36.054 0.108 36.216 0.144 ;
     RECT  36.234 0.108 36.396 0.144 ;
     RECT  36.414 0.108 36.612 0.144 ;
     RECT  36.63 0.108 36.792 0.144 ;
     RECT  36.81 0.108 36.972 0.144 ;
     RECT  36.99 0.108 37.188 0.144 ;
     RECT  37.206 0.108 37.368 0.144 ;
     RECT  37.386 0.108 37.548 0.144 ;
     RECT  37.566 0.108 37.764 0.144 ;
     RECT  37.782 0.108 37.944 0.144 ;
     RECT  37.962 0.108 38.124 0.144 ;
     RECT  38.142 0.108 38.34 0.144 ;
     RECT  38.358 0.108 38.52 0.144 ;
     RECT  38.538 0.108 38.7 0.144 ;
     RECT  38.718 0.108 38.916 0.144 ;
     RECT  38.934 0.108 39.096 0.144 ;
     RECT  39.114 0.108 39.276 0.144 ;
     RECT  39.294 0.108 39.492 0.144 ;
     RECT  39.51 0.108 39.672 0.144 ;
     RECT  39.69 0.108 39.852 0.144 ;
     RECT  39.87 0.108 40.068 0.144 ;
     RECT  40.086 0.108 40.248 0.144 ;
     RECT  40.266 0.108 40.428 0.144 ;
     RECT  40.446 0.108 40.644 0.144 ;
     RECT  40.662 0.108 40.824 0.144 ;
     RECT  40.842 0.108 41.004 0.144 ;
     RECT  41.022 0.108 41.22 0.144 ;
     RECT  41.238 0.108 41.4 0.144 ;
     RECT  41.418 0.108 41.58 0.144 ;
     RECT  41.598 0.108 41.796 0.144 ;
     RECT  41.814 0.108 41.976 0.144 ;
     RECT  41.994 0.108 42.156 0.144 ;
     RECT  42.174 0.108 42.372 0.144 ;
     RECT  42.39 0.108 42.552 0.144 ;
     RECT  42.57 0.108 42.732 0.144 ;
     RECT  42.75 0.108 42.948 0.144 ;
     RECT  42.966 0.108 43.128 0.144 ;
     RECT  43.146 0.108 43.308 0.144 ;
     RECT  43.326 0.108 43.524 0.144 ;
     RECT  43.542 0.108 43.704 0.144 ;
     RECT  43.722 0.108 43.884 0.144 ;
     RECT  43.902 0.108 44.1 0.144 ;
     RECT  44.118 0.108 44.28 0.144 ;
     RECT  44.298 0.108 44.46 0.144 ;
     RECT  44.478 0.108 44.676 0.144 ;
     RECT  44.694 0.108 44.856 0.144 ;
     RECT  44.874 0.108 45.036 0.144 ;
     RECT  45.054 0.108 45.252 0.144 ;
     RECT  45.27 0.108 45.432 0.144 ;
     RECT  45.45 0.108 45.612 0.144 ;
     RECT  45.63 0.108 45.828 0.144 ;
     RECT  45.846 0.108 46.008 0.144 ;
     RECT  46.026 0.108 46.224 0.144 ;
     RECT  46.242 0.108 46.404 0.144 ;
     RECT  46.422 0.108 46.584 0.144 ;
     RECT  46.602 0.108 46.8 0.144 ;
     RECT  46.818 0.108 46.98 0.144 ;
     RECT  46.998 0.108 47.16 0.144 ;
     RECT  47.178 0.108 47.376 0.144 ;
     RECT  47.394 0.108 47.556 0.144 ;
     RECT  47.574 0.108 47.736 0.144 ;
     RECT  47.754 0.108 47.952 0.144 ;
     RECT  47.97 0.108 48.132 0.144 ;
     RECT  48.15 0.108 48.312 0.144 ;
     RECT  48.33 0.108 48.528 0.144 ;
     RECT  48.546 0.108 48.708 0.144 ;
     RECT  48.726 0.108 48.888 0.144 ;
     RECT  48.906 0.108 49.104 0.144 ;
     RECT  49.122 0.108 49.284 0.144 ;
     RECT  49.302 0.108 49.464 0.144 ;
     RECT  49.482 0.108 49.68 0.144 ;
     RECT  49.698 0.108 49.86 0.144 ;
     RECT  49.878 0.108 50.04 0.144 ;
     RECT  50.058 0.108 50.256 0.144 ;
     RECT  50.274 0.108 50.436 0.144 ;
     RECT  50.454 0.108 50.616 0.144 ;
     RECT  50.634 0.108 50.832 0.144 ;
     RECT  50.85 0.108 51.012 0.144 ;
     RECT  51.03 0.108 51.192 0.144 ;
     RECT  51.21 0.108 51.408 0.144 ;
     RECT  51.426 0.108 51.588 0.144 ;
     RECT  51.606 0.108 51.768 0.144 ;
     RECT  51.786 0.108 51.984 0.144 ;
     RECT  52.002 0.108 52.164 0.144 ;
     RECT  52.182 0.108 52.344 0.144 ;
     RECT  52.362 0.108 52.56 0.144 ;
     RECT  52.578 0.108 52.74 0.144 ;
     RECT  52.758 0.108 52.92 0.144 ;
     RECT  52.938 0.108 53.136 0.144 ;
     RECT  53.154 0.108 53.316 0.144 ;
     RECT  53.334 0.108 53.496 0.144 ;
     RECT  53.514 0.108 53.712 0.144 ;
     RECT  53.73 0.108 53.892 0.144 ;
     RECT  53.91 0.108 54.072 0.144 ;
     RECT  54.09 0.108 54.288 0.144 ;
     RECT  54.306 0.108 54.468 0.144 ;
     RECT  54.486 0.108 54.648 0.144 ;
     RECT  54.666 0.108 54.864 0.144 ;
     RECT  54.882 0.108 55.044 0.144 ;
     RECT  55.062 0.108 55.224 0.144 ;
     RECT  55.242 0.108 55.44 0.144 ;
     RECT  55.458 0.108 55.62 0.144 ;
     RECT  55.638 0.108 55.8 0.144 ;
     RECT  55.818 0.108 56.016 0.144 ;
     RECT  2.196 0.144 56.034 0.173 ;
     RECT  2.196 0.173 55.782 0.557 ;
     RECT  54.468 0.557 55.782 1.387 ;
     RECT  54.468 1.387 55.89 1.417 ;
     RECT  54.468 1.417 56.07 1.723 ;
     RECT  2.196 0.557 53.334 1.771 ;
     RECT  54.432 1.723 56.07 1.771 ;
     RECT  2.196 1.771 56.07 1.876 ;
     RECT  2.196 1.876 56.142 2.347 ;
     RECT  57.024 1.993 57.042 2.347 ;
     RECT  2.196 2.347 57.042 3.415 ;
     RECT  2.196 3.415 57.582 3.443 ;
     RECT  2.196 3.443 56.718 4.801 ;
     RECT  2.196 4.801 56.754 4.987 ;
     RECT  57.564 3.443 57.582 4.987 ;
     RECT  2.196 4.987 57.582 5.765 ;
     RECT  2.376 5.765 57.582 6.683 ;
     RECT  2.412 6.683 57.582 6.845 ;
     RECT  2.415 6.845 57.582 8.131 ;
     RECT  2.196 8.131 57.582 11.641 ;
     RECT  2.196 11.641 57.618 11.777 ;
     RECT  57.564 11.777 57.618 11.933 ;
     RECT  2.196 11.777 56.718 11.984 ;
     RECT  57.564 11.933 57.582 12.281 ;
     RECT  2.196 11.984 38.754 12.829 ;
     RECT  39.492 11.984 56.718 12.829 ;
     RECT  2.196 12.829 56.718 13.739 ;
     RECT  2.196 13.739 56.538 14.477 ;
     RECT  2.196 14.477 56.178 15.179 ;
     RECT  2.196 15.179 55.926 16.555 ;
     RECT  2.196 16.555 56.106 17.136 ;
     RECT  2.214 17.136 2.376 17.148 ;
     RECT  2.394 17.136 2.592 17.148 ;
     RECT  2.61 17.136 2.772 17.148 ;
     RECT  2.79 17.136 2.952 17.148 ;
     RECT  2.97 17.136 3.168 17.148 ;
     RECT  3.186 17.136 3.348 17.148 ;
     RECT  3.366 17.136 3.528 17.148 ;
     RECT  3.546 17.136 3.744 17.148 ;
     RECT  3.762 17.136 3.924 17.148 ;
     RECT  3.942 17.136 4.104 17.148 ;
     RECT  4.122 17.136 4.32 17.148 ;
     RECT  4.338 17.136 4.5 17.148 ;
     RECT  4.518 17.136 4.68 17.148 ;
     RECT  4.698 17.136 4.896 17.148 ;
     RECT  4.914 17.136 5.076 17.148 ;
     RECT  5.094 17.136 5.256 17.148 ;
     RECT  5.274 17.136 5.472 17.148 ;
     RECT  5.49 17.136 5.652 17.148 ;
     RECT  5.67 17.136 5.832 17.148 ;
     RECT  5.85 17.136 6.048 17.148 ;
     RECT  6.066 17.136 6.228 17.148 ;
     RECT  6.246 17.136 6.408 17.148 ;
     RECT  6.426 17.136 6.624 17.148 ;
     RECT  6.642 17.136 6.804 17.148 ;
     RECT  6.822 17.136 6.984 17.148 ;
     RECT  7.002 17.136 7.2 17.148 ;
     RECT  7.218 17.136 7.38 17.148 ;
     RECT  7.398 17.136 7.56 17.148 ;
     RECT  7.578 17.136 7.776 17.148 ;
     RECT  7.794 17.136 7.956 17.148 ;
     RECT  7.974 17.136 8.136 17.148 ;
     RECT  8.154 17.136 8.352 17.148 ;
     RECT  8.37 17.136 8.532 17.148 ;
     RECT  8.55 17.136 8.712 17.148 ;
     RECT  8.73 17.136 8.928 17.148 ;
     RECT  8.946 17.136 9.108 17.148 ;
     RECT  9.126 17.136 9.288 17.148 ;
     RECT  9.306 17.136 9.504 17.148 ;
     RECT  9.522 17.136 9.684 17.148 ;
     RECT  9.702 17.136 9.864 17.148 ;
     RECT  9.882 17.136 10.08 17.148 ;
     RECT  10.098 17.136 10.26 17.148 ;
     RECT  10.278 17.136 10.44 17.148 ;
     RECT  10.458 17.136 10.656 17.148 ;
     RECT  10.674 17.136 10.836 17.148 ;
     RECT  10.854 17.136 11.016 17.148 ;
     RECT  11.034 17.136 11.232 17.148 ;
     RECT  11.25 17.136 11.412 17.148 ;
     RECT  11.43 17.136 11.592 17.148 ;
     RECT  11.61 17.136 11.808 17.148 ;
     RECT  11.826 17.136 11.988 17.148 ;
     RECT  12.006 17.136 12.168 17.148 ;
     RECT  12.186 17.136 12.348 17.148 ;
     RECT  12.366 17.136 12.564 17.148 ;
     RECT  12.582 17.136 12.744 17.148 ;
     RECT  12.762 17.136 12.924 17.148 ;
     RECT  12.942 17.136 13.14 17.148 ;
     RECT  13.158 17.136 13.32 17.148 ;
     RECT  13.338 17.136 13.5 17.148 ;
     RECT  13.518 17.136 13.716 17.148 ;
     RECT  13.734 17.136 13.896 17.148 ;
     RECT  13.914 17.136 14.076 17.148 ;
     RECT  14.094 17.136 14.292 17.148 ;
     RECT  14.31 17.136 14.472 17.148 ;
     RECT  14.49 17.136 14.652 17.148 ;
     RECT  14.67 17.136 14.868 17.148 ;
     RECT  14.886 17.136 15.048 17.148 ;
     RECT  15.066 17.136 15.228 17.148 ;
     RECT  15.246 17.136 15.444 17.148 ;
     RECT  15.462 17.136 15.624 17.148 ;
     RECT  15.642 17.136 15.804 17.148 ;
     RECT  15.822 17.136 16.02 17.148 ;
     RECT  16.038 17.136 16.2 17.148 ;
     RECT  16.218 17.136 16.38 17.148 ;
     RECT  16.398 17.136 16.596 17.148 ;
     RECT  16.614 17.136 16.776 17.148 ;
     RECT  16.794 17.136 16.956 17.148 ;
     RECT  16.974 17.136 17.172 17.148 ;
     RECT  17.19 17.136 17.352 17.148 ;
     RECT  17.37 17.136 17.532 17.148 ;
     RECT  17.55 17.136 17.748 17.148 ;
     RECT  17.766 17.136 17.928 17.148 ;
     RECT  17.946 17.136 18.108 17.148 ;
     RECT  18.126 17.136 18.324 17.148 ;
     RECT  18.342 17.136 18.504 17.148 ;
     RECT  18.522 17.136 18.684 17.148 ;
     RECT  18.702 17.136 18.9 17.148 ;
     RECT  18.918 17.136 19.08 17.148 ;
     RECT  19.098 17.136 19.26 17.148 ;
     RECT  19.278 17.136 19.476 17.148 ;
     RECT  19.494 17.136 19.656 17.148 ;
     RECT  19.674 17.136 19.836 17.148 ;
     RECT  19.854 17.136 20.052 17.148 ;
     RECT  20.07 17.136 20.232 17.148 ;
     RECT  20.25 17.136 20.412 17.148 ;
     RECT  20.43 17.136 20.628 17.148 ;
     RECT  20.646 17.136 20.808 17.148 ;
     RECT  20.826 17.136 20.988 17.148 ;
     RECT  21.006 17.136 21.204 17.148 ;
     RECT  21.222 17.136 21.384 17.148 ;
     RECT  21.402 17.136 21.564 17.148 ;
     RECT  21.582 17.136 21.78 17.148 ;
     RECT  21.798 17.136 21.96 17.148 ;
     RECT  21.978 17.136 22.14 17.148 ;
     RECT  22.158 17.136 22.356 17.148 ;
     RECT  22.374 17.136 22.536 17.148 ;
     RECT  22.554 17.136 22.716 17.148 ;
     RECT  22.734 17.136 22.932 17.148 ;
     RECT  22.95 17.136 23.112 17.148 ;
     RECT  23.13 17.136 23.292 17.148 ;
     RECT  23.31 17.136 23.508 17.148 ;
     RECT  23.526 17.136 23.688 17.148 ;
     RECT  23.706 17.136 23.868 17.148 ;
     RECT  23.886 17.136 24.084 17.148 ;
     RECT  24.102 17.136 24.264 17.148 ;
     RECT  24.282 17.136 24.444 17.148 ;
     RECT  24.462 17.136 24.66 17.148 ;
     RECT  24.678 17.136 24.84 17.148 ;
     RECT  24.858 17.136 25.02 17.148 ;
     RECT  25.038 17.136 25.236 17.148 ;
     RECT  25.254 17.136 25.416 17.148 ;
     RECT  25.434 17.136 25.596 17.148 ;
     RECT  25.614 17.136 25.776 17.148 ;
     RECT  25.794 17.136 25.992 17.148 ;
     RECT  26.01 17.136 26.172 17.148 ;
     RECT  26.19 17.136 26.352 17.148 ;
     RECT  26.37 17.136 26.568 17.148 ;
     RECT  26.586 17.136 26.748 17.148 ;
     RECT  26.766 17.136 26.928 17.148 ;
     RECT  26.946 17.136 27.144 17.148 ;
     RECT  27.162 17.136 27.324 17.148 ;
     RECT  27.342 17.136 27.504 17.148 ;
     RECT  27.522 17.136 27.72 17.148 ;
     RECT  27.738 17.136 27.9 17.148 ;
     RECT  27.918 17.136 28.08 17.148 ;
     RECT  28.098 17.136 28.296 17.148 ;
     RECT  28.314 17.136 28.476 17.148 ;
     RECT  28.494 17.136 28.656 17.148 ;
     RECT  28.674 17.136 28.872 17.148 ;
     RECT  28.89 17.136 29.052 17.148 ;
     RECT  29.07 17.136 29.232 17.148 ;
     RECT  29.25 17.136 29.448 17.148 ;
     RECT  29.466 17.136 29.628 17.148 ;
     RECT  29.646 17.136 29.808 17.148 ;
     RECT  29.826 17.136 30.024 17.148 ;
     RECT  30.042 17.136 30.204 17.148 ;
     RECT  30.222 17.136 30.384 17.148 ;
     RECT  30.402 17.136 30.6 17.148 ;
     RECT  30.618 17.136 30.78 17.148 ;
     RECT  30.798 17.136 30.96 17.148 ;
     RECT  30.978 17.136 31.176 17.148 ;
     RECT  31.194 17.136 31.356 17.148 ;
     RECT  31.374 17.136 31.536 17.148 ;
     RECT  31.554 17.136 31.752 17.148 ;
     RECT  31.77 17.136 31.932 17.148 ;
     RECT  31.95 17.136 32.112 17.148 ;
     RECT  32.13 17.136 32.328 17.148 ;
     RECT  32.346 17.136 32.508 17.148 ;
     RECT  32.526 17.136 32.688 17.148 ;
     RECT  32.706 17.136 32.904 17.148 ;
     RECT  32.922 17.136 33.084 17.148 ;
     RECT  33.102 17.136 33.264 17.148 ;
     RECT  33.282 17.136 33.48 17.148 ;
     RECT  33.498 17.136 33.66 17.148 ;
     RECT  33.678 17.136 33.84 17.148 ;
     RECT  33.858 17.136 34.056 17.148 ;
     RECT  34.074 17.136 34.236 17.148 ;
     RECT  34.254 17.136 34.416 17.148 ;
     RECT  34.434 17.136 34.632 17.148 ;
     RECT  34.65 17.136 34.812 17.148 ;
     RECT  34.83 17.136 34.992 17.148 ;
     RECT  35.01 17.136 35.208 17.148 ;
     RECT  35.226 17.136 35.388 17.148 ;
     RECT  35.406 17.136 35.568 17.148 ;
     RECT  35.586 17.136 35.784 17.148 ;
     RECT  35.802 17.136 35.964 17.148 ;
     RECT  35.982 17.136 36.144 17.148 ;
     RECT  36.162 17.136 36.36 17.148 ;
     RECT  36.378 17.136 36.54 17.148 ;
     RECT  36.558 17.136 36.72 17.148 ;
     RECT  36.738 17.136 36.936 17.148 ;
     RECT  36.954 17.136 37.116 17.148 ;
     RECT  37.134 17.136 37.296 17.148 ;
     RECT  37.314 17.136 37.512 17.148 ;
     RECT  37.53 17.136 37.692 17.148 ;
     RECT  37.71 17.136 37.872 17.148 ;
     RECT  37.89 17.136 38.088 17.148 ;
     RECT  38.106 17.136 38.268 17.148 ;
     RECT  38.286 17.136 38.448 17.148 ;
     RECT  38.466 17.136 38.664 17.148 ;
     RECT  38.682 17.136 38.844 17.148 ;
     RECT  38.862 17.136 39.024 17.148 ;
     RECT  39.042 17.136 39.24 17.148 ;
     RECT  39.258 17.136 39.42 17.148 ;
     RECT  39.438 17.136 39.6 17.148 ;
     RECT  39.618 17.136 39.78 17.148 ;
     RECT  39.798 17.136 39.996 17.148 ;
     RECT  40.014 17.136 40.176 17.148 ;
     RECT  40.194 17.136 40.356 17.148 ;
     RECT  40.374 17.136 40.572 17.148 ;
     RECT  40.59 17.136 40.752 17.148 ;
     RECT  40.77 17.136 40.932 17.148 ;
     RECT  40.95 17.136 41.148 17.148 ;
     RECT  41.166 17.136 41.328 17.148 ;
     RECT  41.346 17.136 41.508 17.148 ;
     RECT  41.526 17.136 41.724 17.148 ;
     RECT  41.742 17.136 41.904 17.148 ;
     RECT  41.922 17.136 42.084 17.148 ;
     RECT  42.102 17.136 42.3 17.148 ;
     RECT  42.318 17.136 42.48 17.148 ;
     RECT  42.498 17.136 42.66 17.148 ;
     RECT  42.678 17.136 42.876 17.148 ;
     RECT  42.894 17.136 43.056 17.148 ;
     RECT  43.074 17.136 43.236 17.148 ;
     RECT  43.254 17.136 43.452 17.148 ;
     RECT  43.47 17.136 43.632 17.148 ;
     RECT  43.65 17.136 43.812 17.148 ;
     RECT  43.83 17.136 44.028 17.148 ;
     RECT  44.046 17.136 44.208 17.148 ;
     RECT  44.226 17.136 44.388 17.148 ;
     RECT  44.406 17.136 44.604 17.148 ;
     RECT  44.622 17.136 44.784 17.148 ;
     RECT  44.802 17.136 44.964 17.148 ;
     RECT  44.982 17.136 45.18 17.148 ;
     RECT  45.198 17.136 45.36 17.148 ;
     RECT  45.378 17.136 45.54 17.148 ;
     RECT  45.558 17.136 45.756 17.148 ;
     RECT  45.774 17.136 45.936 17.148 ;
     RECT  45.954 17.136 46.116 17.148 ;
     RECT  46.134 17.136 46.332 17.148 ;
     RECT  46.35 17.136 46.512 17.148 ;
     RECT  46.53 17.136 46.692 17.148 ;
     RECT  46.71 17.136 46.908 17.148 ;
     RECT  46.926 17.136 47.088 17.148 ;
     RECT  47.106 17.136 47.268 17.148 ;
     RECT  47.286 17.136 47.484 17.148 ;
     RECT  47.502 17.136 47.664 17.148 ;
     RECT  47.682 17.136 47.844 17.148 ;
     RECT  47.862 17.136 48.06 17.148 ;
     RECT  48.078 17.136 48.24 17.148 ;
     RECT  48.258 17.136 48.42 17.148 ;
     RECT  48.438 17.136 48.636 17.148 ;
     RECT  48.654 17.136 48.816 17.148 ;
     RECT  48.834 17.136 48.996 17.148 ;
     RECT  49.014 17.136 49.212 17.148 ;
     RECT  49.23 17.136 49.392 17.148 ;
     RECT  49.41 17.136 49.572 17.148 ;
     RECT  49.59 17.136 49.788 17.148 ;
     RECT  49.806 17.136 49.968 17.148 ;
     RECT  49.986 17.136 50.148 17.148 ;
     RECT  50.166 17.136 50.364 17.148 ;
     RECT  50.382 17.136 50.544 17.148 ;
     RECT  50.562 17.136 50.724 17.148 ;
     RECT  50.742 17.136 50.94 17.148 ;
     RECT  50.958 17.136 51.12 17.148 ;
     RECT  51.138 17.136 51.3 17.148 ;
     RECT  51.318 17.136 51.516 17.148 ;
     RECT  51.534 17.136 51.696 17.148 ;
     RECT  51.714 17.136 51.876 17.148 ;
     RECT  51.894 17.136 52.092 17.148 ;
     RECT  52.11 17.136 52.272 17.148 ;
     RECT  52.29 17.136 52.452 17.148 ;
     RECT  52.47 17.136 52.668 17.148 ;
     RECT  52.686 17.136 52.848 17.148 ;
     RECT  52.866 17.136 53.028 17.148 ;
     RECT  53.046 17.136 53.208 17.148 ;
     RECT  53.226 17.136 53.424 17.148 ;
     RECT  53.442 17.136 53.604 17.148 ;
     RECT  53.622 17.136 53.784 17.148 ;
     RECT  53.802 17.136 54 17.148 ;
     RECT  54.018 17.136 54.18 17.148 ;
     RECT  54.198 17.136 54.36 17.148 ;
     RECT  54.378 17.136 54.576 17.148 ;
     RECT  54.594 17.136 54.756 17.148 ;
     RECT  54.774 17.136 54.936 17.148 ;
     RECT  54.954 17.136 55.152 17.148 ;
     RECT  55.17 17.136 55.332 17.148 ;
     RECT  55.35 17.136 55.512 17.148 ;
     RECT  55.53 17.136 55.728 17.148 ;
     RECT  55.746 17.136 55.908 17.148 ;
     RECT  55.926 17.136 56.088 17.148 ;
     RECT  10.116 17.148 10.206 17.213 ;
     RECT  13.356 17.148 13.446 17.213 ;
     RECT  31.968 17.148 32.058 17.213 ;
     RECT  37.152 17.148 37.242 17.213 ;
     RECT  40.608 17.148 40.698 17.213 ;
     RECT  44.244 17.148 44.334 17.213 ;
    LAYER M4 ;
     RECT  2.329 4.128 2.365 4.152 ;
     RECT  2.365 1.728 2.401 1.752 ;
     RECT  2.365 3.408 2.401 4.152 ;
     RECT  2.401 1.728 2.408 4.152 ;
     RECT  2.285 5.136 2.408 5.16 ;
     RECT  2.293 16.56 2.485 16.584 ;
     RECT  2.408 1.728 2.677 15.132 ;
     RECT  2.677 1.728 2.704 15.24 ;
     RECT  2.485 0.192 2.819 0.216 ;
     RECT  2.704 1.728 2.819 5.208 ;
     RECT  2.704 15.216 2.819 15.24 ;
     RECT  2.485 16.56 3.125 16.632 ;
     RECT  2.704 9.072 3.413 10.872 ;
     RECT  3.125 16.608 3.485 16.632 ;
     RECT  2.819 1.728 3.805 3.624 ;
     RECT  2.819 4.656 3.805 5.208 ;
     RECT  2.704 12.48 3.829 12.504 ;
     RECT  2.704 6.864 3.877 6.888 ;
     RECT  2.704 7.872 3.877 7.896 ;
     RECT  3.805 1.728 4.021 5.208 ;
     RECT  3.829 14.832 4.021 14.856 ;
     RECT  4.021 0.576 4.169 0.6 ;
     RECT  4.021 1.728 4.213 5.304 ;
     RECT  4.213 1.728 4.301 5.736 ;
     RECT  3.877 6.864 4.301 7.896 ;
     RECT  3.829 12.48 4.453 12.888 ;
     RECT  4.301 1.728 4.561 7.896 ;
     RECT  4.453 12.48 4.597 13.704 ;
     RECT  4.561 1.152 4.777 7.896 ;
     RECT  4.597 11.952 4.789 13.704 ;
     RECT  4.777 1.152 4.837 7.992 ;
     RECT  3.413 9.072 4.837 10.248 ;
     RECT  4.021 14.832 4.981 15.432 ;
     RECT  4.981 14.832 5.068 16.008 ;
     RECT  4.837 1.152 5.108 10.248 ;
     RECT  4.789 11.76 5.108 13.704 ;
     RECT  5.068 14.832 5.108 15.432 ;
     RECT  5.108 1.152 5.173 15.432 ;
     RECT  5.173 0.192 5.285 15.432 ;
     RECT  5.285 0.192 5.404 15.24 ;
     RECT  5.404 14.208 5.717 15.24 ;
     RECT  5.404 0.192 5.789 8.472 ;
     RECT  5.789 0.192 5.891 7.752 ;
     RECT  5.404 9.6 5.897 9.624 ;
     RECT  5.404 10.848 6.085 13.032 ;
     RECT  5.891 1.728 6.221 7.752 ;
     RECT  6.085 11.424 6.373 13.032 ;
     RECT  5.891 0.192 6.409 0.216 ;
     RECT  5.717 14.208 6.709 15 ;
     RECT  6.373 11.472 6.721 13.032 ;
     RECT  6.709 14.208 6.721 15.048 ;
     RECT  6.721 11.472 6.797 15.048 ;
     RECT  5.941 16.56 6.901 16.584 ;
     RECT  6.901 15.984 7.121 16.584 ;
     RECT  6.221 2.064 7.808 7.752 ;
     RECT  7.477 8.736 7.808 8.76 ;
     RECT  6.797 11.472 7.808 14.952 ;
     RECT  7.121 15.984 7.808 16.008 ;
     RECT  7.429 0.288 8.053 0.312 ;
     RECT  7.808 2.064 8.104 16.008 ;
     RECT  8.053 0.288 8.197 1.032 ;
     RECT  8.104 2.064 8.197 8.568 ;
     RECT  8.197 0.288 8.243 8.568 ;
     RECT  8.104 11.424 8.243 16.008 ;
     RECT  8.243 0.384 8.339 8.568 ;
     RECT  8.339 0.384 8.435 0.408 ;
     RECT  8.243 15.984 8.437 16.008 ;
     RECT  8.437 15.984 8.525 16.584 ;
     RECT  8.525 15.984 8.716 16.008 ;
     RECT  8.243 11.424 8.741 14.856 ;
     RECT  8.339 2.064 9.029 8.568 ;
     RECT  9.089 10.272 9.173 10.296 ;
     RECT  8.741 13.68 9.281 14.856 ;
     RECT  9.281 14.256 9.299 14.856 ;
     RECT  9.029 2.064 9.347 8.52 ;
     RECT  9.299 14.832 9.397 14.856 ;
     RECT  9.205 0.288 9.587 0.312 ;
     RECT  9.397 14.832 9.74 15.096 ;
     RECT  8.741 11.424 9.973 11.976 ;
     RECT  9.347 2.064 10.241 7.752 ;
     RECT  9.74 14.832 10.309 16.008 ;
     RECT  10.309 14.112 10.505 16.008 ;
     RECT  10.241 1.2 10.508 7.752 ;
     RECT  9.589 9.6 10.508 9.72 ;
     RECT  9.973 11.376 10.508 11.976 ;
     RECT  10.505 14.112 10.508 15.288 ;
     RECT  10.508 1.2 10.595 15.288 ;
     RECT  10.595 1.2 10.721 15.24 ;
     RECT  9.589 0.192 10.741 0.216 ;
     RECT  10.721 2.418 10.787 15.24 ;
     RECT  10.787 2.418 10.804 15.096 ;
     RECT  10.804 2.784 10.865 7.752 ;
     RECT  10.804 10.704 10.945 12.024 ;
     RECT  10.741 0.192 11.219 1.176 ;
     RECT  11.219 0.192 11.267 0.216 ;
     RECT  10.804 9.6 11.513 9.624 ;
     RECT  10.865 2.832 11.845 7.752 ;
     RECT  10.804 13.68 11.917 15.096 ;
     RECT  11.917 13.68 11.987 13.704 ;
     RECT  10.945 10.704 12.661 11.928 ;
     RECT  11.845 2.256 12.668 7.752 ;
     RECT  12.661 10.704 12.769 11.976 ;
     RECT  12.049 13.104 12.769 13.128 ;
     RECT  11.917 14.784 13.165 15.096 ;
     RECT  12.668 2.256 13.208 8.52 ;
     RECT  12.769 10.704 13.208 13.128 ;
     RECT  13.165 14.736 13.208 15.096 ;
     RECT  13.208 2.148 13.237 15.132 ;
     RECT  13.237 2.148 13.312 15.288 ;
     RECT  13.312 2.256 13.504 15.288 ;
     RECT  13.504 2.256 13.645 9.144 ;
     RECT  13.093 0.288 13.669 0.312 ;
     RECT  13.504 13.104 13.673 15.288 ;
     RECT  13.669 0.288 13.715 1.272 ;
     RECT  13.645 2.256 13.781 8.568 ;
     RECT  13.621 16.56 13.813 16.584 ;
     RECT  13.717 0.192 13.859 0.216 ;
     RECT  13.673 13.104 13.859 14.856 ;
     RECT  13.813 15.984 13.9 16.584 ;
     RECT  13.715 1.248 13.907 1.272 ;
     RECT  13.781 4.992 14.099 8.568 ;
     RECT  13.859 13.104 14.149 13.224 ;
     RECT  14.099 4.992 14.243 7.752 ;
     RECT  14.149 13.104 14.387 13.176 ;
     RECT  13.504 10.704 14.645 11.976 ;
     RECT  14.645 10.848 14.723 11.976 ;
     RECT  13.859 14.496 14.773 14.856 ;
     RECT  13.9 16.56 14.789 16.584 ;
     RECT  13.781 2.256 15.109 3.96 ;
     RECT  14.243 5.04 15.157 7.752 ;
     RECT  14.773 14.496 15.157 15.096 ;
     RECT  15.157 5.04 15.289 7.992 ;
     RECT  15.289 5.04 15.317 8.472 ;
     RECT  15.109 2.256 15.349 4.008 ;
     RECT  15.317 5.04 15.349 8.568 ;
     RECT  15.157 14.496 15.541 15.24 ;
     RECT  14.387 13.104 15.569 13.128 ;
     RECT  15.541 14.496 15.569 15.288 ;
     RECT  15.349 0.288 15.685 0.312 ;
     RECT  15.569 13.104 15.829 15.288 ;
     RECT  15.349 2.256 15.908 8.568 ;
     RECT  14.723 11.664 15.908 11.976 ;
     RECT  15.829 13.104 15.908 15.384 ;
     RECT  15.908 2.148 16.204 15.384 ;
     RECT  16.204 13.104 16.261 15.384 ;
     RECT  16.204 11.472 16.265 11.784 ;
     RECT  16.261 13.104 16.265 16.008 ;
     RECT  15.685 0.288 16.309 0.36 ;
     RECT  16.309 0.192 16.357 0.36 ;
     RECT  16.204 2.148 16.357 9.096 ;
     RECT  16.265 11.472 16.481 11.688 ;
     RECT  16.265 13.104 16.625 13.704 ;
     RECT  16.357 0.192 16.931 9.096 ;
     RECT  16.931 2.832 17.129 9.096 ;
     RECT  17.129 9.072 17.197 9.096 ;
     RECT  16.625 13.104 17.209 13.128 ;
     RECT  17.129 2.832 17.315 8.04 ;
     RECT  16.931 0.192 17.363 1.176 ;
     RECT  17.315 2.832 17.381 7.56 ;
     RECT  16.265 14.832 17.417 16.008 ;
     RECT  17.197 9.072 17.555 9.144 ;
     RECT  16.481 11.472 17.557 11.544 ;
     RECT  17.417 14.832 17.953 15.384 ;
     RECT  17.953 14.256 18.061 15.384 ;
     RECT  17.363 0.192 18.083 0.216 ;
     RECT  17.989 16.56 18.137 16.584 ;
     RECT  17.381 3.84 18.277 7.56 ;
     RECT  17.557 11.424 18.373 11.544 ;
     RECT  18.373 11.424 18.469 11.688 ;
     RECT  17.989 2.688 18.608 2.712 ;
     RECT  18.277 3.84 18.608 7.992 ;
     RECT  17.555 9.072 18.608 9.096 ;
     RECT  17.797 10.32 18.608 10.344 ;
     RECT  18.469 11.424 18.608 11.976 ;
     RECT  18.061 13.68 18.608 15.384 ;
     RECT  18.608 2.148 18.712 15.384 ;
     RECT  18.712 2.418 18.904 15.384 ;
     RECT  18.904 10.8 18.965 15.384 ;
     RECT  18.469 0.288 18.997 0.312 ;
     RECT  18.997 0.288 19.235 1.272 ;
     RECT  18.965 10.8 19.297 15.24 ;
     RECT  19.297 11.424 19.397 15.24 ;
     RECT  19.235 0.288 19.573 1.176 ;
     RECT  19.397 11.424 19.693 15.144 ;
     RECT  19.693 11.424 19.765 13.752 ;
     RECT  18.904 2.784 20.149 7.224 ;
     RECT  20.149 2.784 20.221 7.992 ;
     RECT  20.221 2.784 20.305 8.568 ;
     RECT  20.005 10.224 20.339 10.248 ;
     RECT  20.305 2.784 20.401 7.992 ;
     RECT  20.293 16.56 20.405 16.584 ;
     RECT  19.693 14.832 20.677 15.144 ;
     RECT  20.677 14.832 21.017 15.432 ;
     RECT  19.765 13.008 21.109 13.752 ;
     RECT  21.017 14.832 21.109 15.384 ;
     RECT  19.573 0.192 21.164 1.176 ;
     RECT  20.401 2.496 21.164 7.992 ;
     RECT  21.164 0.192 21.251 7.992 ;
     RECT  21.251 2.148 21.308 7.992 ;
     RECT  20.485 9.072 21.308 9.432 ;
     RECT  19.765 11.424 21.308 11.976 ;
     RECT  21.109 13.008 21.308 15.384 ;
     RECT  21.308 2.148 21.412 15.384 ;
     RECT  21.412 2.256 21.491 15.384 ;
     RECT  21.491 2.256 21.604 15.288 ;
     RECT  21.604 2.256 21.701 9.096 ;
     RECT  21.701 9.024 21.989 9.096 ;
     RECT  21.251 0.192 22.019 1.176 ;
     RECT  21.701 2.256 22.115 7.992 ;
     RECT  22.019 0.192 22.124 0.408 ;
     RECT  22.124 0.144 22.211 0.408 ;
     RECT  21.604 14.256 22.211 15.288 ;
     RECT  21.604 11.424 22.241 12.552 ;
     RECT  22.211 0.192 22.355 0.408 ;
     RECT  22.211 14.256 22.853 15.192 ;
     RECT  21.989 9.024 22.957 9.048 ;
     RECT  22.355 0.192 22.979 0.216 ;
     RECT  22.115 2.64 22.981 7.992 ;
     RECT  22.981 2.64 23.137 8.04 ;
     RECT  23.137 1.728 23.317 8.04 ;
     RECT  22.957 9.024 23.317 9.096 ;
     RECT  23.413 0.288 23.698 0.312 ;
     RECT  22.241 12 23.749 12.552 ;
     RECT  22.853 14.256 23.941 15.096 ;
     RECT  23.698 0.288 23.989 0.36 ;
     RECT  23.317 1.728 24.008 9.096 ;
     RECT  23.353 10.848 24.008 10.872 ;
     RECT  23.749 11.952 24.008 12.552 ;
     RECT  23.941 14.256 24.008 15.288 ;
     RECT  24.008 1.728 24.133 15.288 ;
     RECT  23.989 0.192 24.181 0.36 ;
     RECT  24.133 1.728 24.304 15.336 ;
     RECT  24.181 0.192 24.419 0.408 ;
     RECT  24.419 0.192 24.515 0.216 ;
     RECT  24.304 14.256 24.517 15.336 ;
     RECT  24.517 14.256 24.553 16.008 ;
     RECT  24.553 14.4 24.797 16.008 ;
     RECT  24.304 9.648 24.851 9.672 ;
     RECT  24.304 1.728 25.441 8.28 ;
     RECT  25.477 0.192 25.57 0.216 ;
     RECT  25.57 0.144 25.571 0.216 ;
     RECT  24.304 11.472 25.597 13.128 ;
     RECT  24.797 14.4 25.657 15.336 ;
     RECT  25.657 14.256 25.741 15.336 ;
     RECT  25.597 11.472 25.837 12.552 ;
     RECT  25.441 1.728 25.981 8.52 ;
     RECT  25.741 14.832 26.245 15.336 ;
     RECT  26.245 14.832 26.489 15.432 ;
     RECT  25.571 0.144 26.533 0.168 ;
     RECT  26.533 0.144 26.627 0.312 ;
     RECT  25.981 1.68 26.633 8.52 ;
     RECT  26.633 2.148 26.708 8.52 ;
     RECT  26.101 9.696 26.708 9.72 ;
     RECT  25.837 11.424 26.708 12.552 ;
     RECT  26.489 14.832 26.708 15.384 ;
     RECT  26.708 2.148 26.812 15.384 ;
     RECT  26.812 2.418 27.004 15.384 ;
     RECT  27.004 2.688 27.137 9.432 ;
     RECT  26.627 0.192 27.205 0.312 ;
     RECT  27.205 0.192 27.347 1.176 ;
     RECT  27.004 13.104 27.347 15.384 ;
     RECT  27.347 13.104 27.353 15.336 ;
     RECT  27.137 3.84 27.395 9.432 ;
     RECT  27.395 3.888 27.425 9.432 ;
     RECT  27.353 13.104 27.587 15.288 ;
     RECT  27.004 11.424 27.793 11.976 ;
     RECT  27.137 2.688 28.021 2.712 ;
     RECT  27.425 3.936 28.109 9.432 ;
     RECT  27.347 0.192 28.163 0.312 ;
     RECT  28.021 1.728 28.397 2.712 ;
     RECT  28.163 0.24 28.403 0.312 ;
     RECT  27.587 13.68 28.505 15.288 ;
     RECT  28.109 3.936 28.573 9.096 ;
     RECT  28.549 16.56 28.793 16.584 ;
     RECT  28.397 1.728 28.901 1.752 ;
     RECT  27.793 11.952 28.969 11.976 ;
     RECT  28.969 11.952 29.077 12.504 ;
     RECT  28.429 10.848 29.125 10.872 ;
     RECT  29.077 11.952 29.125 12.552 ;
     RECT  28.403 0.24 29.269 0.264 ;
     RECT  28.573 3.072 29.408 9.096 ;
     RECT  29.125 10.848 29.408 12.552 ;
     RECT  28.505 13.68 29.408 15.24 ;
     RECT  29.408 2.148 29.509 15.24 ;
     RECT  29.509 2.148 29.701 15.288 ;
     RECT  29.701 2.148 29.704 15.336 ;
     RECT  29.704 14.256 29.843 15.336 ;
     RECT  29.269 0.192 29.869 0.264 ;
     RECT  29.704 11.712 29.987 13.128 ;
     RECT  29.843 14.256 30.227 15.288 ;
     RECT  29.704 2.148 30.325 8.568 ;
     RECT  30.325 1.728 30.371 8.568 ;
     RECT  29.987 11.712 30.371 12.264 ;
     RECT  30.371 3.216 30.457 8.568 ;
     RECT  30.371 11.712 30.853 12.072 ;
     RECT  30.457 3.216 30.899 8.52 ;
     RECT  29.869 0.192 30.901 0.312 ;
     RECT  30.371 1.728 30.901 1.752 ;
     RECT  30.899 3.408 30.953 8.472 ;
     RECT  30.901 0.192 31.043 1.752 ;
     RECT  30.227 14.832 31.237 15.288 ;
     RECT  31.237 14.256 31.285 15.288 ;
     RECT  30.853 11.424 31.333 12.072 ;
     RECT  31.043 1.728 31.385 1.752 ;
     RECT  31.333 10.896 31.777 12.072 ;
     RECT  31.285 13.344 31.777 15.288 ;
     RECT  31.777 10.896 31.949 15.288 ;
     RECT  31.949 10.848 31.957 15.288 ;
     RECT  31.909 2.148 32.065 2.328 ;
     RECT  30.953 3.408 32.065 8.184 ;
     RECT  32.065 2.148 32.108 8.184 ;
     RECT  31.957 10.848 32.108 15.384 ;
     RECT  31.045 16.56 32.243 16.584 ;
     RECT  31.043 0.192 32.291 0.408 ;
     RECT  32.108 2.148 32.404 15.384 ;
     RECT  32.404 2.148 32.437 7.992 ;
     RECT  32.404 10.896 32.465 15.384 ;
     RECT  32.291 0.288 32.531 0.408 ;
     RECT  32.561 15.936 32.645 15.96 ;
     RECT  32.465 10.896 32.789 14.952 ;
     RECT  32.437 2.016 32.821 7.992 ;
     RECT  32.821 1.152 33.011 7.992 ;
     RECT  32.789 11.376 33.541 14.952 ;
     RECT  33.541 11.376 33.581 15.096 ;
     RECT  33.011 1.968 33.589 7.992 ;
     RECT  32.404 9.504 33.589 9.528 ;
     RECT  33.581 11.376 33.833 11.976 ;
     RECT  33.973 0.192 34.085 0.216 ;
     RECT  33.581 13.344 34.549 15.096 ;
     RECT  33.589 1.968 34.808 9.528 ;
     RECT  33.833 11.376 34.808 11.88 ;
     RECT  34.549 13.104 34.808 15.096 ;
     RECT  34.808 1.968 34.885 15.132 ;
     RECT  34.885 1.968 35.077 15.288 ;
     RECT  35.077 1.968 35.104 15.384 ;
     RECT  34.501 0.288 35.125 0.312 ;
     RECT  35.104 12.528 35.219 15.384 ;
     RECT  35.125 0.192 35.267 0.312 ;
     RECT  35.219 12.528 35.267 15.288 ;
     RECT  35.267 12.528 35.425 15 ;
     RECT  35.267 0.288 35.507 0.312 ;
     RECT  35.104 1.968 35.989 9.528 ;
     RECT  35.425 12.528 36.109 13.368 ;
     RECT  36.037 16.56 36.229 16.584 ;
     RECT  36.229 15.984 36.245 16.584 ;
     RECT  35.989 1.728 36.313 9.528 ;
     RECT  36.245 15.984 36.316 16.008 ;
     RECT  35.104 11.328 36.421 11.496 ;
     RECT  36.313 1.728 36.467 9.72 ;
     RECT  35.425 14.4 36.613 15 ;
     RECT  36.421 11.328 36.781 12.024 ;
     RECT  36.781 10.944 36.853 12.024 ;
     RECT  36.109 13.344 36.961 13.368 ;
     RECT  36.613 14.4 36.961 15.432 ;
     RECT  36.467 1.728 37.508 8.568 ;
     RECT  36.467 9.696 37.508 9.72 ;
     RECT  36.853 10.848 37.508 12.024 ;
     RECT  36.961 13.344 37.508 15.432 ;
     RECT  37.333 0.192 37.621 0.216 ;
     RECT  37.508 1.728 37.765 15.432 ;
     RECT  37.765 1.728 37.804 16.008 ;
     RECT  37.804 1.728 38.003 7.992 ;
     RECT  37.621 0.192 38.005 0.312 ;
     RECT  38.003 1.728 38.005 7.752 ;
     RECT  37.804 11.328 38.189 16.008 ;
     RECT  38.005 0.192 38.195 7.752 ;
     RECT  38.189 11.328 38.483 15.144 ;
     RECT  38.195 1.728 38.585 7.752 ;
     RECT  38.483 11.328 38.675 12.024 ;
     RECT  38.195 0.192 38.819 0.216 ;
     RECT  38.483 13.056 38.873 15.144 ;
     RECT  38.917 10.224 39.017 10.248 ;
     RECT  38.675 11.328 39.053 11.976 ;
     RECT  38.585 1.968 39.125 7.752 ;
     RECT  37.804 8.976 39.301 9 ;
     RECT  38.873 14.112 39.493 15.144 ;
     RECT  39.125 2.064 39.877 7.752 ;
     RECT  39.301 8.976 39.877 9.144 ;
     RECT  39.493 14.112 40.021 15.24 ;
     RECT  39.877 2.064 40.208 9.144 ;
     RECT  39.053 11.376 40.208 11.976 ;
     RECT  38.873 13.056 40.208 13.08 ;
     RECT  40.021 14.112 40.208 15.336 ;
     RECT  39.493 0.288 40.213 0.6 ;
     RECT  40.208 2.064 40.301 15.336 ;
     RECT  40.301 1.728 40.453 15.336 ;
     RECT  40.453 1.728 40.504 16.008 ;
     RECT  40.213 0.144 40.597 0.6 ;
     RECT  40.504 1.728 40.597 9.672 ;
     RECT  40.504 11.952 40.637 16.008 ;
     RECT  40.637 12.528 40.835 16.008 ;
     RECT  40.835 14.112 40.925 16.008 ;
     RECT  40.835 12.528 41.507 13.128 ;
     RECT  41.507 12.528 41.833 13.08 ;
     RECT  41.797 11.424 42.373 11.448 ;
     RECT  40.597 0.144 42.563 9.672 ;
     RECT  42.373 11.424 42.757 11.496 ;
     RECT  42.563 1.728 42.908 9.672 ;
     RECT  42.757 11.232 42.908 11.496 ;
     RECT  41.833 13.056 42.908 13.08 ;
     RECT  40.925 14.112 42.908 15.432 ;
     RECT  42.908 1.728 43.187 15.432 ;
     RECT  43.187 1.728 43.204 15.384 ;
     RECT  43.204 10.704 43.841 12.312 ;
     RECT  42.563 0.144 43.873 0.312 ;
     RECT  43.204 1.728 43.873 9.672 ;
     RECT  43.841 10.848 43.993 12.312 ;
     RECT  43.873 0.144 44.003 9.672 ;
     RECT  43.204 14.208 44.093 15.384 ;
     RECT  44.003 0.144 44.147 7.992 ;
     RECT  44.003 9.024 44.195 9.672 ;
     RECT  44.093 14.208 44.489 15.336 ;
     RECT  44.489 14.208 44.521 15.288 ;
     RECT  44.521 14.112 44.629 15.288 ;
     RECT  44.147 0.144 45.301 0.312 ;
     RECT  45.301 0.144 45.388 0.36 ;
     RECT  45.388 0.144 45.397 0.408 ;
     RECT  44.147 1.728 45.397 7.992 ;
     RECT  45.397 0.144 45.539 7.992 ;
     RECT  44.629 13.632 45.604 15.288 ;
     RECT  45.539 1.92 45.608 7.992 ;
     RECT  44.195 9.024 45.608 9.096 ;
     RECT  43.993 11.328 45.608 12.312 ;
     RECT  45.604 13.632 45.608 15.336 ;
     RECT  45.608 1.92 45.904 15.336 ;
     RECT  45.904 13.632 46.019 15.336 ;
     RECT  46.019 13.632 46.145 15.288 ;
     RECT  45.904 10.752 46.259 12.552 ;
     RECT  45.904 1.92 46.361 9.432 ;
     RECT  46.361 1.92 46.835 9.096 ;
     RECT  46.145 13.632 47.173 15.24 ;
     RECT  45.539 0.144 47.269 0.888 ;
     RECT  46.835 1.92 47.269 8.568 ;
     RECT  47.269 0.144 47.459 8.568 ;
     RECT  47.173 13.632 47.557 15.288 ;
     RECT  47.365 9.6 47.653 9.672 ;
     RECT  46.259 10.752 47.653 12.264 ;
     RECT  47.459 0.192 48.181 8.568 ;
     RECT  47.653 9.6 48.181 12.264 ;
     RECT  48.181 0.192 48.308 12.264 ;
     RECT  47.557 13.632 48.308 15.432 ;
     RECT  48.308 0.192 48.709 15.432 ;
     RECT  48.709 0.144 48.953 15.432 ;
     RECT  48.953 0.144 49.571 15.288 ;
     RECT  49.571 0.144 49.667 12.6 ;
     RECT  49.571 13.632 50.749 15.288 ;
     RECT  49.667 0.144 51.008 12.552 ;
     RECT  50.749 13.632 51.008 15.336 ;
     RECT  51.008 0.144 51.059 15.336 ;
     RECT  51.059 0.144 51.473 15.288 ;
     RECT  51.397 16.56 51.509 16.584 ;
     RECT  51.473 0.144 51.875 15.24 ;
     RECT  51.875 0.144 52.787 12.312 ;
     RECT  51.875 13.632 53.317 15.24 ;
     RECT  53.317 13.632 53.489 16.008 ;
     RECT  52.787 0.288 53.549 12.312 ;
     RECT  53.549 0.288 53.708 12.552 ;
     RECT  53.489 13.632 53.708 15.288 ;
     RECT  53.708 0.288 53.797 15.288 ;
     RECT  53.797 0.192 54.889 15.288 ;
     RECT  54.889 0.192 55.004 16.008 ;
     RECT  55.004 0.144 55.139 16.008 ;
     RECT  55.139 7.632 55.324 16.008 ;
     RECT  55.139 0.144 55.325 6.648 ;
     RECT  55.324 15.984 55.357 16.008 ;
     RECT  55.324 7.632 55.379 14.952 ;
     RECT  55.325 0.144 55.427 6.36 ;
     RECT  55.427 1.392 55.469 6.36 ;
     RECT  55.357 15.984 55.475 16.056 ;
     RECT  55.379 8.736 55.571 14.952 ;
     RECT  55.571 9.024 55.793 14.952 ;
     RECT  55.469 1.392 55.901 6.168 ;
     RECT  55.475 16.032 55.909 16.056 ;
     RECT  55.793 9.072 55.955 14.952 ;
     RECT  55.909 16.032 55.955 16.68 ;
     RECT  55.955 9.072 55.973 9.816 ;
     RECT  55.955 10.8 56.003 14.952 ;
     RECT  55.901 1.92 56.009 6.168 ;
     RECT  55.427 0.144 56.051 0.216 ;
     RECT  55.973 9.552 56.051 9.816 ;
     RECT  55.955 16.56 56.051 16.68 ;
     RECT  56.003 10.896 56.053 14.952 ;
     RECT  56.051 9.552 56.117 9.576 ;
     RECT  56.051 16.56 56.117 16.584 ;
     RECT  56.009 1.92 56.195 6.12 ;
     RECT  55.379 7.632 56.225 7.656 ;
     RECT  56.051 0.192 56.291 0.216 ;
     RECT  56.053 10.896 56.291 12.312 ;
     RECT  56.053 13.824 56.531 14.952 ;
     RECT  56.195 1.92 56.579 2.664 ;
     RECT  56.291 11.712 56.579 12.312 ;
     RECT  56.579 2.352 56.585 2.664 ;
     RECT  56.579 11.712 56.627 12.072 ;
     RECT  56.195 3.648 56.657 6.072 ;
     RECT  56.531 13.824 56.675 13.848 ;
     RECT  56.585 2.352 56.693 2.376 ;
     RECT  56.657 3.648 56.729 3.72 ;
     RECT  56.657 4.992 57.053 6.072 ;
     RECT  56.729 3.696 57.059 3.72 ;
     RECT  56.531 14.928 57.059 14.952 ;
     RECT  57.053 5.424 57.089 6.072 ;
     RECT  56.627 11.712 57.089 11.736 ;
    LAYER M5 ;
     RECT  22.176 0.133 22.2 0.144 ;
     RECT  25.632 0.133 25.728 0.144 ;
     RECT  25.752 0.133 25.92 0.144 ;
     RECT  25.944 0.133 26.112 0.144 ;
     RECT  26.136 0.133 26.304 0.144 ;
     RECT  26.328 0.133 26.496 0.144 ;
     RECT  26.52 0.133 26.616 0.144 ;
     RECT  40.224 0.133 40.248 0.144 ;
     RECT  47.424 0.133 47.448 0.144 ;
     RECT  48.72 0.133 48.744 0.144 ;
     RECT  51.984 0.133 52.08 0.144 ;
     RECT  52.104 0.133 52.272 0.144 ;
     RECT  52.296 0.133 52.464 0.144 ;
     RECT  52.488 0.133 52.656 0.144 ;
     RECT  52.68 0.133 52.776 0.144 ;
     RECT  55.056 0.133 55.152 0.144 ;
     RECT  55.176 0.133 55.344 0.144 ;
     RECT  55.368 0.133 55.536 0.144 ;
     RECT  55.56 0.133 55.728 0.144 ;
     RECT  55.752 0.133 55.92 0.144 ;
     RECT  55.944 0.133 56.04 0.144 ;
     RECT  2.328 0.144 2.496 0.181 ;
     RECT  2.52 0.144 2.688 0.181 ;
     RECT  2.712 0.144 2.88 0.181 ;
     RECT  2.904 0.144 3.072 0.181 ;
     RECT  3.096 0.144 3.264 0.181 ;
     RECT  3.288 0.144 3.456 0.181 ;
     RECT  3.48 0.144 3.648 0.181 ;
     RECT  3.672 0.144 3.84 0.181 ;
     RECT  3.864 0.144 4.032 0.181 ;
     RECT  4.056 0.144 4.224 0.181 ;
     RECT  4.248 0.144 4.416 0.181 ;
     RECT  4.44 0.144 4.608 0.181 ;
     RECT  4.632 0.144 4.8 0.181 ;
     RECT  4.824 0.144 4.992 0.181 ;
     RECT  5.016 0.144 5.184 0.181 ;
     RECT  5.208 0.144 5.376 0.181 ;
     RECT  5.4 0.144 5.568 0.181 ;
     RECT  5.592 0.144 5.76 0.181 ;
     RECT  5.784 0.144 5.952 0.181 ;
     RECT  5.976 0.144 6.144 0.181 ;
     RECT  6.168 0.144 6.336 0.181 ;
     RECT  6.36 0.144 6.528 0.181 ;
     RECT  6.552 0.144 6.72 0.181 ;
     RECT  6.744 0.144 6.912 0.181 ;
     RECT  6.936 0.144 7.104 0.181 ;
     RECT  7.128 0.144 7.296 0.181 ;
     RECT  7.32 0.144 7.488 0.181 ;
     RECT  7.512 0.144 7.68 0.181 ;
     RECT  7.704 0.144 7.872 0.181 ;
     RECT  7.896 0.144 8.064 0.181 ;
     RECT  8.088 0.144 8.256 0.181 ;
     RECT  8.28 0.144 8.448 0.181 ;
     RECT  8.472 0.144 8.64 0.181 ;
     RECT  8.664 0.144 8.832 0.181 ;
     RECT  8.856 0.144 9.024 0.181 ;
     RECT  9.048 0.144 9.216 0.181 ;
     RECT  9.24 0.144 9.408 0.181 ;
     RECT  9.432 0.144 9.6 0.181 ;
     RECT  9.624 0.144 9.792 0.181 ;
     RECT  9.816 0.144 9.984 0.181 ;
     RECT  10.008 0.144 10.176 0.181 ;
     RECT  10.2 0.144 10.368 0.181 ;
     RECT  10.392 0.144 10.56 0.181 ;
     RECT  10.584 0.144 10.752 0.181 ;
     RECT  10.776 0.144 10.944 0.181 ;
     RECT  10.968 0.144 11.136 0.181 ;
     RECT  11.16 0.144 11.328 0.181 ;
     RECT  11.352 0.144 11.52 0.181 ;
     RECT  11.544 0.144 11.712 0.181 ;
     RECT  11.736 0.144 11.904 0.181 ;
     RECT  11.928 0.144 12.096 0.181 ;
     RECT  12.12 0.144 12.288 0.181 ;
     RECT  12.312 0.144 12.48 0.181 ;
     RECT  12.504 0.144 12.672 0.181 ;
     RECT  12.696 0.144 12.864 0.181 ;
     RECT  12.888 0.144 13.056 0.181 ;
     RECT  13.08 0.144 13.248 0.181 ;
     RECT  13.272 0.144 13.44 0.181 ;
     RECT  13.464 0.144 13.632 0.181 ;
     RECT  13.656 0.144 13.824 0.181 ;
     RECT  13.848 0.144 14.016 0.181 ;
     RECT  14.04 0.144 14.208 0.181 ;
     RECT  14.232 0.144 14.4 0.181 ;
     RECT  14.424 0.144 14.592 0.181 ;
     RECT  14.616 0.144 14.784 0.181 ;
     RECT  14.808 0.144 14.976 0.181 ;
     RECT  15 0.144 15.168 0.181 ;
     RECT  15.192 0.144 15.36 0.181 ;
     RECT  15.384 0.144 15.552 0.181 ;
     RECT  15.576 0.144 15.744 0.181 ;
     RECT  15.768 0.144 15.936 0.181 ;
     RECT  15.96 0.144 16.128 0.181 ;
     RECT  16.152 0.144 16.32 0.181 ;
     RECT  16.344 0.144 16.512 0.181 ;
     RECT  16.536 0.144 16.704 0.181 ;
     RECT  16.728 0.144 16.896 0.181 ;
     RECT  16.92 0.144 17.088 0.181 ;
     RECT  17.112 0.144 17.28 0.181 ;
     RECT  17.304 0.144 17.472 0.181 ;
     RECT  17.496 0.144 17.664 0.181 ;
     RECT  17.688 0.144 17.856 0.181 ;
     RECT  17.88 0.144 18.048 0.181 ;
     RECT  18.072 0.144 18.24 0.181 ;
     RECT  18.264 0.144 18.432 0.181 ;
     RECT  18.456 0.144 18.624 0.181 ;
     RECT  18.648 0.144 18.816 0.181 ;
     RECT  18.84 0.144 19.008 0.181 ;
     RECT  19.032 0.144 19.2 0.181 ;
     RECT  19.224 0.144 19.392 0.181 ;
     RECT  19.416 0.144 19.584 0.181 ;
     RECT  19.608 0.144 19.776 0.181 ;
     RECT  19.8 0.144 19.968 0.181 ;
     RECT  19.992 0.144 20.16 0.181 ;
     RECT  20.184 0.144 20.352 0.181 ;
     RECT  20.376 0.144 20.544 0.181 ;
     RECT  20.568 0.144 20.736 0.181 ;
     RECT  20.76 0.144 20.928 0.181 ;
     RECT  20.952 0.144 21.12 0.181 ;
     RECT  21.144 0.144 21.312 0.181 ;
     RECT  21.336 0.144 21.504 0.181 ;
     RECT  21.528 0.144 21.696 0.181 ;
     RECT  21.72 0.144 21.888 0.181 ;
     RECT  21.912 0.144 22.08 0.181 ;
     RECT  22.104 0.144 22.272 0.181 ;
     RECT  22.296 0.144 22.464 0.181 ;
     RECT  22.488 0.144 22.656 0.181 ;
     RECT  22.68 0.144 22.848 0.181 ;
     RECT  22.872 0.144 23.04 0.181 ;
     RECT  23.064 0.144 23.232 0.181 ;
     RECT  23.256 0.144 23.424 0.181 ;
     RECT  23.448 0.144 23.616 0.181 ;
     RECT  23.64 0.144 23.808 0.181 ;
     RECT  23.832 0.144 24 0.181 ;
     RECT  24.024 0.144 24.192 0.181 ;
     RECT  24.216 0.144 24.384 0.181 ;
     RECT  24.408 0.144 24.576 0.181 ;
     RECT  24.6 0.144 24.768 0.181 ;
     RECT  24.792 0.144 24.96 0.181 ;
     RECT  24.984 0.144 25.152 0.181 ;
     RECT  25.176 0.144 25.344 0.181 ;
     RECT  25.368 0.144 25.536 0.181 ;
     RECT  25.56 0.144 25.728 0.181 ;
     RECT  25.752 0.144 25.92 0.181 ;
     RECT  25.944 0.144 26.112 0.181 ;
     RECT  26.136 0.144 26.304 0.181 ;
     RECT  26.328 0.144 26.496 0.181 ;
     RECT  26.52 0.144 26.688 0.181 ;
     RECT  26.712 0.144 26.88 0.181 ;
     RECT  26.904 0.144 27.072 0.181 ;
     RECT  27.096 0.144 27.264 0.181 ;
     RECT  27.288 0.144 27.456 0.181 ;
     RECT  27.48 0.144 27.648 0.181 ;
     RECT  27.672 0.144 27.84 0.181 ;
     RECT  27.864 0.144 28.032 0.181 ;
     RECT  28.056 0.144 28.224 0.181 ;
     RECT  28.248 0.144 28.416 0.181 ;
     RECT  28.44 0.144 28.608 0.181 ;
     RECT  28.632 0.144 28.8 0.181 ;
     RECT  28.824 0.144 28.992 0.181 ;
     RECT  29.016 0.144 29.184 0.181 ;
     RECT  29.208 0.144 29.376 0.181 ;
     RECT  29.4 0.144 29.568 0.181 ;
     RECT  29.592 0.144 29.76 0.181 ;
     RECT  29.784 0.144 29.952 0.181 ;
     RECT  29.976 0.144 30.144 0.181 ;
     RECT  30.168 0.144 30.336 0.181 ;
     RECT  30.36 0.144 30.528 0.181 ;
     RECT  30.552 0.144 30.72 0.181 ;
     RECT  30.744 0.144 30.912 0.181 ;
     RECT  30.936 0.144 31.104 0.181 ;
     RECT  31.128 0.144 31.296 0.181 ;
     RECT  31.32 0.144 31.488 0.181 ;
     RECT  31.512 0.144 31.68 0.181 ;
     RECT  31.704 0.144 31.872 0.181 ;
     RECT  31.896 0.144 32.064 0.181 ;
     RECT  32.088 0.144 32.256 0.181 ;
     RECT  32.28 0.144 32.448 0.181 ;
     RECT  32.472 0.144 32.64 0.181 ;
     RECT  32.664 0.144 32.832 0.181 ;
     RECT  32.856 0.144 33.024 0.181 ;
     RECT  33.048 0.144 33.216 0.181 ;
     RECT  33.24 0.144 33.408 0.181 ;
     RECT  33.432 0.144 33.6 0.181 ;
     RECT  33.624 0.144 33.792 0.181 ;
     RECT  33.816 0.144 33.984 0.181 ;
     RECT  34.008 0.144 34.176 0.181 ;
     RECT  34.2 0.144 34.368 0.181 ;
     RECT  34.392 0.144 34.56 0.181 ;
     RECT  34.584 0.144 34.752 0.181 ;
     RECT  34.776 0.144 34.944 0.181 ;
     RECT  34.968 0.144 35.136 0.181 ;
     RECT  35.16 0.144 35.328 0.181 ;
     RECT  35.352 0.144 35.52 0.181 ;
     RECT  35.544 0.144 35.712 0.181 ;
     RECT  35.736 0.144 35.904 0.181 ;
     RECT  35.928 0.144 36.096 0.181 ;
     RECT  36.12 0.144 36.288 0.181 ;
     RECT  36.312 0.144 36.48 0.181 ;
     RECT  36.504 0.144 36.672 0.181 ;
     RECT  36.696 0.144 36.864 0.181 ;
     RECT  36.888 0.144 37.056 0.181 ;
     RECT  37.08 0.144 37.248 0.181 ;
     RECT  37.272 0.144 37.44 0.181 ;
     RECT  37.464 0.144 37.632 0.181 ;
     RECT  37.656 0.144 37.824 0.181 ;
     RECT  37.848 0.144 38.016 0.181 ;
     RECT  38.04 0.144 38.208 0.181 ;
     RECT  38.232 0.144 38.4 0.181 ;
     RECT  38.424 0.144 38.592 0.181 ;
     RECT  38.616 0.144 38.784 0.181 ;
     RECT  38.808 0.144 38.976 0.181 ;
     RECT  39 0.144 39.168 0.181 ;
     RECT  39.192 0.144 39.36 0.181 ;
     RECT  39.384 0.144 39.552 0.181 ;
     RECT  39.576 0.144 39.744 0.181 ;
     RECT  39.768 0.144 39.936 0.181 ;
     RECT  39.96 0.144 40.128 0.181 ;
     RECT  40.152 0.144 40.32 0.181 ;
     RECT  40.344 0.144 40.512 0.181 ;
     RECT  40.536 0.144 40.704 0.181 ;
     RECT  40.728 0.144 40.896 0.181 ;
     RECT  40.92 0.144 41.088 0.181 ;
     RECT  41.112 0.144 41.28 0.181 ;
     RECT  41.304 0.144 41.472 0.181 ;
     RECT  41.496 0.144 41.664 0.181 ;
     RECT  41.688 0.144 41.856 0.181 ;
     RECT  41.88 0.144 42.048 0.181 ;
     RECT  42.072 0.144 42.24 0.181 ;
     RECT  42.264 0.144 42.432 0.181 ;
     RECT  42.456 0.144 42.624 0.181 ;
     RECT  42.648 0.144 42.864 0.181 ;
     RECT  42.888 0.144 43.056 0.181 ;
     RECT  43.08 0.144 43.248 0.181 ;
     RECT  43.272 0.144 43.44 0.181 ;
     RECT  43.464 0.144 43.632 0.181 ;
     RECT  43.656 0.144 43.824 0.181 ;
     RECT  43.848 0.144 44.016 0.181 ;
     RECT  44.04 0.144 44.208 0.181 ;
     RECT  44.232 0.144 44.4 0.181 ;
     RECT  44.424 0.144 44.592 0.181 ;
     RECT  44.616 0.144 44.784 0.181 ;
     RECT  44.808 0.144 44.976 0.181 ;
     RECT  45 0.144 45.168 0.181 ;
     RECT  45.192 0.144 45.36 0.181 ;
     RECT  45.384 0.144 45.552 0.181 ;
     RECT  45.576 0.144 45.744 0.181 ;
     RECT  45.768 0.144 45.936 0.181 ;
     RECT  45.96 0.144 46.128 0.181 ;
     RECT  46.152 0.144 46.32 0.181 ;
     RECT  46.344 0.144 46.512 0.181 ;
     RECT  46.536 0.144 46.704 0.181 ;
     RECT  46.728 0.144 46.896 0.181 ;
     RECT  46.92 0.144 47.088 0.181 ;
     RECT  47.112 0.144 47.28 0.181 ;
     RECT  47.304 0.144 47.472 0.181 ;
     RECT  47.496 0.144 47.664 0.181 ;
     RECT  47.688 0.144 47.856 0.181 ;
     RECT  47.88 0.144 48.048 0.181 ;
     RECT  48.072 0.144 48.24 0.181 ;
     RECT  48.264 0.144 48.432 0.181 ;
     RECT  48.456 0.144 48.624 0.181 ;
     RECT  48.648 0.144 48.816 0.181 ;
     RECT  48.84 0.144 49.008 0.181 ;
     RECT  49.032 0.144 49.2 0.181 ;
     RECT  49.224 0.144 49.392 0.181 ;
     RECT  49.416 0.144 49.584 0.181 ;
     RECT  49.608 0.144 49.776 0.181 ;
     RECT  49.8 0.144 49.968 0.181 ;
     RECT  49.992 0.144 50.16 0.181 ;
     RECT  50.184 0.144 50.352 0.181 ;
     RECT  50.376 0.144 50.544 0.181 ;
     RECT  50.568 0.144 50.736 0.181 ;
     RECT  50.76 0.144 50.928 0.181 ;
     RECT  50.952 0.144 51.12 0.181 ;
     RECT  51.144 0.144 51.312 0.181 ;
     RECT  51.336 0.144 51.504 0.181 ;
     RECT  51.528 0.144 51.696 0.181 ;
     RECT  51.72 0.144 51.888 0.181 ;
     RECT  51.912 0.144 52.08 0.181 ;
     RECT  52.104 0.144 52.272 0.181 ;
     RECT  52.296 0.144 52.464 0.181 ;
     RECT  52.488 0.144 52.656 0.181 ;
     RECT  52.68 0.144 52.848 0.181 ;
     RECT  52.872 0.144 53.04 0.181 ;
     RECT  53.064 0.144 53.232 0.181 ;
     RECT  53.256 0.144 53.424 0.181 ;
     RECT  53.448 0.144 53.616 0.181 ;
     RECT  53.64 0.144 53.808 0.181 ;
     RECT  53.832 0.144 54 0.181 ;
     RECT  54.024 0.144 54.192 0.181 ;
     RECT  54.216 0.144 54.384 0.181 ;
     RECT  54.408 0.144 54.576 0.181 ;
     RECT  54.6 0.144 54.768 0.181 ;
     RECT  54.792 0.144 54.96 0.181 ;
     RECT  54.984 0.144 55.152 0.181 ;
     RECT  55.176 0.144 55.344 0.181 ;
     RECT  55.368 0.144 55.536 0.181 ;
     RECT  55.56 0.144 55.728 0.181 ;
     RECT  55.752 0.144 55.92 0.181 ;
     RECT  55.944 0.144 56.112 0.181 ;
     RECT  2.328 0.181 2.496 0.192 ;
     RECT  2.52 0.181 2.688 0.192 ;
     RECT  2.712 0.181 2.88 0.192 ;
     RECT  2.904 0.181 3.072 0.192 ;
     RECT  3.096 0.181 3.264 0.192 ;
     RECT  3.288 0.181 3.456 0.192 ;
     RECT  3.48 0.181 3.648 0.192 ;
     RECT  3.672 0.181 3.84 0.192 ;
     RECT  3.864 0.181 4.032 0.192 ;
     RECT  4.056 0.181 4.224 0.192 ;
     RECT  4.248 0.181 4.416 0.192 ;
     RECT  4.44 0.181 4.608 0.192 ;
     RECT  4.632 0.181 4.8 0.192 ;
     RECT  4.824 0.181 4.992 0.192 ;
     RECT  5.016 0.181 5.184 0.192 ;
     RECT  5.208 0.181 5.376 0.192 ;
     RECT  5.4 0.181 5.568 0.192 ;
     RECT  5.592 0.181 5.76 0.192 ;
     RECT  5.784 0.181 5.952 0.192 ;
     RECT  5.976 0.181 6.144 0.192 ;
     RECT  6.168 0.181 6.336 0.192 ;
     RECT  6.36 0.181 6.528 0.192 ;
     RECT  6.552 0.181 6.72 0.192 ;
     RECT  6.744 0.181 6.912 0.192 ;
     RECT  6.936 0.181 7.104 0.192 ;
     RECT  7.128 0.181 7.296 0.192 ;
     RECT  7.32 0.181 7.488 0.192 ;
     RECT  7.512 0.181 7.68 0.192 ;
     RECT  7.704 0.181 7.872 0.192 ;
     RECT  7.896 0.181 8.064 0.192 ;
     RECT  8.088 0.181 8.256 0.192 ;
     RECT  8.28 0.181 8.448 0.192 ;
     RECT  8.472 0.181 8.64 0.192 ;
     RECT  8.664 0.181 8.832 0.192 ;
     RECT  8.856 0.181 9.024 0.192 ;
     RECT  9.048 0.181 9.216 0.192 ;
     RECT  9.24 0.181 9.408 0.192 ;
     RECT  9.432 0.181 9.6 0.192 ;
     RECT  9.624 0.181 9.792 0.192 ;
     RECT  9.816 0.181 9.984 0.192 ;
     RECT  10.008 0.181 10.176 0.192 ;
     RECT  10.2 0.181 10.368 0.192 ;
     RECT  10.392 0.181 10.56 0.192 ;
     RECT  10.584 0.181 10.752 0.192 ;
     RECT  10.776 0.181 10.944 0.192 ;
     RECT  10.968 0.181 11.136 0.192 ;
     RECT  11.16 0.181 11.328 0.192 ;
     RECT  11.352 0.181 11.52 0.192 ;
     RECT  11.544 0.181 11.712 0.192 ;
     RECT  11.736 0.181 11.904 0.192 ;
     RECT  11.928 0.181 12.096 0.192 ;
     RECT  12.12 0.181 12.288 0.192 ;
     RECT  12.312 0.181 12.48 0.192 ;
     RECT  12.504 0.181 12.672 0.192 ;
     RECT  12.696 0.181 12.864 0.192 ;
     RECT  12.888 0.181 13.056 0.192 ;
     RECT  13.08 0.181 13.248 0.192 ;
     RECT  13.272 0.181 13.44 0.192 ;
     RECT  13.464 0.181 13.632 0.192 ;
     RECT  13.656 0.181 13.824 0.192 ;
     RECT  13.848 0.181 14.016 0.192 ;
     RECT  14.04 0.181 14.208 0.192 ;
     RECT  14.232 0.181 14.4 0.192 ;
     RECT  14.424 0.181 14.592 0.192 ;
     RECT  14.616 0.181 14.784 0.192 ;
     RECT  14.808 0.181 14.976 0.192 ;
     RECT  15 0.181 15.168 0.192 ;
     RECT  15.192 0.181 15.36 0.192 ;
     RECT  15.384 0.181 15.552 0.192 ;
     RECT  15.576 0.181 15.744 0.192 ;
     RECT  15.768 0.181 15.936 0.192 ;
     RECT  15.96 0.181 16.128 0.192 ;
     RECT  16.152 0.181 16.32 0.192 ;
     RECT  16.344 0.181 16.512 0.192 ;
     RECT  16.536 0.181 16.704 0.192 ;
     RECT  16.728 0.181 16.896 0.192 ;
     RECT  16.92 0.181 17.088 0.192 ;
     RECT  17.112 0.181 17.28 0.192 ;
     RECT  17.304 0.181 17.472 0.192 ;
     RECT  17.496 0.181 17.664 0.192 ;
     RECT  17.688 0.181 17.856 0.192 ;
     RECT  17.88 0.181 18.048 0.192 ;
     RECT  18.072 0.181 18.24 0.192 ;
     RECT  18.264 0.181 18.432 0.192 ;
     RECT  18.456 0.181 18.624 0.192 ;
     RECT  18.648 0.181 18.816 0.192 ;
     RECT  18.84 0.181 19.008 0.192 ;
     RECT  19.032 0.181 19.2 0.192 ;
     RECT  19.224 0.181 19.392 0.192 ;
     RECT  19.416 0.181 19.584 0.192 ;
     RECT  19.608 0.181 19.776 0.192 ;
     RECT  19.8 0.181 19.968 0.192 ;
     RECT  19.992 0.181 20.16 0.192 ;
     RECT  20.184 0.181 20.352 0.192 ;
     RECT  20.376 0.181 20.544 0.192 ;
     RECT  20.568 0.181 20.736 0.192 ;
     RECT  20.76 0.181 20.928 0.192 ;
     RECT  20.952 0.181 21.12 0.192 ;
     RECT  21.144 0.181 21.312 0.192 ;
     RECT  21.336 0.181 21.504 0.192 ;
     RECT  21.528 0.181 21.696 0.192 ;
     RECT  21.72 0.181 21.888 0.192 ;
     RECT  21.912 0.181 22.08 0.192 ;
     RECT  22.104 0.181 22.272 0.192 ;
     RECT  22.296 0.181 22.464 0.192 ;
     RECT  22.488 0.181 22.656 0.192 ;
     RECT  22.68 0.181 22.848 0.192 ;
     RECT  22.872 0.181 23.04 0.192 ;
     RECT  23.064 0.181 23.232 0.192 ;
     RECT  23.256 0.181 23.424 0.192 ;
     RECT  23.448 0.181 23.616 0.192 ;
     RECT  23.64 0.181 23.808 0.192 ;
     RECT  23.832 0.181 24 0.192 ;
     RECT  24.024 0.181 24.192 0.192 ;
     RECT  24.216 0.181 24.384 0.192 ;
     RECT  24.408 0.181 24.576 0.192 ;
     RECT  24.6 0.181 24.768 0.192 ;
     RECT  24.792 0.181 24.96 0.192 ;
     RECT  24.984 0.181 25.152 0.192 ;
     RECT  25.176 0.181 25.344 0.192 ;
     RECT  25.368 0.181 25.536 0.192 ;
     RECT  25.56 0.181 25.728 0.192 ;
     RECT  25.752 0.181 25.92 0.192 ;
     RECT  25.944 0.181 26.112 0.192 ;
     RECT  26.136 0.181 26.304 0.192 ;
     RECT  26.328 0.181 26.496 0.192 ;
     RECT  26.52 0.181 26.688 0.192 ;
     RECT  26.712 0.181 26.88 0.192 ;
     RECT  26.904 0.181 27.072 0.192 ;
     RECT  27.096 0.181 27.264 0.192 ;
     RECT  27.288 0.181 27.456 0.192 ;
     RECT  27.48 0.181 27.648 0.192 ;
     RECT  27.672 0.181 27.84 0.192 ;
     RECT  27.864 0.181 28.032 0.192 ;
     RECT  28.056 0.181 28.224 0.192 ;
     RECT  28.248 0.181 28.416 0.192 ;
     RECT  28.44 0.181 28.608 0.192 ;
     RECT  28.632 0.181 28.8 0.192 ;
     RECT  28.824 0.181 28.992 0.192 ;
     RECT  29.016 0.181 29.184 0.192 ;
     RECT  29.208 0.181 29.376 0.192 ;
     RECT  29.4 0.181 29.568 0.192 ;
     RECT  29.592 0.181 29.76 0.192 ;
     RECT  29.784 0.181 29.952 0.192 ;
     RECT  29.976 0.181 30.144 0.192 ;
     RECT  30.168 0.181 30.336 0.192 ;
     RECT  30.36 0.181 30.528 0.192 ;
     RECT  30.552 0.181 30.72 0.192 ;
     RECT  30.744 0.181 30.912 0.192 ;
     RECT  30.936 0.181 31.104 0.192 ;
     RECT  31.128 0.181 31.296 0.192 ;
     RECT  31.32 0.181 31.488 0.192 ;
     RECT  31.512 0.181 31.68 0.192 ;
     RECT  31.704 0.181 31.872 0.192 ;
     RECT  31.896 0.181 32.064 0.192 ;
     RECT  32.088 0.181 32.256 0.192 ;
     RECT  32.28 0.181 32.448 0.192 ;
     RECT  32.472 0.181 32.64 0.192 ;
     RECT  32.664 0.181 32.832 0.192 ;
     RECT  32.856 0.181 33.024 0.192 ;
     RECT  33.048 0.181 33.216 0.192 ;
     RECT  33.24 0.181 33.408 0.192 ;
     RECT  33.432 0.181 33.6 0.192 ;
     RECT  33.624 0.181 33.792 0.192 ;
     RECT  33.816 0.181 33.984 0.192 ;
     RECT  34.008 0.181 34.176 0.192 ;
     RECT  34.2 0.181 34.368 0.192 ;
     RECT  34.392 0.181 34.56 0.192 ;
     RECT  34.584 0.181 34.752 0.192 ;
     RECT  34.776 0.181 34.944 0.192 ;
     RECT  34.968 0.181 35.136 0.192 ;
     RECT  35.16 0.181 35.328 0.192 ;
     RECT  35.352 0.181 35.52 0.192 ;
     RECT  35.544 0.181 35.712 0.192 ;
     RECT  35.736 0.181 35.904 0.192 ;
     RECT  35.928 0.181 36.096 0.192 ;
     RECT  36.12 0.181 36.288 0.192 ;
     RECT  36.312 0.181 36.48 0.192 ;
     RECT  36.504 0.181 36.672 0.192 ;
     RECT  36.696 0.181 36.864 0.192 ;
     RECT  36.888 0.181 37.056 0.192 ;
     RECT  37.08 0.181 37.248 0.192 ;
     RECT  37.272 0.181 37.44 0.192 ;
     RECT  37.464 0.181 37.632 0.192 ;
     RECT  37.656 0.181 37.824 0.192 ;
     RECT  37.848 0.181 38.016 0.192 ;
     RECT  38.04 0.181 38.208 0.192 ;
     RECT  38.232 0.181 38.4 0.192 ;
     RECT  38.424 0.181 38.592 0.192 ;
     RECT  38.616 0.181 38.784 0.192 ;
     RECT  38.808 0.181 38.976 0.192 ;
     RECT  39 0.181 39.168 0.192 ;
     RECT  39.192 0.181 39.36 0.192 ;
     RECT  39.384 0.181 39.552 0.192 ;
     RECT  39.576 0.181 39.744 0.192 ;
     RECT  39.768 0.181 39.936 0.192 ;
     RECT  39.96 0.181 40.128 0.192 ;
     RECT  40.152 0.181 40.32 0.192 ;
     RECT  40.344 0.181 40.512 0.192 ;
     RECT  40.536 0.181 40.704 0.192 ;
     RECT  40.728 0.181 40.896 0.192 ;
     RECT  40.92 0.181 41.088 0.192 ;
     RECT  41.112 0.181 41.28 0.192 ;
     RECT  41.304 0.181 41.472 0.192 ;
     RECT  41.496 0.181 41.664 0.192 ;
     RECT  41.688 0.181 41.856 0.192 ;
     RECT  41.88 0.181 42.048 0.192 ;
     RECT  42.072 0.181 42.24 0.192 ;
     RECT  42.264 0.181 42.432 0.192 ;
     RECT  42.456 0.181 42.624 0.192 ;
     RECT  42.648 0.181 42.864 0.192 ;
     RECT  42.888 0.181 43.056 0.192 ;
     RECT  43.08 0.181 43.248 0.192 ;
     RECT  43.272 0.181 43.44 0.192 ;
     RECT  43.464 0.181 43.632 0.192 ;
     RECT  43.656 0.181 43.824 0.192 ;
     RECT  43.848 0.181 44.016 0.192 ;
     RECT  44.04 0.181 44.208 0.192 ;
     RECT  44.232 0.181 44.4 0.192 ;
     RECT  44.424 0.181 44.592 0.192 ;
     RECT  44.616 0.181 44.784 0.192 ;
     RECT  44.808 0.181 44.976 0.192 ;
     RECT  45 0.181 45.168 0.192 ;
     RECT  45.192 0.181 45.36 0.192 ;
     RECT  45.384 0.181 45.552 0.192 ;
     RECT  45.576 0.181 45.744 0.192 ;
     RECT  45.768 0.181 45.936 0.192 ;
     RECT  45.96 0.181 46.128 0.192 ;
     RECT  46.152 0.181 46.32 0.192 ;
     RECT  46.344 0.181 46.512 0.192 ;
     RECT  46.536 0.181 46.704 0.192 ;
     RECT  46.728 0.181 46.896 0.192 ;
     RECT  46.92 0.181 47.088 0.192 ;
     RECT  47.112 0.181 47.28 0.192 ;
     RECT  47.304 0.181 47.472 0.192 ;
     RECT  47.496 0.181 47.664 0.192 ;
     RECT  47.688 0.181 47.856 0.192 ;
     RECT  47.88 0.181 48.048 0.192 ;
     RECT  48.072 0.181 48.24 0.192 ;
     RECT  48.264 0.181 48.432 0.192 ;
     RECT  48.456 0.181 48.624 0.192 ;
     RECT  48.648 0.181 48.816 0.192 ;
     RECT  48.84 0.181 49.008 0.192 ;
     RECT  49.032 0.181 49.2 0.192 ;
     RECT  49.224 0.181 49.392 0.192 ;
     RECT  49.416 0.181 49.584 0.192 ;
     RECT  49.608 0.181 49.776 0.192 ;
     RECT  49.8 0.181 49.968 0.192 ;
     RECT  49.992 0.181 50.16 0.192 ;
     RECT  50.184 0.181 50.352 0.192 ;
     RECT  50.376 0.181 50.544 0.192 ;
     RECT  50.568 0.181 50.736 0.192 ;
     RECT  50.76 0.181 50.928 0.192 ;
     RECT  50.952 0.181 51.12 0.192 ;
     RECT  51.144 0.181 51.312 0.192 ;
     RECT  51.336 0.181 51.504 0.192 ;
     RECT  51.528 0.181 51.696 0.192 ;
     RECT  51.72 0.181 51.888 0.192 ;
     RECT  51.912 0.181 52.08 0.192 ;
     RECT  52.104 0.181 52.272 0.192 ;
     RECT  52.296 0.181 52.464 0.192 ;
     RECT  52.488 0.181 52.656 0.192 ;
     RECT  52.68 0.181 52.848 0.192 ;
     RECT  52.872 0.181 53.04 0.192 ;
     RECT  53.064 0.181 53.232 0.192 ;
     RECT  53.256 0.181 53.424 0.192 ;
     RECT  53.448 0.181 53.616 0.192 ;
     RECT  53.64 0.181 53.808 0.192 ;
     RECT  53.832 0.181 54 0.192 ;
     RECT  54.024 0.181 54.192 0.192 ;
     RECT  54.216 0.181 54.384 0.192 ;
     RECT  54.408 0.181 54.576 0.192 ;
     RECT  54.6 0.181 54.768 0.192 ;
     RECT  54.792 0.181 54.96 0.192 ;
     RECT  54.984 0.181 55.152 0.192 ;
     RECT  55.176 0.181 55.344 0.192 ;
     RECT  55.368 0.181 55.536 0.192 ;
     RECT  55.56 0.181 55.728 0.192 ;
     RECT  55.752 0.181 55.92 0.192 ;
     RECT  55.944 0.181 56.112 0.192 ;
     RECT  56.136 0.181 56.28 0.192 ;
     RECT  2.304 0.192 56.28 1.909 ;
     RECT  2.304 1.909 56.568 3.685 ;
     RECT  2.304 3.685 57.048 5.171 ;
     RECT  2.4 5.171 57.048 9.683 ;
     RECT  42.9 9.683 57.048 10.883 ;
     RECT  42.9 10.883 43.416 11.221 ;
     RECT  2.4 9.683 41.784 11.413 ;
     RECT  42.768 11.221 43.416 11.413 ;
     RECT  2.4 11.413 43.416 11.893 ;
     RECT  44.592 10.883 57.048 11.893 ;
     RECT  2.4 11.893 57.048 12.035 ;
     RECT  2.4 12.035 54.744 12.131 ;
     RECT  56.208 12.035 57.048 13.045 ;
     RECT  2.4 12.131 54.456 13.093 ;
     RECT  56.016 13.045 57.048 13.093 ;
     RECT  2.4 13.093 57.048 13.667 ;
     RECT  55.056 13.667 57.048 14.387 ;
     RECT  2.4 13.667 54.012 14.821 ;
     RECT  55.056 14.387 56.04 14.821 ;
     RECT  57.024 14.387 57.048 14.963 ;
     RECT  2.4 14.821 56.04 15.143 ;
     RECT  2.688 15.143 56.04 16.549 ;
     RECT  2.304 16.549 56.04 17.088 ;
     RECT  2.328 17.088 2.496 17.104 ;
     RECT  2.52 17.088 2.688 17.104 ;
     RECT  2.712 17.088 2.88 17.104 ;
     RECT  2.904 17.088 3.072 17.104 ;
     RECT  3.096 17.088 3.264 17.104 ;
     RECT  3.288 17.088 3.456 17.104 ;
     RECT  3.48 17.088 3.648 17.104 ;
     RECT  3.672 17.088 3.84 17.104 ;
     RECT  3.864 17.088 4.032 17.104 ;
     RECT  4.056 17.088 4.224 17.104 ;
     RECT  4.248 17.088 4.416 17.104 ;
     RECT  4.44 17.088 4.608 17.104 ;
     RECT  4.632 17.088 4.8 17.104 ;
     RECT  4.824 17.088 4.992 17.104 ;
     RECT  5.016 17.088 5.184 17.104 ;
     RECT  5.208 17.088 5.376 17.104 ;
     RECT  5.4 17.088 5.568 17.104 ;
     RECT  5.592 17.088 5.76 17.104 ;
     RECT  5.784 17.088 5.952 17.104 ;
     RECT  5.976 17.088 6.144 17.104 ;
     RECT  6.168 17.088 6.336 17.104 ;
     RECT  6.36 17.088 6.528 17.104 ;
     RECT  6.552 17.088 6.72 17.104 ;
     RECT  6.744 17.088 6.912 17.104 ;
     RECT  6.936 17.088 7.104 17.104 ;
     RECT  7.128 17.088 7.296 17.104 ;
     RECT  7.32 17.088 7.488 17.104 ;
     RECT  7.512 17.088 7.68 17.104 ;
     RECT  7.704 17.088 7.872 17.104 ;
     RECT  7.896 17.088 8.064 17.104 ;
     RECT  8.088 17.088 8.256 17.104 ;
     RECT  8.28 17.088 8.448 17.104 ;
     RECT  8.472 17.088 8.64 17.104 ;
     RECT  8.664 17.088 8.832 17.104 ;
     RECT  8.856 17.088 9.024 17.104 ;
     RECT  9.048 17.088 9.216 17.104 ;
     RECT  9.24 17.088 9.408 17.104 ;
     RECT  9.432 17.088 9.6 17.104 ;
     RECT  9.624 17.088 9.792 17.104 ;
     RECT  9.816 17.088 9.984 17.104 ;
     RECT  10.008 17.088 10.176 17.104 ;
     RECT  10.2 17.088 10.368 17.104 ;
     RECT  10.392 17.088 10.56 17.104 ;
     RECT  10.584 17.088 10.752 17.104 ;
     RECT  10.776 17.088 10.944 17.104 ;
     RECT  10.968 17.088 11.136 17.104 ;
     RECT  11.16 17.088 11.328 17.104 ;
     RECT  11.352 17.088 11.52 17.104 ;
     RECT  11.544 17.088 11.712 17.104 ;
     RECT  11.736 17.088 11.904 17.104 ;
     RECT  11.928 17.088 12.096 17.104 ;
     RECT  12.12 17.088 12.288 17.104 ;
     RECT  12.312 17.088 12.48 17.104 ;
     RECT  12.504 17.088 12.672 17.104 ;
     RECT  12.696 17.088 12.864 17.104 ;
     RECT  12.888 17.088 13.056 17.104 ;
     RECT  13.08 17.088 13.248 17.104 ;
     RECT  13.272 17.088 13.44 17.104 ;
     RECT  13.464 17.088 13.632 17.104 ;
     RECT  13.656 17.088 13.824 17.104 ;
     RECT  13.848 17.088 14.016 17.104 ;
     RECT  14.04 17.088 14.208 17.104 ;
     RECT  14.232 17.088 14.4 17.104 ;
     RECT  14.424 17.088 14.592 17.104 ;
     RECT  14.616 17.088 14.784 17.104 ;
     RECT  14.808 17.088 14.976 17.104 ;
     RECT  15 17.088 15.168 17.104 ;
     RECT  15.192 17.088 15.36 17.104 ;
     RECT  15.384 17.088 15.552 17.104 ;
     RECT  15.576 17.088 15.696 17.104 ;
     RECT  15.72 17.088 15.888 17.104 ;
     RECT  15.912 17.088 16.08 17.104 ;
     RECT  16.104 17.088 16.272 17.104 ;
     RECT  16.296 17.088 16.464 17.104 ;
     RECT  16.488 17.088 16.656 17.104 ;
     RECT  16.68 17.088 16.848 17.104 ;
     RECT  16.872 17.088 17.04 17.104 ;
     RECT  17.064 17.088 17.232 17.104 ;
     RECT  17.256 17.088 17.424 17.104 ;
     RECT  17.448 17.088 17.616 17.104 ;
     RECT  17.64 17.088 17.808 17.104 ;
     RECT  17.832 17.088 18 17.104 ;
     RECT  18.024 17.088 18.192 17.104 ;
     RECT  18.216 17.088 18.384 17.104 ;
     RECT  18.408 17.088 18.576 17.104 ;
     RECT  18.6 17.088 18.768 17.104 ;
     RECT  18.792 17.088 18.96 17.104 ;
     RECT  18.984 17.088 19.152 17.104 ;
     RECT  19.176 17.088 19.344 17.104 ;
     RECT  19.368 17.088 19.536 17.104 ;
     RECT  19.56 17.088 19.728 17.104 ;
     RECT  19.752 17.088 19.92 17.104 ;
     RECT  19.944 17.088 20.112 17.104 ;
     RECT  20.136 17.088 20.304 17.104 ;
     RECT  20.328 17.088 20.496 17.104 ;
     RECT  20.52 17.088 20.688 17.104 ;
     RECT  20.712 17.088 20.88 17.104 ;
     RECT  20.904 17.088 21.072 17.104 ;
     RECT  21.096 17.088 21.264 17.104 ;
     RECT  21.288 17.088 21.456 17.104 ;
     RECT  21.48 17.088 21.648 17.104 ;
     RECT  21.672 17.088 21.84 17.104 ;
     RECT  21.864 17.088 22.032 17.104 ;
     RECT  22.056 17.088 22.224 17.104 ;
     RECT  22.248 17.088 22.416 17.104 ;
     RECT  22.44 17.088 22.608 17.104 ;
     RECT  22.632 17.088 22.8 17.104 ;
     RECT  22.824 17.088 22.992 17.104 ;
     RECT  23.016 17.088 23.184 17.104 ;
     RECT  23.208 17.088 23.376 17.104 ;
     RECT  23.4 17.088 23.568 17.104 ;
     RECT  23.592 17.088 23.76 17.104 ;
     RECT  23.784 17.088 23.952 17.104 ;
     RECT  23.976 17.088 24.144 17.104 ;
     RECT  24.168 17.088 24.336 17.104 ;
     RECT  24.36 17.088 24.528 17.104 ;
     RECT  24.552 17.088 24.72 17.104 ;
     RECT  24.744 17.088 24.912 17.104 ;
     RECT  24.936 17.088 25.104 17.104 ;
     RECT  25.128 17.088 25.296 17.104 ;
     RECT  25.32 17.088 25.488 17.104 ;
     RECT  25.512 17.088 25.68 17.104 ;
     RECT  25.704 17.088 25.872 17.104 ;
     RECT  25.896 17.088 26.064 17.104 ;
     RECT  26.088 17.088 26.256 17.104 ;
     RECT  26.28 17.088 26.448 17.104 ;
     RECT  26.472 17.088 26.64 17.104 ;
     RECT  26.664 17.088 26.832 17.104 ;
     RECT  26.856 17.088 27.024 17.104 ;
     RECT  27.048 17.088 27.216 17.104 ;
     RECT  27.24 17.088 27.408 17.104 ;
     RECT  27.432 17.088 27.6 17.104 ;
     RECT  27.624 17.088 27.792 17.104 ;
     RECT  27.816 17.088 27.984 17.104 ;
     RECT  28.008 17.088 28.176 17.104 ;
     RECT  28.2 17.088 28.368 17.104 ;
     RECT  28.392 17.088 28.56 17.104 ;
     RECT  28.584 17.088 28.752 17.104 ;
     RECT  28.776 17.088 28.944 17.104 ;
     RECT  28.968 17.088 29.136 17.104 ;
     RECT  29.16 17.088 29.328 17.104 ;
     RECT  29.352 17.088 29.52 17.104 ;
     RECT  29.544 17.088 29.712 17.104 ;
     RECT  29.736 17.088 29.904 17.104 ;
     RECT  29.928 17.088 30.096 17.104 ;
     RECT  30.12 17.088 30.288 17.104 ;
     RECT  30.312 17.088 30.48 17.104 ;
     RECT  30.504 17.088 30.672 17.104 ;
     RECT  30.696 17.088 30.864 17.104 ;
     RECT  30.888 17.088 31.056 17.104 ;
     RECT  31.08 17.088 31.248 17.104 ;
     RECT  31.272 17.088 31.44 17.104 ;
     RECT  31.464 17.088 31.632 17.104 ;
     RECT  31.656 17.088 31.824 17.104 ;
     RECT  31.848 17.088 32.016 17.104 ;
     RECT  32.04 17.088 32.208 17.104 ;
     RECT  32.232 17.088 32.4 17.104 ;
     RECT  32.424 17.088 32.592 17.104 ;
     RECT  32.616 17.088 32.784 17.104 ;
     RECT  32.808 17.088 32.976 17.104 ;
     RECT  33 17.088 33.168 17.104 ;
     RECT  33.192 17.088 33.36 17.104 ;
     RECT  33.384 17.088 33.552 17.104 ;
     RECT  33.576 17.088 33.744 17.104 ;
     RECT  33.768 17.088 33.936 17.104 ;
     RECT  33.96 17.088 34.128 17.104 ;
     RECT  34.152 17.088 34.32 17.104 ;
     RECT  34.344 17.088 34.512 17.104 ;
     RECT  34.536 17.088 34.704 17.104 ;
     RECT  34.728 17.088 34.896 17.104 ;
     RECT  34.92 17.088 35.088 17.104 ;
     RECT  35.112 17.088 35.28 17.104 ;
     RECT  35.304 17.088 35.472 17.104 ;
     RECT  35.496 17.088 35.664 17.104 ;
     RECT  35.688 17.088 35.856 17.104 ;
     RECT  35.88 17.088 36.048 17.104 ;
     RECT  36.072 17.088 36.24 17.104 ;
     RECT  36.264 17.088 36.432 17.104 ;
     RECT  36.456 17.088 36.624 17.104 ;
     RECT  36.648 17.088 36.816 17.104 ;
     RECT  36.84 17.088 37.008 17.104 ;
     RECT  37.032 17.088 37.2 17.104 ;
     RECT  37.224 17.088 37.392 17.104 ;
     RECT  37.416 17.088 37.584 17.104 ;
     RECT  37.608 17.088 37.776 17.104 ;
     RECT  37.8 17.088 37.968 17.104 ;
     RECT  37.992 17.088 38.16 17.104 ;
     RECT  38.184 17.088 38.352 17.104 ;
     RECT  38.376 17.088 38.544 17.104 ;
     RECT  38.568 17.088 38.736 17.104 ;
     RECT  38.76 17.088 38.928 17.104 ;
     RECT  38.952 17.088 39.12 17.104 ;
     RECT  39.144 17.088 39.312 17.104 ;
     RECT  39.336 17.088 39.504 17.104 ;
     RECT  39.528 17.088 39.696 17.104 ;
     RECT  39.72 17.088 39.888 17.104 ;
     RECT  39.912 17.088 40.08 17.104 ;
     RECT  40.104 17.088 40.272 17.104 ;
     RECT  40.296 17.088 40.464 17.104 ;
     RECT  40.488 17.088 40.656 17.104 ;
     RECT  40.68 17.088 40.848 17.104 ;
     RECT  40.872 17.088 41.04 17.104 ;
     RECT  41.064 17.088 41.232 17.104 ;
     RECT  41.256 17.088 41.424 17.104 ;
     RECT  41.448 17.088 41.616 17.104 ;
     RECT  41.64 17.088 41.808 17.104 ;
     RECT  41.832 17.088 42 17.104 ;
     RECT  42.024 17.088 42.192 17.104 ;
     RECT  42.216 17.088 42.384 17.104 ;
     RECT  42.408 17.088 42.576 17.104 ;
     RECT  42.6 17.088 42.768 17.104 ;
     RECT  42.792 17.088 42.96 17.104 ;
     RECT  42.984 17.088 43.152 17.104 ;
     RECT  43.176 17.088 43.344 17.104 ;
     RECT  43.368 17.088 43.536 17.104 ;
     RECT  43.56 17.088 43.728 17.104 ;
     RECT  43.752 17.088 43.92 17.104 ;
     RECT  43.944 17.088 44.112 17.104 ;
     RECT  44.136 17.088 44.304 17.104 ;
     RECT  44.328 17.088 44.496 17.104 ;
     RECT  44.52 17.088 44.688 17.104 ;
     RECT  44.712 17.088 44.88 17.104 ;
     RECT  44.904 17.088 45.072 17.104 ;
     RECT  45.096 17.088 45.264 17.104 ;
     RECT  45.288 17.088 45.456 17.104 ;
     RECT  45.48 17.088 45.648 17.104 ;
     RECT  45.672 17.088 45.84 17.104 ;
     RECT  45.864 17.088 46.032 17.104 ;
     RECT  46.056 17.088 46.224 17.104 ;
     RECT  46.248 17.088 46.416 17.104 ;
     RECT  46.44 17.088 46.608 17.104 ;
     RECT  46.632 17.088 46.8 17.104 ;
     RECT  46.824 17.088 46.992 17.104 ;
     RECT  47.016 17.088 47.184 17.104 ;
     RECT  47.208 17.088 47.376 17.104 ;
     RECT  47.4 17.088 47.568 17.104 ;
     RECT  47.592 17.088 47.76 17.104 ;
     RECT  47.784 17.088 47.952 17.104 ;
     RECT  47.976 17.088 48.144 17.104 ;
     RECT  48.168 17.088 48.336 17.104 ;
     RECT  48.36 17.088 48.528 17.104 ;
     RECT  48.552 17.088 48.72 17.104 ;
     RECT  48.744 17.088 48.912 17.104 ;
     RECT  48.936 17.088 49.104 17.104 ;
     RECT  49.128 17.088 49.296 17.104 ;
     RECT  49.32 17.088 49.488 17.104 ;
     RECT  49.512 17.088 49.68 17.104 ;
     RECT  49.704 17.088 49.872 17.104 ;
     RECT  49.896 17.088 50.064 17.104 ;
     RECT  50.088 17.088 50.256 17.104 ;
     RECT  50.28 17.088 50.448 17.104 ;
     RECT  50.472 17.088 50.64 17.104 ;
     RECT  50.664 17.088 50.832 17.104 ;
     RECT  50.856 17.088 51.024 17.104 ;
     RECT  51.048 17.088 51.216 17.104 ;
     RECT  51.24 17.088 51.408 17.104 ;
     RECT  51.432 17.088 51.6 17.104 ;
     RECT  51.624 17.088 51.792 17.104 ;
     RECT  51.816 17.088 51.984 17.104 ;
     RECT  52.008 17.088 52.176 17.104 ;
     RECT  52.2 17.088 52.368 17.104 ;
     RECT  52.392 17.088 52.56 17.104 ;
     RECT  52.584 17.088 52.752 17.104 ;
     RECT  52.776 17.088 52.944 17.104 ;
     RECT  52.968 17.088 53.136 17.104 ;
     RECT  53.16 17.088 53.328 17.104 ;
     RECT  53.352 17.088 53.52 17.104 ;
     RECT  53.544 17.088 53.712 17.104 ;
     RECT  53.736 17.088 53.904 17.104 ;
     RECT  53.928 17.088 54.096 17.104 ;
     RECT  54.12 17.088 54.288 17.104 ;
     RECT  54.312 17.088 54.48 17.104 ;
     RECT  54.504 17.088 54.672 17.104 ;
     RECT  54.696 17.088 54.864 17.104 ;
     RECT  54.888 17.088 55.056 17.104 ;
     RECT  55.08 17.088 55.248 17.104 ;
     RECT  55.272 17.088 55.44 17.104 ;
     RECT  55.464 17.088 55.632 17.104 ;
     RECT  55.656 17.088 55.824 17.104 ;
     RECT  55.848 17.088 56.016 17.104 ;
     RECT  47.544 0.133 47.616 0.144 ;
     RECT  47.736 0.133 47.808 0.144 ;
     RECT  47.928 0.133 48 0.144 ;
     RECT  48.12 0.133 48.192 0.144 ;
     RECT  48.312 0.133 48.384 0.144 ;
     RECT  48.504 0.133 48.576 0.144 ;
     RECT  48.696 0.133 48.72 0.144 ;
     RECT  41.784 9.683 42.9 11.221 ;
     RECT  43.416 10.883 44.592 11.893 ;
     RECT  41.784 11.221 42.768 11.413 ;
     RECT  54.744 12.035 56.208 12.131 ;
     RECT  54.456 12.131 56.208 13.045 ;
     RECT  54.456 13.045 56.016 13.093 ;
     RECT  54.012 13.667 55.056 14.821 ;
     RECT  56.04 14.387 57.024 14.963 ;
     RECT  2.4 15.143 2.688 16.549 ;
  END
END dsfd_dvrly_562_SN
END LIBRARY
